VERSION 5.8 ;
BUSBITCHARS "[]" ;
DIVIDERCHAR "/" ;
UNITS
    DATABASE MICRONS 1000 ;
END UNITS

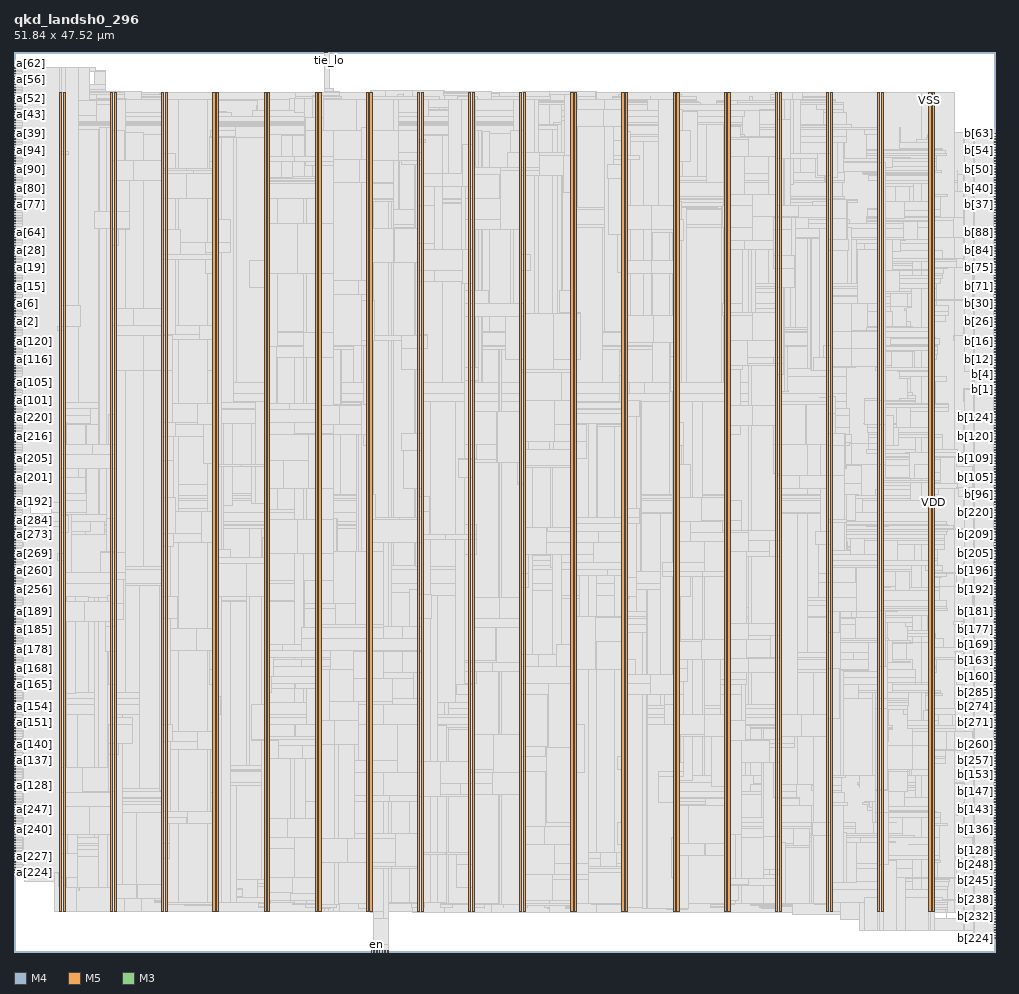
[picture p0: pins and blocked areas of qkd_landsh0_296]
MACRO qkd_landsh0_296
  FOREIGN qkd_landsh0_296 0 0 ;
  CLASS BLOCK ;
  SIZE 51.84 BY 47.52 ;
  PIN a[0]
    DIRECTION INPUT ;
    USE SIGNAL ;
    PORT
      LAYER M4 ;
        RECT  0 32.976 0.084 33 ;
    END
  END a[0]
  PIN a[100]
    DIRECTION INPUT ;
    USE SIGNAL ;
    PORT
      LAYER M4 ;
        RECT  0 28.944 0.084 28.968 ;
    END
  END a[100]
  PIN a[101]
    DIRECTION INPUT ;
    USE SIGNAL ;
    PORT
      LAYER M4 ;
        RECT  0 29.088 0.084 29.112 ;
    END
  END a[101]
  PIN a[102]
    DIRECTION INPUT ;
    USE SIGNAL ;
    PORT
      LAYER M4 ;
        RECT  0 29.232 0.084 29.256 ;
    END
  END a[102]
  PIN a[103]
    DIRECTION INPUT ;
    USE SIGNAL ;
    PORT
      LAYER M4 ;
        RECT  0 29.376 0.084 29.4 ;
    END
  END a[103]
  PIN a[104]
    DIRECTION INPUT ;
    USE SIGNAL ;
    PORT
      LAYER M4 ;
        RECT  0 29.52 0.084 29.544 ;
    END
  END a[104]
  PIN a[105]
    DIRECTION INPUT ;
    USE SIGNAL ;
    PORT
      LAYER M4 ;
        RECT  0 29.664 0.084 29.688 ;
    END
  END a[105]
  PIN a[106]
    DIRECTION INPUT ;
    USE SIGNAL ;
    PORT
      LAYER M4 ;
        RECT  0 29.808 0.084 29.832 ;
    END
  END a[106]
  PIN a[107]
    DIRECTION INPUT ;
    USE SIGNAL ;
    PORT
      LAYER M4 ;
        RECT  0 29.952 0.084 29.976 ;
    END
  END a[107]
  PIN a[108]
    DIRECTION INPUT ;
    USE SIGNAL ;
    PORT
      LAYER M4 ;
        RECT  0 30.096 0.084 30.12 ;
    END
  END a[108]
  PIN a[109]
    DIRECTION INPUT ;
    USE SIGNAL ;
    PORT
      LAYER M4 ;
        RECT  0 30.24 0.084 30.264 ;
    END
  END a[109]
  PIN a[10]
    DIRECTION INPUT ;
    USE SIGNAL ;
    PORT
      LAYER M4 ;
        RECT  0 34.416 0.084 34.44 ;
    END
  END a[10]
  PIN a[110]
    DIRECTION INPUT ;
    USE SIGNAL ;
    PORT
      LAYER M4 ;
        RECT  0 30.384 0.084 30.408 ;
    END
  END a[110]
  PIN a[111]
    DIRECTION INPUT ;
    USE SIGNAL ;
    PORT
      LAYER M4 ;
        RECT  0 30.528 0.084 30.552 ;
    END
  END a[111]
  PIN a[112]
    DIRECTION INPUT ;
    USE SIGNAL ;
    PORT
      LAYER M4 ;
        RECT  0 30.672 0.084 30.696 ;
    END
  END a[112]
  PIN a[113]
    DIRECTION INPUT ;
    USE SIGNAL ;
    PORT
      LAYER M4 ;
        RECT  0 30.816 0.084 30.84 ;
    END
  END a[113]
  PIN a[114]
    DIRECTION INPUT ;
    USE SIGNAL ;
    PORT
      LAYER M4 ;
        RECT  0 30.96 0.084 30.984 ;
    END
  END a[114]
  PIN a[115]
    DIRECTION INPUT ;
    USE SIGNAL ;
    PORT
      LAYER M4 ;
        RECT  0 31.104 0.084 31.128 ;
    END
  END a[115]
  PIN a[116]
    DIRECTION INPUT ;
    USE SIGNAL ;
    PORT
      LAYER M4 ;
        RECT  0 31.248 0.084 31.272 ;
    END
  END a[116]
  PIN a[117]
    DIRECTION INPUT ;
    USE SIGNAL ;
    PORT
      LAYER M4 ;
        RECT  0 31.392 0.084 31.416 ;
    END
  END a[117]
  PIN a[118]
    DIRECTION INPUT ;
    USE SIGNAL ;
    PORT
      LAYER M4 ;
        RECT  0 31.536 0.084 31.56 ;
    END
  END a[118]
  PIN a[119]
    DIRECTION INPUT ;
    USE SIGNAL ;
    PORT
      LAYER M4 ;
        RECT  0 31.68 0.084 31.704 ;
    END
  END a[119]
  PIN a[11]
    DIRECTION INPUT ;
    USE SIGNAL ;
    PORT
      LAYER M4 ;
        RECT  0 34.56 0.084 34.584 ;
    END
  END a[11]
  PIN a[120]
    DIRECTION INPUT ;
    USE SIGNAL ;
    PORT
      LAYER M4 ;
        RECT  0 31.824 0.084 31.848 ;
    END
  END a[120]
  PIN a[121]
    DIRECTION INPUT ;
    USE SIGNAL ;
    PORT
      LAYER M4 ;
        RECT  0 31.968 0.084 31.992 ;
    END
  END a[121]
  PIN a[122]
    DIRECTION INPUT ;
    USE SIGNAL ;
    PORT
      LAYER M4 ;
        RECT  0 32.112 0.084 32.136 ;
    END
  END a[122]
  PIN a[123]
    DIRECTION INPUT ;
    USE SIGNAL ;
    PORT
      LAYER M4 ;
        RECT  0 32.256 0.084 32.28 ;
    END
  END a[123]
  PIN a[124]
    DIRECTION INPUT ;
    USE SIGNAL ;
    PORT
      LAYER M4 ;
        RECT  0 32.4 0.084 32.424 ;
    END
  END a[124]
  PIN a[125]
    DIRECTION INPUT ;
    USE SIGNAL ;
    PORT
      LAYER M4 ;
        RECT  0 32.544 0.084 32.568 ;
    END
  END a[125]
  PIN a[126]
    DIRECTION INPUT ;
    USE SIGNAL ;
    PORT
      LAYER M4 ;
        RECT  0 32.688 0.084 32.712 ;
    END
  END a[126]
  PIN a[127]
    DIRECTION INPUT ;
    USE SIGNAL ;
    PORT
      LAYER M4 ;
        RECT  0 32.832 0.084 32.856 ;
    END
  END a[127]
  PIN a[128]
    DIRECTION INPUT ;
    USE SIGNAL ;
    PORT
      LAYER M4 ;
        RECT  0 8.784 0.084 8.808 ;
    END
  END a[128]
  PIN a[129]
    DIRECTION INPUT ;
    USE SIGNAL ;
    PORT
      LAYER M4 ;
        RECT  0 8.928 0.084 8.952 ;
    END
  END a[129]
  PIN a[12]
    DIRECTION INPUT ;
    USE SIGNAL ;
    PORT
      LAYER M4 ;
        RECT  0 34.704 0.084 34.728 ;
    END
  END a[12]
  PIN a[130]
    DIRECTION INPUT ;
    USE SIGNAL ;
    PORT
      LAYER M4 ;
        RECT  0 9.072 0.084 9.096 ;
    END
  END a[130]
  PIN a[131]
    DIRECTION INPUT ;
    USE SIGNAL ;
    PORT
      LAYER M4 ;
        RECT  0 9.216 0.084 9.24 ;
    END
  END a[131]
  PIN a[132]
    DIRECTION INPUT ;
    USE SIGNAL ;
    PORT
      LAYER M4 ;
        RECT  0 9.36 0.084 9.384 ;
    END
  END a[132]
  PIN a[133]
    DIRECTION INPUT ;
    USE SIGNAL ;
    PORT
      LAYER M4 ;
        RECT  0 9.504 0.084 9.528 ;
    END
  END a[133]
  PIN a[134]
    DIRECTION INPUT ;
    USE SIGNAL ;
    PORT
      LAYER M4 ;
        RECT  0 9.648 0.084 9.672 ;
    END
  END a[134]
  PIN a[135]
    DIRECTION INPUT ;
    USE SIGNAL ;
    PORT
      LAYER M4 ;
        RECT  0 9.792 0.084 9.816 ;
    END
  END a[135]
  PIN a[136]
    DIRECTION INPUT ;
    USE SIGNAL ;
    PORT
      LAYER M4 ;
        RECT  0 9.936 0.084 9.96 ;
    END
  END a[136]
  PIN a[137]
    DIRECTION INPUT ;
    USE SIGNAL ;
    PORT
      LAYER M4 ;
        RECT  0 10.08 0.084 10.104 ;
    END
  END a[137]
  PIN a[138]
    DIRECTION INPUT ;
    USE SIGNAL ;
    PORT
      LAYER M4 ;
        RECT  0 10.224 0.084 10.248 ;
    END
  END a[138]
  PIN a[139]
    DIRECTION INPUT ;
    USE SIGNAL ;
    PORT
      LAYER M4 ;
        RECT  0 10.368 0.084 10.392 ;
    END
  END a[139]
  PIN a[13]
    DIRECTION INPUT ;
    USE SIGNAL ;
    PORT
      LAYER M4 ;
        RECT  0 34.848 0.084 34.872 ;
    END
  END a[13]
  PIN a[140]
    DIRECTION INPUT ;
    USE SIGNAL ;
    PORT
      LAYER M4 ;
        RECT  0 10.512 0.084 10.536 ;
    END
  END a[140]
  PIN a[141]
    DIRECTION INPUT ;
    USE SIGNAL ;
    PORT
      LAYER M4 ;
        RECT  0 10.656 0.084 10.68 ;
    END
  END a[141]
  PIN a[142]
    DIRECTION INPUT ;
    USE SIGNAL ;
    PORT
      LAYER M4 ;
        RECT  0 10.8 0.084 10.824 ;
    END
  END a[142]
  PIN a[143]
    DIRECTION INPUT ;
    USE SIGNAL ;
    PORT
      LAYER M4 ;
        RECT  0 10.944 0.084 10.968 ;
    END
  END a[143]
  PIN a[144]
    DIRECTION INPUT ;
    USE SIGNAL ;
    PORT
      LAYER M4 ;
        RECT  0 11.088 0.084 11.112 ;
    END
  END a[144]
  PIN a[145]
    DIRECTION INPUT ;
    USE SIGNAL ;
    PORT
      LAYER M4 ;
        RECT  0 11.232 0.084 11.256 ;
    END
  END a[145]
  PIN a[146]
    DIRECTION INPUT ;
    USE SIGNAL ;
    PORT
      LAYER M4 ;
        RECT  0 11.376 0.084 11.4 ;
    END
  END a[146]
  PIN a[147]
    DIRECTION INPUT ;
    USE SIGNAL ;
    PORT
      LAYER M4 ;
        RECT  0 11.52 0.084 11.544 ;
    END
  END a[147]
  PIN a[148]
    DIRECTION INPUT ;
    USE SIGNAL ;
    PORT
      LAYER M4 ;
        RECT  0 11.664 0.084 11.688 ;
    END
  END a[148]
  PIN a[149]
    DIRECTION INPUT ;
    USE SIGNAL ;
    PORT
      LAYER M4 ;
        RECT  0 11.808 0.084 11.832 ;
    END
  END a[149]
  PIN a[14]
    DIRECTION INPUT ;
    USE SIGNAL ;
    PORT
      LAYER M4 ;
        RECT  0 34.992 0.084 35.016 ;
    END
  END a[14]
  PIN a[150]
    DIRECTION INPUT ;
    USE SIGNAL ;
    PORT
      LAYER M4 ;
        RECT  0 11.952 0.084 11.976 ;
    END
  END a[150]
  PIN a[151]
    DIRECTION INPUT ;
    USE SIGNAL ;
    PORT
      LAYER M4 ;
        RECT  0 12.096 0.084 12.12 ;
    END
  END a[151]
  PIN a[152]
    DIRECTION INPUT ;
    USE SIGNAL ;
    PORT
      LAYER M4 ;
        RECT  0 12.24 0.084 12.264 ;
    END
  END a[152]
  PIN a[153]
    DIRECTION INPUT ;
    USE SIGNAL ;
    PORT
      LAYER M4 ;
        RECT  0 12.384 0.084 12.408 ;
    END
  END a[153]
  PIN a[154]
    DIRECTION INPUT ;
    USE SIGNAL ;
    PORT
      LAYER M4 ;
        RECT  0 12.528 0.084 12.552 ;
    END
  END a[154]
  PIN a[155]
    DIRECTION INPUT ;
    USE SIGNAL ;
    PORT
      LAYER M4 ;
        RECT  0 12.672 0.084 12.696 ;
    END
  END a[155]
  PIN a[156]
    DIRECTION INPUT ;
    USE SIGNAL ;
    PORT
      LAYER M4 ;
        RECT  0 12.816 0.084 12.84 ;
    END
  END a[156]
  PIN a[157]
    DIRECTION INPUT ;
    USE SIGNAL ;
    PORT
      LAYER M4 ;
        RECT  0 12.96 0.084 12.984 ;
    END
  END a[157]
  PIN a[158]
    DIRECTION INPUT ;
    USE SIGNAL ;
    PORT
      LAYER M4 ;
        RECT  0 13.104 0.084 13.128 ;
    END
  END a[158]
  PIN a[159]
    DIRECTION INPUT ;
    USE SIGNAL ;
    PORT
      LAYER M4 ;
        RECT  0 13.248 0.084 13.272 ;
    END
  END a[159]
  PIN a[15]
    DIRECTION INPUT ;
    USE SIGNAL ;
    PORT
      LAYER M4 ;
        RECT  0 35.136 0.084 35.16 ;
    END
  END a[15]
  PIN a[160]
    DIRECTION INPUT ;
    USE SIGNAL ;
    PORT
      LAYER M4 ;
        RECT  0 13.392 0.084 13.416 ;
    END
  END a[160]
  PIN a[161]
    DIRECTION INPUT ;
    USE SIGNAL ;
    PORT
      LAYER M4 ;
        RECT  0 13.536 0.084 13.56 ;
    END
  END a[161]
  PIN a[162]
    DIRECTION INPUT ;
    USE SIGNAL ;
    PORT
      LAYER M4 ;
        RECT  0 13.68 0.084 13.704 ;
    END
  END a[162]
  PIN a[163]
    DIRECTION INPUT ;
    USE SIGNAL ;
    PORT
      LAYER M4 ;
        RECT  0 13.824 0.084 13.848 ;
    END
  END a[163]
  PIN a[164]
    DIRECTION INPUT ;
    USE SIGNAL ;
    PORT
      LAYER M4 ;
        RECT  0 13.968 0.084 13.992 ;
    END
  END a[164]
  PIN a[165]
    DIRECTION INPUT ;
    USE SIGNAL ;
    PORT
      LAYER M4 ;
        RECT  0 14.112 0.084 14.136 ;
    END
  END a[165]
  PIN a[166]
    DIRECTION INPUT ;
    USE SIGNAL ;
    PORT
      LAYER M4 ;
        RECT  0 14.256 0.084 14.28 ;
    END
  END a[166]
  PIN a[167]
    DIRECTION INPUT ;
    USE SIGNAL ;
    PORT
      LAYER M4 ;
        RECT  0 14.4 0.084 14.424 ;
    END
  END a[167]
  PIN a[168]
    DIRECTION INPUT ;
    USE SIGNAL ;
    PORT
      LAYER M4 ;
        RECT  0 14.544 0.084 14.568 ;
    END
  END a[168]
  PIN a[169]
    DIRECTION INPUT ;
    USE SIGNAL ;
    PORT
      LAYER M4 ;
        RECT  0 14.688 0.084 14.712 ;
    END
  END a[169]
  PIN a[16]
    DIRECTION INPUT ;
    USE SIGNAL ;
    PORT
      LAYER M4 ;
        RECT  0 35.28 0.084 35.304 ;
    END
  END a[16]
  PIN a[170]
    DIRECTION INPUT ;
    USE SIGNAL ;
    PORT
      LAYER M4 ;
        RECT  0 14.832 0.084 14.856 ;
    END
  END a[170]
  PIN a[171]
    DIRECTION INPUT ;
    USE SIGNAL ;
    PORT
      LAYER M4 ;
        RECT  0 14.976 0.084 15 ;
    END
  END a[171]
  PIN a[172]
    DIRECTION INPUT ;
    USE SIGNAL ;
    PORT
      LAYER M4 ;
        RECT  0 15.12 0.084 15.144 ;
    END
  END a[172]
  PIN a[173]
    DIRECTION INPUT ;
    USE SIGNAL ;
    PORT
      LAYER M4 ;
        RECT  0 15.264 0.084 15.288 ;
    END
  END a[173]
  PIN a[174]
    DIRECTION INPUT ;
    USE SIGNAL ;
    PORT
      LAYER M4 ;
        RECT  0 15.408 0.084 15.432 ;
    END
  END a[174]
  PIN a[175]
    DIRECTION INPUT ;
    USE SIGNAL ;
    PORT
      LAYER M4 ;
        RECT  0 15.552 0.084 15.576 ;
    END
  END a[175]
  PIN a[176]
    DIRECTION INPUT ;
    USE SIGNAL ;
    PORT
      LAYER M4 ;
        RECT  0 15.696 0.084 15.72 ;
    END
  END a[176]
  PIN a[177]
    DIRECTION INPUT ;
    USE SIGNAL ;
    PORT
      LAYER M4 ;
        RECT  0 15.84 0.084 15.864 ;
    END
  END a[177]
  PIN a[178]
    DIRECTION INPUT ;
    USE SIGNAL ;
    PORT
      LAYER M4 ;
        RECT  0 15.984 0.084 16.008 ;
    END
  END a[178]
  PIN a[179]
    DIRECTION INPUT ;
    USE SIGNAL ;
    PORT
      LAYER M4 ;
        RECT  0 16.128 0.084 16.152 ;
    END
  END a[179]
  PIN a[17]
    DIRECTION INPUT ;
    USE SIGNAL ;
    PORT
      LAYER M4 ;
        RECT  0 35.424 0.084 35.448 ;
    END
  END a[17]
  PIN a[180]
    DIRECTION INPUT ;
    USE SIGNAL ;
    PORT
      LAYER M4 ;
        RECT  0 16.272 0.084 16.296 ;
    END
  END a[180]
  PIN a[181]
    DIRECTION INPUT ;
    USE SIGNAL ;
    PORT
      LAYER M4 ;
        RECT  0 16.416 0.084 16.44 ;
    END
  END a[181]
  PIN a[182]
    DIRECTION INPUT ;
    USE SIGNAL ;
    PORT
      LAYER M4 ;
        RECT  0 16.56 0.084 16.584 ;
    END
  END a[182]
  PIN a[183]
    DIRECTION INPUT ;
    USE SIGNAL ;
    PORT
      LAYER M4 ;
        RECT  0 16.704 0.084 16.728 ;
    END
  END a[183]
  PIN a[184]
    DIRECTION INPUT ;
    USE SIGNAL ;
    PORT
      LAYER M4 ;
        RECT  0 16.848 0.084 16.872 ;
    END
  END a[184]
  PIN a[185]
    DIRECTION INPUT ;
    USE SIGNAL ;
    PORT
      LAYER M4 ;
        RECT  0 16.992 0.084 17.016 ;
    END
  END a[185]
  PIN a[186]
    DIRECTION INPUT ;
    USE SIGNAL ;
    PORT
      LAYER M4 ;
        RECT  0 17.136 0.084 17.16 ;
    END
  END a[186]
  PIN a[187]
    DIRECTION INPUT ;
    USE SIGNAL ;
    PORT
      LAYER M4 ;
        RECT  0 17.28 0.084 17.304 ;
    END
  END a[187]
  PIN a[188]
    DIRECTION INPUT ;
    USE SIGNAL ;
    PORT
      LAYER M4 ;
        RECT  0 17.424 0.084 17.448 ;
    END
  END a[188]
  PIN a[189]
    DIRECTION INPUT ;
    USE SIGNAL ;
    PORT
      LAYER M4 ;
        RECT  0 17.568 0.084 17.592 ;
    END
  END a[189]
  PIN a[18]
    DIRECTION INPUT ;
    USE SIGNAL ;
    PORT
      LAYER M4 ;
        RECT  0 35.568 0.084 35.592 ;
    END
  END a[18]
  PIN a[190]
    DIRECTION INPUT ;
    USE SIGNAL ;
    PORT
      LAYER M4 ;
        RECT  0 17.712 0.084 17.736 ;
    END
  END a[190]
  PIN a[191]
    DIRECTION INPUT ;
    USE SIGNAL ;
    PORT
      LAYER M4 ;
        RECT  0 17.856 0.084 17.88 ;
    END
  END a[191]
  PIN a[192]
    DIRECTION INPUT ;
    USE SIGNAL ;
    PORT
      LAYER M4 ;
        RECT  0 23.76 0.084 23.784 ;
    END
  END a[192]
  PIN a[193]
    DIRECTION INPUT ;
    USE SIGNAL ;
    PORT
      LAYER M4 ;
        RECT  0 23.904 0.084 23.928 ;
    END
  END a[193]
  PIN a[194]
    DIRECTION INPUT ;
    USE SIGNAL ;
    PORT
      LAYER M4 ;
        RECT  0 24.048 0.084 24.072 ;
    END
  END a[194]
  PIN a[195]
    DIRECTION INPUT ;
    USE SIGNAL ;
    PORT
      LAYER M4 ;
        RECT  0 24.192 0.084 24.216 ;
    END
  END a[195]
  PIN a[196]
    DIRECTION INPUT ;
    USE SIGNAL ;
    PORT
      LAYER M4 ;
        RECT  0 24.336 0.084 24.36 ;
    END
  END a[196]
  PIN a[197]
    DIRECTION INPUT ;
    USE SIGNAL ;
    PORT
      LAYER M4 ;
        RECT  0 24.48 0.084 24.504 ;
    END
  END a[197]
  PIN a[198]
    DIRECTION INPUT ;
    USE SIGNAL ;
    PORT
      LAYER M4 ;
        RECT  0 24.624 0.084 24.648 ;
    END
  END a[198]
  PIN a[199]
    DIRECTION INPUT ;
    USE SIGNAL ;
    PORT
      LAYER M4 ;
        RECT  0 24.768 0.084 24.792 ;
    END
  END a[199]
  PIN a[19]
    DIRECTION INPUT ;
    USE SIGNAL ;
    PORT
      LAYER M4 ;
        RECT  0 35.712 0.084 35.736 ;
    END
  END a[19]
  PIN a[1]
    DIRECTION INPUT ;
    USE SIGNAL ;
    PORT
      LAYER M4 ;
        RECT  0 33.12 0.084 33.144 ;
    END
  END a[1]
  PIN a[200]
    DIRECTION INPUT ;
    USE SIGNAL ;
    PORT
      LAYER M4 ;
        RECT  0 24.912 0.084 24.936 ;
    END
  END a[200]
  PIN a[201]
    DIRECTION INPUT ;
    USE SIGNAL ;
    PORT
      LAYER M4 ;
        RECT  0 25.056 0.084 25.08 ;
    END
  END a[201]
  PIN a[202]
    DIRECTION INPUT ;
    USE SIGNAL ;
    PORT
      LAYER M4 ;
        RECT  0 25.2 0.084 25.224 ;
    END
  END a[202]
  PIN a[203]
    DIRECTION INPUT ;
    USE SIGNAL ;
    PORT
      LAYER M4 ;
        RECT  0 25.344 0.084 25.368 ;
    END
  END a[203]
  PIN a[204]
    DIRECTION INPUT ;
    USE SIGNAL ;
    PORT
      LAYER M4 ;
        RECT  0 25.488 0.084 25.512 ;
    END
  END a[204]
  PIN a[205]
    DIRECTION INPUT ;
    USE SIGNAL ;
    PORT
      LAYER M4 ;
        RECT  0 25.632 0.084 25.656 ;
    END
  END a[205]
  PIN a[206]
    DIRECTION INPUT ;
    USE SIGNAL ;
    PORT
      LAYER M4 ;
        RECT  0 25.776 0.084 25.8 ;
    END
  END a[206]
  PIN a[207]
    DIRECTION INPUT ;
    USE SIGNAL ;
    PORT
      LAYER M4 ;
        RECT  0 25.92 0.084 25.944 ;
    END
  END a[207]
  PIN a[208]
    DIRECTION INPUT ;
    USE SIGNAL ;
    PORT
      LAYER M4 ;
        RECT  0 26.064 0.084 26.088 ;
    END
  END a[208]
  PIN a[209]
    DIRECTION INPUT ;
    USE SIGNAL ;
    PORT
      LAYER M4 ;
        RECT  0 26.208 0.084 26.232 ;
    END
  END a[209]
  PIN a[20]
    DIRECTION INPUT ;
    USE SIGNAL ;
    PORT
      LAYER M4 ;
        RECT  0 35.856 0.084 35.88 ;
    END
  END a[20]
  PIN a[210]
    DIRECTION INPUT ;
    USE SIGNAL ;
    PORT
      LAYER M4 ;
        RECT  0 26.352 0.084 26.376 ;
    END
  END a[210]
  PIN a[211]
    DIRECTION INPUT ;
    USE SIGNAL ;
    PORT
      LAYER M4 ;
        RECT  0 26.496 0.084 26.52 ;
    END
  END a[211]
  PIN a[212]
    DIRECTION INPUT ;
    USE SIGNAL ;
    PORT
      LAYER M4 ;
        RECT  0 26.64 0.084 26.664 ;
    END
  END a[212]
  PIN a[213]
    DIRECTION INPUT ;
    USE SIGNAL ;
    PORT
      LAYER M4 ;
        RECT  0 26.784 0.084 26.808 ;
    END
  END a[213]
  PIN a[214]
    DIRECTION INPUT ;
    USE SIGNAL ;
    PORT
      LAYER M4 ;
        RECT  0 26.928 0.084 26.952 ;
    END
  END a[214]
  PIN a[215]
    DIRECTION INPUT ;
    USE SIGNAL ;
    PORT
      LAYER M4 ;
        RECT  0 27.072 0.084 27.096 ;
    END
  END a[215]
  PIN a[216]
    DIRECTION INPUT ;
    USE SIGNAL ;
    PORT
      LAYER M4 ;
        RECT  0 27.216 0.084 27.24 ;
    END
  END a[216]
  PIN a[217]
    DIRECTION INPUT ;
    USE SIGNAL ;
    PORT
      LAYER M4 ;
        RECT  0 27.36 0.084 27.384 ;
    END
  END a[217]
  PIN a[218]
    DIRECTION INPUT ;
    USE SIGNAL ;
    PORT
      LAYER M4 ;
        RECT  0 27.504 0.084 27.528 ;
    END
  END a[218]
  PIN a[219]
    DIRECTION INPUT ;
    USE SIGNAL ;
    PORT
      LAYER M4 ;
        RECT  0 27.648 0.084 27.672 ;
    END
  END a[219]
  PIN a[21]
    DIRECTION INPUT ;
    USE SIGNAL ;
    PORT
      LAYER M4 ;
        RECT  0 36 0.084 36.024 ;
    END
  END a[21]
  PIN a[220]
    DIRECTION INPUT ;
    USE SIGNAL ;
    PORT
      LAYER M4 ;
        RECT  0 27.792 0.084 27.816 ;
    END
  END a[220]
  PIN a[221]
    DIRECTION INPUT ;
    USE SIGNAL ;
    PORT
      LAYER M4 ;
        RECT  0 27.936 0.084 27.96 ;
    END
  END a[221]
  PIN a[222]
    DIRECTION INPUT ;
    USE SIGNAL ;
    PORT
      LAYER M4 ;
        RECT  0 28.08 0.084 28.104 ;
    END
  END a[222]
  PIN a[223]
    DIRECTION INPUT ;
    USE SIGNAL ;
    PORT
      LAYER M4 ;
        RECT  0 28.224 0.084 28.248 ;
    END
  END a[223]
  PIN a[224]
    DIRECTION INPUT ;
    USE SIGNAL ;
    PORT
      LAYER M4 ;
        RECT  0 4.176 0.084 4.2 ;
    END
  END a[224]
  PIN a[225]
    DIRECTION INPUT ;
    USE SIGNAL ;
    PORT
      LAYER M4 ;
        RECT  0 4.32 0.084 4.344 ;
    END
  END a[225]
  PIN a[226]
    DIRECTION INPUT ;
    USE SIGNAL ;
    PORT
      LAYER M4 ;
        RECT  0 4.464 0.084 4.488 ;
    END
  END a[226]
  PIN a[227]
    DIRECTION INPUT ;
    USE SIGNAL ;
    PORT
      LAYER M4 ;
        RECT  0 4.608 0.084 4.632 ;
    END
  END a[227]
  PIN a[228]
    DIRECTION INPUT ;
    USE SIGNAL ;
    PORT
      LAYER M4 ;
        RECT  0 4.752 0.084 4.776 ;
    END
  END a[228]
  PIN a[229]
    DIRECTION INPUT ;
    USE SIGNAL ;
    PORT
      LAYER M4 ;
        RECT  0 4.896 0.084 4.92 ;
    END
  END a[229]
  PIN a[22]
    DIRECTION INPUT ;
    USE SIGNAL ;
    PORT
      LAYER M4 ;
        RECT  0 36.144 0.084 36.168 ;
    END
  END a[22]
  PIN a[230]
    DIRECTION INPUT ;
    USE SIGNAL ;
    PORT
      LAYER M4 ;
        RECT  0 5.04 0.084 5.064 ;
    END
  END a[230]
  PIN a[231]
    DIRECTION INPUT ;
    USE SIGNAL ;
    PORT
      LAYER M4 ;
        RECT  0 5.184 0.084 5.208 ;
    END
  END a[231]
  PIN a[232]
    DIRECTION INPUT ;
    USE SIGNAL ;
    PORT
      LAYER M4 ;
        RECT  0 5.328 0.084 5.352 ;
    END
  END a[232]
  PIN a[233]
    DIRECTION INPUT ;
    USE SIGNAL ;
    PORT
      LAYER M4 ;
        RECT  0 5.472 0.084 5.496 ;
    END
  END a[233]
  PIN a[234]
    DIRECTION INPUT ;
    USE SIGNAL ;
    PORT
      LAYER M4 ;
        RECT  0 5.616 0.084 5.64 ;
    END
  END a[234]
  PIN a[235]
    DIRECTION INPUT ;
    USE SIGNAL ;
    PORT
      LAYER M4 ;
        RECT  0 5.76 0.084 5.784 ;
    END
  END a[235]
  PIN a[236]
    DIRECTION INPUT ;
    USE SIGNAL ;
    PORT
      LAYER M4 ;
        RECT  0 5.904 0.084 5.928 ;
    END
  END a[236]
  PIN a[237]
    DIRECTION INPUT ;
    USE SIGNAL ;
    PORT
      LAYER M4 ;
        RECT  0 6.048 0.084 6.072 ;
    END
  END a[237]
  PIN a[238]
    DIRECTION INPUT ;
    USE SIGNAL ;
    PORT
      LAYER M4 ;
        RECT  0 6.192 0.084 6.216 ;
    END
  END a[238]
  PIN a[239]
    DIRECTION INPUT ;
    USE SIGNAL ;
    PORT
      LAYER M4 ;
        RECT  0 6.336 0.084 6.36 ;
    END
  END a[239]
  PIN a[23]
    DIRECTION INPUT ;
    USE SIGNAL ;
    PORT
      LAYER M4 ;
        RECT  0 36.288 0.084 36.312 ;
    END
  END a[23]
  PIN a[240]
    DIRECTION INPUT ;
    USE SIGNAL ;
    PORT
      LAYER M4 ;
        RECT  0 6.48 0.084 6.504 ;
    END
  END a[240]
  PIN a[241]
    DIRECTION INPUT ;
    USE SIGNAL ;
    PORT
      LAYER M4 ;
        RECT  0 6.624 0.084 6.648 ;
    END
  END a[241]
  PIN a[242]
    DIRECTION INPUT ;
    USE SIGNAL ;
    PORT
      LAYER M4 ;
        RECT  0 6.768 0.084 6.792 ;
    END
  END a[242]
  PIN a[243]
    DIRECTION INPUT ;
    USE SIGNAL ;
    PORT
      LAYER M4 ;
        RECT  0 6.912 0.084 6.936 ;
    END
  END a[243]
  PIN a[244]
    DIRECTION INPUT ;
    USE SIGNAL ;
    PORT
      LAYER M4 ;
        RECT  0 7.056 0.084 7.08 ;
    END
  END a[244]
  PIN a[245]
    DIRECTION INPUT ;
    USE SIGNAL ;
    PORT
      LAYER M4 ;
        RECT  0 7.2 0.084 7.224 ;
    END
  END a[245]
  PIN a[246]
    DIRECTION INPUT ;
    USE SIGNAL ;
    PORT
      LAYER M4 ;
        RECT  0 7.344 0.084 7.368 ;
    END
  END a[246]
  PIN a[247]
    DIRECTION INPUT ;
    USE SIGNAL ;
    PORT
      LAYER M4 ;
        RECT  0 7.488 0.084 7.512 ;
    END
  END a[247]
  PIN a[248]
    DIRECTION INPUT ;
    USE SIGNAL ;
    PORT
      LAYER M4 ;
        RECT  0 7.632 0.084 7.656 ;
    END
  END a[248]
  PIN a[249]
    DIRECTION INPUT ;
    USE SIGNAL ;
    PORT
      LAYER M4 ;
        RECT  0 7.776 0.084 7.8 ;
    END
  END a[249]
  PIN a[24]
    DIRECTION INPUT ;
    USE SIGNAL ;
    PORT
      LAYER M4 ;
        RECT  0 36.432 0.084 36.456 ;
    END
  END a[24]
  PIN a[250]
    DIRECTION INPUT ;
    USE SIGNAL ;
    PORT
      LAYER M4 ;
        RECT  0 7.92 0.084 7.944 ;
    END
  END a[250]
  PIN a[251]
    DIRECTION INPUT ;
    USE SIGNAL ;
    PORT
      LAYER M4 ;
        RECT  0 8.064 0.084 8.088 ;
    END
  END a[251]
  PIN a[252]
    DIRECTION INPUT ;
    USE SIGNAL ;
    PORT
      LAYER M4 ;
        RECT  0 8.208 0.084 8.232 ;
    END
  END a[252]
  PIN a[253]
    DIRECTION INPUT ;
    USE SIGNAL ;
    PORT
      LAYER M4 ;
        RECT  0 8.352 0.084 8.376 ;
    END
  END a[253]
  PIN a[254]
    DIRECTION INPUT ;
    USE SIGNAL ;
    PORT
      LAYER M4 ;
        RECT  0 8.496 0.084 8.52 ;
    END
  END a[254]
  PIN a[255]
    DIRECTION INPUT ;
    USE SIGNAL ;
    PORT
      LAYER M4 ;
        RECT  0 8.64 0.084 8.664 ;
    END
  END a[255]
  PIN a[256]
    DIRECTION INPUT ;
    USE SIGNAL ;
    PORT
      LAYER M4 ;
        RECT  0 19.152 0.084 19.176 ;
    END
  END a[256]
  PIN a[257]
    DIRECTION INPUT ;
    USE SIGNAL ;
    PORT
      LAYER M4 ;
        RECT  0 19.296 0.084 19.32 ;
    END
  END a[257]
  PIN a[258]
    DIRECTION INPUT ;
    USE SIGNAL ;
    PORT
      LAYER M4 ;
        RECT  0 19.44 0.084 19.464 ;
    END
  END a[258]
  PIN a[259]
    DIRECTION INPUT ;
    USE SIGNAL ;
    PORT
      LAYER M4 ;
        RECT  0 19.584 0.084 19.608 ;
    END
  END a[259]
  PIN a[25]
    DIRECTION INPUT ;
    USE SIGNAL ;
    PORT
      LAYER M4 ;
        RECT  0 36.576 0.084 36.6 ;
    END
  END a[25]
  PIN a[260]
    DIRECTION INPUT ;
    USE SIGNAL ;
    PORT
      LAYER M4 ;
        RECT  0 19.728 0.084 19.752 ;
    END
  END a[260]
  PIN a[261]
    DIRECTION INPUT ;
    USE SIGNAL ;
    PORT
      LAYER M4 ;
        RECT  0 19.872 0.084 19.896 ;
    END
  END a[261]
  PIN a[262]
    DIRECTION INPUT ;
    USE SIGNAL ;
    PORT
      LAYER M4 ;
        RECT  0 20.016 0.084 20.04 ;
    END
  END a[262]
  PIN a[263]
    DIRECTION INPUT ;
    USE SIGNAL ;
    PORT
      LAYER M4 ;
        RECT  0 20.16 0.084 20.184 ;
    END
  END a[263]
  PIN a[264]
    DIRECTION INPUT ;
    USE SIGNAL ;
    PORT
      LAYER M4 ;
        RECT  0 20.304 0.084 20.328 ;
    END
  END a[264]
  PIN a[265]
    DIRECTION INPUT ;
    USE SIGNAL ;
    PORT
      LAYER M4 ;
        RECT  0 20.448 0.084 20.472 ;
    END
  END a[265]
  PIN a[266]
    DIRECTION INPUT ;
    USE SIGNAL ;
    PORT
      LAYER M4 ;
        RECT  0 20.592 0.084 20.616 ;
    END
  END a[266]
  PIN a[267]
    DIRECTION INPUT ;
    USE SIGNAL ;
    PORT
      LAYER M4 ;
        RECT  0 20.736 0.084 20.76 ;
    END
  END a[267]
  PIN a[268]
    DIRECTION INPUT ;
    USE SIGNAL ;
    PORT
      LAYER M4 ;
        RECT  0 20.88 0.084 20.904 ;
    END
  END a[268]
  PIN a[269]
    DIRECTION INPUT ;
    USE SIGNAL ;
    PORT
      LAYER M4 ;
        RECT  0 21.024 0.084 21.048 ;
    END
  END a[269]
  PIN a[26]
    DIRECTION INPUT ;
    USE SIGNAL ;
    PORT
      LAYER M4 ;
        RECT  0 36.72 0.084 36.744 ;
    END
  END a[26]
  PIN a[270]
    DIRECTION INPUT ;
    USE SIGNAL ;
    PORT
      LAYER M4 ;
        RECT  0 21.168 0.084 21.192 ;
    END
  END a[270]
  PIN a[271]
    DIRECTION INPUT ;
    USE SIGNAL ;
    PORT
      LAYER M4 ;
        RECT  0 21.312 0.084 21.336 ;
    END
  END a[271]
  PIN a[272]
    DIRECTION INPUT ;
    USE SIGNAL ;
    PORT
      LAYER M4 ;
        RECT  0 21.456 0.084 21.48 ;
    END
  END a[272]
  PIN a[273]
    DIRECTION INPUT ;
    USE SIGNAL ;
    PORT
      LAYER M4 ;
        RECT  0 21.6 0.084 21.624 ;
    END
  END a[273]
  PIN a[274]
    DIRECTION INPUT ;
    USE SIGNAL ;
    PORT
      LAYER M4 ;
        RECT  0 21.744 0.084 21.768 ;
    END
  END a[274]
  PIN a[275]
    DIRECTION INPUT ;
    USE SIGNAL ;
    PORT
      LAYER M4 ;
        RECT  0 21.888 0.084 21.912 ;
    END
  END a[275]
  PIN a[276]
    DIRECTION INPUT ;
    USE SIGNAL ;
    PORT
      LAYER M4 ;
        RECT  0 22.032 0.084 22.056 ;
    END
  END a[276]
  PIN a[277]
    DIRECTION INPUT ;
    USE SIGNAL ;
    PORT
      LAYER M4 ;
        RECT  0 22.176 0.084 22.2 ;
    END
  END a[277]
  PIN a[278]
    DIRECTION INPUT ;
    USE SIGNAL ;
    PORT
      LAYER M4 ;
        RECT  0 22.32 0.084 22.344 ;
    END
  END a[278]
  PIN a[279]
    DIRECTION INPUT ;
    USE SIGNAL ;
    PORT
      LAYER M4 ;
        RECT  0 22.464 0.084 22.488 ;
    END
  END a[279]
  PIN a[27]
    DIRECTION INPUT ;
    USE SIGNAL ;
    PORT
      LAYER M4 ;
        RECT  0 36.864 0.084 36.888 ;
    END
  END a[27]
  PIN a[280]
    DIRECTION INPUT ;
    USE SIGNAL ;
    PORT
      LAYER M4 ;
        RECT  0 22.608 0.084 22.632 ;
    END
  END a[280]
  PIN a[281]
    DIRECTION INPUT ;
    USE SIGNAL ;
    PORT
      LAYER M4 ;
        RECT  0 22.752 0.084 22.776 ;
    END
  END a[281]
  PIN a[282]
    DIRECTION INPUT ;
    USE SIGNAL ;
    PORT
      LAYER M4 ;
        RECT  0 22.896 0.084 22.92 ;
    END
  END a[282]
  PIN a[283]
    DIRECTION INPUT ;
    USE SIGNAL ;
    PORT
      LAYER M4 ;
        RECT  0 23.04 0.084 23.064 ;
    END
  END a[283]
  PIN a[284]
    DIRECTION INPUT ;
    USE SIGNAL ;
    PORT
      LAYER M4 ;
        RECT  0 23.184 0.084 23.208 ;
    END
  END a[284]
  PIN a[285]
    DIRECTION INPUT ;
    USE SIGNAL ;
    PORT
      LAYER M4 ;
        RECT  0 23.328 0.084 23.352 ;
    END
  END a[285]
  PIN a[286]
    DIRECTION INPUT ;
    USE SIGNAL ;
    PORT
      LAYER M4 ;
        RECT  0 23.472 0.084 23.496 ;
    END
  END a[286]
  PIN a[287]
    DIRECTION INPUT ;
    USE SIGNAL ;
    PORT
      LAYER M4 ;
        RECT  0 23.616 0.084 23.64 ;
    END
  END a[287]
  PIN a[288]
    DIRECTION INPUT ;
    USE SIGNAL ;
    PORT
      LAYER M4 ;
        RECT  0 18 0.084 18.024 ;
    END
  END a[288]
  PIN a[289]
    DIRECTION INPUT ;
    USE SIGNAL ;
    PORT
      LAYER M4 ;
        RECT  0 18.144 0.084 18.168 ;
    END
  END a[289]
  PIN a[28]
    DIRECTION INPUT ;
    USE SIGNAL ;
    PORT
      LAYER M4 ;
        RECT  0 37.008 0.084 37.032 ;
    END
  END a[28]
  PIN a[290]
    DIRECTION INPUT ;
    USE SIGNAL ;
    PORT
      LAYER M4 ;
        RECT  0 18.288 0.084 18.312 ;
    END
  END a[290]
  PIN a[291]
    DIRECTION INPUT ;
    USE SIGNAL ;
    PORT
      LAYER M4 ;
        RECT  0 18.432 0.084 18.456 ;
    END
  END a[291]
  PIN a[292]
    DIRECTION INPUT ;
    USE SIGNAL ;
    PORT
      LAYER M4 ;
        RECT  0 18.576 0.084 18.6 ;
    END
  END a[292]
  PIN a[293]
    DIRECTION INPUT ;
    USE SIGNAL ;
    PORT
      LAYER M4 ;
        RECT  0 18.72 0.084 18.744 ;
    END
  END a[293]
  PIN a[294]
    DIRECTION INPUT ;
    USE SIGNAL ;
    PORT
      LAYER M4 ;
        RECT  0 18.864 0.084 18.888 ;
    END
  END a[294]
  PIN a[295]
    DIRECTION INPUT ;
    USE SIGNAL ;
    PORT
      LAYER M4 ;
        RECT  0 19.008 0.084 19.032 ;
    END
  END a[295]
  PIN a[29]
    DIRECTION INPUT ;
    USE SIGNAL ;
    PORT
      LAYER M4 ;
        RECT  0 37.152 0.084 37.176 ;
    END
  END a[29]
  PIN a[2]
    DIRECTION INPUT ;
    USE SIGNAL ;
    PORT
      LAYER M4 ;
        RECT  0 33.264 0.084 33.288 ;
    END
  END a[2]
  PIN a[30]
    DIRECTION INPUT ;
    USE SIGNAL ;
    PORT
      LAYER M4 ;
        RECT  0 37.296 0.084 37.32 ;
    END
  END a[30]
  PIN a[31]
    DIRECTION INPUT ;
    USE SIGNAL ;
    PORT
      LAYER M4 ;
        RECT  0 37.44 0.084 37.464 ;
    END
  END a[31]
  PIN a[32]
    DIRECTION INPUT ;
    USE SIGNAL ;
    PORT
      LAYER M4 ;
        RECT  0 42.192 0.084 42.216 ;
    END
  END a[32]
  PIN a[33]
    DIRECTION INPUT ;
    USE SIGNAL ;
    PORT
      LAYER M4 ;
        RECT  0 42.336 0.084 42.36 ;
    END
  END a[33]
  PIN a[34]
    DIRECTION INPUT ;
    USE SIGNAL ;
    PORT
      LAYER M4 ;
        RECT  0 42.48 0.084 42.504 ;
    END
  END a[34]
  PIN a[35]
    DIRECTION INPUT ;
    USE SIGNAL ;
    PORT
      LAYER M4 ;
        RECT  0 42.624 0.084 42.648 ;
    END
  END a[35]
  PIN a[36]
    DIRECTION INPUT ;
    USE SIGNAL ;
    PORT
      LAYER M4 ;
        RECT  0 42.768 0.084 42.792 ;
    END
  END a[36]
  PIN a[37]
    DIRECTION INPUT ;
    USE SIGNAL ;
    PORT
      LAYER M4 ;
        RECT  0 42.912 0.084 42.936 ;
    END
  END a[37]
  PIN a[38]
    DIRECTION INPUT ;
    USE SIGNAL ;
    PORT
      LAYER M4 ;
        RECT  0 43.056 0.084 43.08 ;
    END
  END a[38]
  PIN a[39]
    DIRECTION INPUT ;
    USE SIGNAL ;
    PORT
      LAYER M4 ;
        RECT  0 43.2 0.084 43.224 ;
    END
  END a[39]
  PIN a[3]
    DIRECTION INPUT ;
    USE SIGNAL ;
    PORT
      LAYER M4 ;
        RECT  0 33.408 0.084 33.432 ;
    END
  END a[3]
  PIN a[40]
    DIRECTION INPUT ;
    USE SIGNAL ;
    PORT
      LAYER M4 ;
        RECT  0 43.344 0.084 43.368 ;
    END
  END a[40]
  PIN a[41]
    DIRECTION INPUT ;
    USE SIGNAL ;
    PORT
      LAYER M4 ;
        RECT  0 43.488 0.084 43.512 ;
    END
  END a[41]
  PIN a[42]
    DIRECTION INPUT ;
    USE SIGNAL ;
    PORT
      LAYER M4 ;
        RECT  0 43.632 0.084 43.656 ;
    END
  END a[42]
  PIN a[43]
    DIRECTION INPUT ;
    USE SIGNAL ;
    PORT
      LAYER M4 ;
        RECT  0 43.776 0.084 43.8 ;
    END
  END a[43]
  PIN a[44]
    DIRECTION INPUT ;
    USE SIGNAL ;
    PORT
      LAYER M4 ;
        RECT  0 43.92 0.084 43.944 ;
    END
  END a[44]
  PIN a[45]
    DIRECTION INPUT ;
    USE SIGNAL ;
    PORT
      LAYER M4 ;
        RECT  0 44.064 0.084 44.088 ;
    END
  END a[45]
  PIN a[46]
    DIRECTION INPUT ;
    USE SIGNAL ;
    PORT
      LAYER M4 ;
        RECT  0 44.208 0.084 44.232 ;
    END
  END a[46]
  PIN a[47]
    DIRECTION INPUT ;
    USE SIGNAL ;
    PORT
      LAYER M4 ;
        RECT  0 44.352 0.084 44.376 ;
    END
  END a[47]
  PIN a[48]
    DIRECTION INPUT ;
    USE SIGNAL ;
    PORT
      LAYER M4 ;
        RECT  0 44.496 0.084 44.52 ;
    END
  END a[48]
  PIN a[49]
    DIRECTION INPUT ;
    USE SIGNAL ;
    PORT
      LAYER M4 ;
        RECT  0 44.64 0.084 44.664 ;
    END
  END a[49]
  PIN a[4]
    DIRECTION INPUT ;
    USE SIGNAL ;
    PORT
      LAYER M4 ;
        RECT  0 33.552 0.084 33.576 ;
    END
  END a[4]
  PIN a[50]
    DIRECTION INPUT ;
    USE SIGNAL ;
    PORT
      LAYER M4 ;
        RECT  0 44.784 0.084 44.808 ;
    END
  END a[50]
  PIN a[51]
    DIRECTION INPUT ;
    USE SIGNAL ;
    PORT
      LAYER M4 ;
        RECT  0 44.928 0.084 44.952 ;
    END
  END a[51]
  PIN a[52]
    DIRECTION INPUT ;
    USE SIGNAL ;
    PORT
      LAYER M4 ;
        RECT  0 45.072 0.084 45.096 ;
    END
  END a[52]
  PIN a[53]
    DIRECTION INPUT ;
    USE SIGNAL ;
    PORT
      LAYER M4 ;
        RECT  0 45.216 0.084 45.24 ;
    END
  END a[53]
  PIN a[54]
    DIRECTION INPUT ;
    USE SIGNAL ;
    PORT
      LAYER M4 ;
        RECT  0 45.36 0.084 45.384 ;
    END
  END a[54]
  PIN a[55]
    DIRECTION INPUT ;
    USE SIGNAL ;
    PORT
      LAYER M4 ;
        RECT  0 45.504 0.084 45.528 ;
    END
  END a[55]
  PIN a[56]
    DIRECTION INPUT ;
    USE SIGNAL ;
    PORT
      LAYER M4 ;
        RECT  0 45.648 0.084 45.672 ;
    END
  END a[56]
  PIN a[57]
    DIRECTION INPUT ;
    USE SIGNAL ;
    PORT
      LAYER M4 ;
        RECT  0 45.792 0.084 45.816 ;
    END
  END a[57]
  PIN a[58]
    DIRECTION INPUT ;
    USE SIGNAL ;
    PORT
      LAYER M4 ;
        RECT  0 45.936 0.084 45.96 ;
    END
  END a[58]
  PIN a[59]
    DIRECTION INPUT ;
    USE SIGNAL ;
    PORT
      LAYER M4 ;
        RECT  0 46.08 0.084 46.104 ;
    END
  END a[59]
  PIN a[5]
    DIRECTION INPUT ;
    USE SIGNAL ;
    PORT
      LAYER M4 ;
        RECT  0 33.696 0.084 33.72 ;
    END
  END a[5]
  PIN a[60]
    DIRECTION INPUT ;
    USE SIGNAL ;
    PORT
      LAYER M4 ;
        RECT  0 46.224 0.084 46.248 ;
    END
  END a[60]
  PIN a[61]
    DIRECTION INPUT ;
    USE SIGNAL ;
    PORT
      LAYER M4 ;
        RECT  0 46.368 0.084 46.392 ;
    END
  END a[61]
  PIN a[62]
    DIRECTION INPUT ;
    USE SIGNAL ;
    PORT
      LAYER M4 ;
        RECT  0 46.512 0.084 46.536 ;
    END
  END a[62]
  PIN a[63]
    DIRECTION INPUT ;
    USE SIGNAL ;
    PORT
      LAYER M4 ;
        RECT  0 46.656 0.084 46.68 ;
    END
  END a[63]
  PIN a[64]
    DIRECTION INPUT ;
    USE SIGNAL ;
    PORT
      LAYER M4 ;
        RECT  0 37.584 0.084 37.608 ;
    END
  END a[64]
  PIN a[65]
    DIRECTION INPUT ;
    USE SIGNAL ;
    PORT
      LAYER M4 ;
        RECT  0 37.728 0.084 37.752 ;
    END
  END a[65]
  PIN a[66]
    DIRECTION INPUT ;
    USE SIGNAL ;
    PORT
      LAYER M4 ;
        RECT  0 37.872 0.084 37.896 ;
    END
  END a[66]
  PIN a[67]
    DIRECTION INPUT ;
    USE SIGNAL ;
    PORT
      LAYER M4 ;
        RECT  0 38.016 0.084 38.04 ;
    END
  END a[67]
  PIN a[68]
    DIRECTION INPUT ;
    USE SIGNAL ;
    PORT
      LAYER M4 ;
        RECT  0 38.16 0.084 38.184 ;
    END
  END a[68]
  PIN a[69]
    DIRECTION INPUT ;
    USE SIGNAL ;
    PORT
      LAYER M4 ;
        RECT  0 38.304 0.084 38.328 ;
    END
  END a[69]
  PIN a[6]
    DIRECTION INPUT ;
    USE SIGNAL ;
    PORT
      LAYER M4 ;
        RECT  0 33.84 0.084 33.864 ;
    END
  END a[6]
  PIN a[70]
    DIRECTION INPUT ;
    USE SIGNAL ;
    PORT
      LAYER M4 ;
        RECT  0 38.448 0.084 38.472 ;
    END
  END a[70]
  PIN a[71]
    DIRECTION INPUT ;
    USE SIGNAL ;
    PORT
      LAYER M4 ;
        RECT  0 38.592 0.084 38.616 ;
    END
  END a[71]
  PIN a[72]
    DIRECTION INPUT ;
    USE SIGNAL ;
    PORT
      LAYER M4 ;
        RECT  0 38.736 0.084 38.76 ;
    END
  END a[72]
  PIN a[73]
    DIRECTION INPUT ;
    USE SIGNAL ;
    PORT
      LAYER M4 ;
        RECT  0 38.88 0.084 38.904 ;
    END
  END a[73]
  PIN a[74]
    DIRECTION INPUT ;
    USE SIGNAL ;
    PORT
      LAYER M4 ;
        RECT  0 39.024 0.084 39.048 ;
    END
  END a[74]
  PIN a[75]
    DIRECTION INPUT ;
    USE SIGNAL ;
    PORT
      LAYER M4 ;
        RECT  0 39.168 0.084 39.192 ;
    END
  END a[75]
  PIN a[76]
    DIRECTION INPUT ;
    USE SIGNAL ;
    PORT
      LAYER M4 ;
        RECT  0 39.312 0.084 39.336 ;
    END
  END a[76]
  PIN a[77]
    DIRECTION INPUT ;
    USE SIGNAL ;
    PORT
      LAYER M4 ;
        RECT  0 39.456 0.084 39.48 ;
    END
  END a[77]
  PIN a[78]
    DIRECTION INPUT ;
    USE SIGNAL ;
    PORT
      LAYER M4 ;
        RECT  0 39.6 0.084 39.624 ;
    END
  END a[78]
  PIN a[79]
    DIRECTION INPUT ;
    USE SIGNAL ;
    PORT
      LAYER M4 ;
        RECT  0 39.744 0.084 39.768 ;
    END
  END a[79]
  PIN a[7]
    DIRECTION INPUT ;
    USE SIGNAL ;
    PORT
      LAYER M4 ;
        RECT  0 33.984 0.084 34.008 ;
    END
  END a[7]
  PIN a[80]
    DIRECTION INPUT ;
    USE SIGNAL ;
    PORT
      LAYER M4 ;
        RECT  0 39.888 0.084 39.912 ;
    END
  END a[80]
  PIN a[81]
    DIRECTION INPUT ;
    USE SIGNAL ;
    PORT
      LAYER M4 ;
        RECT  0 40.032 0.084 40.056 ;
    END
  END a[81]
  PIN a[82]
    DIRECTION INPUT ;
    USE SIGNAL ;
    PORT
      LAYER M4 ;
        RECT  0 40.176 0.084 40.2 ;
    END
  END a[82]
  PIN a[83]
    DIRECTION INPUT ;
    USE SIGNAL ;
    PORT
      LAYER M4 ;
        RECT  0 40.32 0.084 40.344 ;
    END
  END a[83]
  PIN a[84]
    DIRECTION INPUT ;
    USE SIGNAL ;
    PORT
      LAYER M4 ;
        RECT  0 40.464 0.084 40.488 ;
    END
  END a[84]
  PIN a[85]
    DIRECTION INPUT ;
    USE SIGNAL ;
    PORT
      LAYER M4 ;
        RECT  0 40.608 0.084 40.632 ;
    END
  END a[85]
  PIN a[86]
    DIRECTION INPUT ;
    USE SIGNAL ;
    PORT
      LAYER M4 ;
        RECT  0 40.752 0.084 40.776 ;
    END
  END a[86]
  PIN a[87]
    DIRECTION INPUT ;
    USE SIGNAL ;
    PORT
      LAYER M4 ;
        RECT  0 40.896 0.084 40.92 ;
    END
  END a[87]
  PIN a[88]
    DIRECTION INPUT ;
    USE SIGNAL ;
    PORT
      LAYER M4 ;
        RECT  0 41.04 0.084 41.064 ;
    END
  END a[88]
  PIN a[89]
    DIRECTION INPUT ;
    USE SIGNAL ;
    PORT
      LAYER M4 ;
        RECT  0 41.184 0.084 41.208 ;
    END
  END a[89]
  PIN a[8]
    DIRECTION INPUT ;
    USE SIGNAL ;
    PORT
      LAYER M4 ;
        RECT  0 34.128 0.084 34.152 ;
    END
  END a[8]
  PIN a[90]
    DIRECTION INPUT ;
    USE SIGNAL ;
    PORT
      LAYER M4 ;
        RECT  0 41.328 0.084 41.352 ;
    END
  END a[90]
  PIN a[91]
    DIRECTION INPUT ;
    USE SIGNAL ;
    PORT
      LAYER M4 ;
        RECT  0 41.472 0.084 41.496 ;
    END
  END a[91]
  PIN a[92]
    DIRECTION INPUT ;
    USE SIGNAL ;
    PORT
      LAYER M4 ;
        RECT  0 41.616 0.084 41.64 ;
    END
  END a[92]
  PIN a[93]
    DIRECTION INPUT ;
    USE SIGNAL ;
    PORT
      LAYER M4 ;
        RECT  0 41.76 0.084 41.784 ;
    END
  END a[93]
  PIN a[94]
    DIRECTION INPUT ;
    USE SIGNAL ;
    PORT
      LAYER M4 ;
        RECT  0 41.904 0.084 41.928 ;
    END
  END a[94]
  PIN a[95]
    DIRECTION INPUT ;
    USE SIGNAL ;
    PORT
      LAYER M4 ;
        RECT  0 42.048 0.084 42.072 ;
    END
  END a[95]
  PIN a[96]
    DIRECTION INPUT ;
    USE SIGNAL ;
    PORT
      LAYER M4 ;
        RECT  0 28.368 0.084 28.392 ;
    END
  END a[96]
  PIN a[97]
    DIRECTION INPUT ;
    USE SIGNAL ;
    PORT
      LAYER M4 ;
        RECT  0 28.512 0.084 28.536 ;
    END
  END a[97]
  PIN a[98]
    DIRECTION INPUT ;
    USE SIGNAL ;
    PORT
      LAYER M4 ;
        RECT  0 28.656 0.084 28.68 ;
    END
  END a[98]
  PIN a[99]
    DIRECTION INPUT ;
    USE SIGNAL ;
    PORT
      LAYER M4 ;
        RECT  0 28.8 0.084 28.824 ;
    END
  END a[99]
  PIN a[9]
    DIRECTION INPUT ;
    USE SIGNAL ;
    PORT
      LAYER M4 ;
        RECT  0 34.272 0.084 34.296 ;
    END
  END a[9]
  PIN b[0]
    DIRECTION OUTPUT ;
    USE SIGNAL ;
    PORT
      LAYER M4 ;
        RECT  51.756 29.52 51.84 29.544 ;
    END
  END b[0]
  PIN b[100]
    DIRECTION OUTPUT ;
    USE SIGNAL ;
    PORT
      LAYER M4 ;
        RECT  51.756 24.336 51.84 24.36 ;
    END
  END b[100]
  PIN b[101]
    DIRECTION OUTPUT ;
    USE SIGNAL ;
    PORT
      LAYER M4 ;
        RECT  51.756 24.48 51.84 24.504 ;
    END
  END b[101]
  PIN b[102]
    DIRECTION OUTPUT ;
    USE SIGNAL ;
    PORT
      LAYER M4 ;
        RECT  51.756 24.624 51.84 24.648 ;
    END
  END b[102]
  PIN b[103]
    DIRECTION OUTPUT ;
    USE SIGNAL ;
    PORT
      LAYER M4 ;
        RECT  51.756 24.768 51.84 24.792 ;
    END
  END b[103]
  PIN b[104]
    DIRECTION OUTPUT ;
    USE SIGNAL ;
    PORT
      LAYER M4 ;
        RECT  51.756 24.912 51.84 24.936 ;
    END
  END b[104]
  PIN b[105]
    DIRECTION OUTPUT ;
    USE SIGNAL ;
    PORT
      LAYER M4 ;
        RECT  51.756 25.056 51.84 25.08 ;
    END
  END b[105]
  PIN b[106]
    DIRECTION OUTPUT ;
    USE SIGNAL ;
    PORT
      LAYER M4 ;
        RECT  51.756 25.2 51.84 25.224 ;
    END
  END b[106]
  PIN b[107]
    DIRECTION OUTPUT ;
    USE SIGNAL ;
    PORT
      LAYER M4 ;
        RECT  51.756 25.344 51.84 25.368 ;
    END
  END b[107]
  PIN b[108]
    DIRECTION OUTPUT ;
    USE SIGNAL ;
    PORT
      LAYER M4 ;
        RECT  51.756 25.488 51.84 25.512 ;
    END
  END b[108]
  PIN b[109]
    DIRECTION OUTPUT ;
    USE SIGNAL ;
    PORT
      LAYER M4 ;
        RECT  51.756 25.632 51.84 25.656 ;
    END
  END b[109]
  PIN b[10]
    DIRECTION OUTPUT ;
    USE SIGNAL ;
    PORT
      LAYER M4 ;
        RECT  51.756 30.96 51.84 30.984 ;
    END
  END b[10]
  PIN b[110]
    DIRECTION OUTPUT ;
    USE SIGNAL ;
    PORT
      LAYER M4 ;
        RECT  51.756 25.776 51.84 25.8 ;
    END
  END b[110]
  PIN b[111]
    DIRECTION OUTPUT ;
    USE SIGNAL ;
    PORT
      LAYER M4 ;
        RECT  51.756 25.92 51.84 25.944 ;
    END
  END b[111]
  PIN b[112]
    DIRECTION OUTPUT ;
    USE SIGNAL ;
    PORT
      LAYER M4 ;
        RECT  51.756 26.064 51.84 26.088 ;
    END
  END b[112]
  PIN b[113]
    DIRECTION OUTPUT ;
    USE SIGNAL ;
    PORT
      LAYER M4 ;
        RECT  51.756 26.208 51.84 26.232 ;
    END
  END b[113]
  PIN b[114]
    DIRECTION OUTPUT ;
    USE SIGNAL ;
    PORT
      LAYER M4 ;
        RECT  51.756 26.352 51.84 26.376 ;
    END
  END b[114]
  PIN b[115]
    DIRECTION OUTPUT ;
    USE SIGNAL ;
    PORT
      LAYER M4 ;
        RECT  51.756 26.496 51.84 26.52 ;
    END
  END b[115]
  PIN b[116]
    DIRECTION OUTPUT ;
    USE SIGNAL ;
    PORT
      LAYER M4 ;
        RECT  51.756 26.64 51.84 26.664 ;
    END
  END b[116]
  PIN b[117]
    DIRECTION OUTPUT ;
    USE SIGNAL ;
    PORT
      LAYER M4 ;
        RECT  51.756 26.784 51.84 26.808 ;
    END
  END b[117]
  PIN b[118]
    DIRECTION OUTPUT ;
    USE SIGNAL ;
    PORT
      LAYER M4 ;
        RECT  51.756 26.928 51.84 26.952 ;
    END
  END b[118]
  PIN b[119]
    DIRECTION OUTPUT ;
    USE SIGNAL ;
    PORT
      LAYER M4 ;
        RECT  51.756 27.072 51.84 27.096 ;
    END
  END b[119]
  PIN b[11]
    DIRECTION OUTPUT ;
    USE SIGNAL ;
    PORT
      LAYER M4 ;
        RECT  51.756 31.104 51.84 31.128 ;
    END
  END b[11]
  PIN b[120]
    DIRECTION OUTPUT ;
    USE SIGNAL ;
    PORT
      LAYER M4 ;
        RECT  51.756 27.216 51.84 27.24 ;
    END
  END b[120]
  PIN b[121]
    DIRECTION OUTPUT ;
    USE SIGNAL ;
    PORT
      LAYER M4 ;
        RECT  51.756 27.36 51.84 27.384 ;
    END
  END b[121]
  PIN b[122]
    DIRECTION OUTPUT ;
    USE SIGNAL ;
    PORT
      LAYER M4 ;
        RECT  51.756 27.504 51.84 27.528 ;
    END
  END b[122]
  PIN b[123]
    DIRECTION OUTPUT ;
    USE SIGNAL ;
    PORT
      LAYER M4 ;
        RECT  51.756 27.648 51.84 27.672 ;
    END
  END b[123]
  PIN b[124]
    DIRECTION OUTPUT ;
    USE SIGNAL ;
    PORT
      LAYER M4 ;
        RECT  51.756 27.792 51.84 27.816 ;
    END
  END b[124]
  PIN b[125]
    DIRECTION OUTPUT ;
    USE SIGNAL ;
    PORT
      LAYER M4 ;
        RECT  51.756 27.936 51.84 27.96 ;
    END
  END b[125]
  PIN b[126]
    DIRECTION OUTPUT ;
    USE SIGNAL ;
    PORT
      LAYER M4 ;
        RECT  51.756 28.08 51.84 28.104 ;
    END
  END b[126]
  PIN b[127]
    DIRECTION OUTPUT ;
    USE SIGNAL ;
    PORT
      LAYER M4 ;
        RECT  51.756 28.224 51.84 28.248 ;
    END
  END b[127]
  PIN b[128]
    DIRECTION OUTPUT ;
    USE SIGNAL ;
    PORT
      LAYER M4 ;
        RECT  51.756 5.328 51.84 5.352 ;
    END
  END b[128]
  PIN b[129]
    DIRECTION OUTPUT ;
    USE SIGNAL ;
    PORT
      LAYER M4 ;
        RECT  51.756 5.472 51.84 5.496 ;
    END
  END b[129]
  PIN b[12]
    DIRECTION OUTPUT ;
    USE SIGNAL ;
    PORT
      LAYER M4 ;
        RECT  51.756 31.248 51.84 31.272 ;
    END
  END b[12]
  PIN b[130]
    DIRECTION OUTPUT ;
    USE SIGNAL ;
    PORT
      LAYER M4 ;
        RECT  51.756 5.616 51.84 5.64 ;
    END
  END b[130]
  PIN b[131]
    DIRECTION OUTPUT ;
    USE SIGNAL ;
    PORT
      LAYER M4 ;
        RECT  51.756 5.76 51.84 5.784 ;
    END
  END b[131]
  PIN b[132]
    DIRECTION OUTPUT ;
    USE SIGNAL ;
    PORT
      LAYER M4 ;
        RECT  51.756 5.904 51.84 5.928 ;
    END
  END b[132]
  PIN b[133]
    DIRECTION OUTPUT ;
    USE SIGNAL ;
    PORT
      LAYER M4 ;
        RECT  51.756 6.048 51.84 6.072 ;
    END
  END b[133]
  PIN b[134]
    DIRECTION OUTPUT ;
    USE SIGNAL ;
    PORT
      LAYER M4 ;
        RECT  51.756 6.192 51.84 6.216 ;
    END
  END b[134]
  PIN b[135]
    DIRECTION OUTPUT ;
    USE SIGNAL ;
    PORT
      LAYER M4 ;
        RECT  51.756 6.336 51.84 6.36 ;
    END
  END b[135]
  PIN b[136]
    DIRECTION OUTPUT ;
    USE SIGNAL ;
    PORT
      LAYER M4 ;
        RECT  51.756 6.48 51.84 6.504 ;
    END
  END b[136]
  PIN b[137]
    DIRECTION OUTPUT ;
    USE SIGNAL ;
    PORT
      LAYER M4 ;
        RECT  51.756 6.624 51.84 6.648 ;
    END
  END b[137]
  PIN b[138]
    DIRECTION OUTPUT ;
    USE SIGNAL ;
    PORT
      LAYER M4 ;
        RECT  51.756 6.768 51.84 6.792 ;
    END
  END b[138]
  PIN b[139]
    DIRECTION OUTPUT ;
    USE SIGNAL ;
    PORT
      LAYER M4 ;
        RECT  51.756 6.912 51.84 6.936 ;
    END
  END b[139]
  PIN b[13]
    DIRECTION OUTPUT ;
    USE SIGNAL ;
    PORT
      LAYER M4 ;
        RECT  51.756 31.392 51.84 31.416 ;
    END
  END b[13]
  PIN b[140]
    DIRECTION OUTPUT ;
    USE SIGNAL ;
    PORT
      LAYER M4 ;
        RECT  51.756 7.056 51.84 7.08 ;
    END
  END b[140]
  PIN b[141]
    DIRECTION OUTPUT ;
    USE SIGNAL ;
    PORT
      LAYER M4 ;
        RECT  51.756 7.2 51.84 7.224 ;
    END
  END b[141]
  PIN b[142]
    DIRECTION OUTPUT ;
    USE SIGNAL ;
    PORT
      LAYER M4 ;
        RECT  51.756 7.344 51.84 7.368 ;
    END
  END b[142]
  PIN b[143]
    DIRECTION OUTPUT ;
    USE SIGNAL ;
    PORT
      LAYER M4 ;
        RECT  51.756 7.488 51.84 7.512 ;
    END
  END b[143]
  PIN b[144]
    DIRECTION OUTPUT ;
    USE SIGNAL ;
    PORT
      LAYER M4 ;
        RECT  51.756 7.632 51.84 7.656 ;
    END
  END b[144]
  PIN b[145]
    DIRECTION OUTPUT ;
    USE SIGNAL ;
    PORT
      LAYER M4 ;
        RECT  51.756 7.776 51.84 7.8 ;
    END
  END b[145]
  PIN b[146]
    DIRECTION OUTPUT ;
    USE SIGNAL ;
    PORT
      LAYER M4 ;
        RECT  51.756 7.92 51.84 7.944 ;
    END
  END b[146]
  PIN b[147]
    DIRECTION OUTPUT ;
    USE SIGNAL ;
    PORT
      LAYER M4 ;
        RECT  51.756 8.064 51.84 8.088 ;
    END
  END b[147]
  PIN b[148]
    DIRECTION OUTPUT ;
    USE SIGNAL ;
    PORT
      LAYER M4 ;
        RECT  51.756 8.208 51.84 8.232 ;
    END
  END b[148]
  PIN b[149]
    DIRECTION OUTPUT ;
    USE SIGNAL ;
    PORT
      LAYER M4 ;
        RECT  51.756 8.352 51.84 8.376 ;
    END
  END b[149]
  PIN b[14]
    DIRECTION OUTPUT ;
    USE SIGNAL ;
    PORT
      LAYER M4 ;
        RECT  51.756 31.536 51.84 31.56 ;
    END
  END b[14]
  PIN b[150]
    DIRECTION OUTPUT ;
    USE SIGNAL ;
    PORT
      LAYER M4 ;
        RECT  51.756 8.496 51.84 8.52 ;
    END
  END b[150]
  PIN b[151]
    DIRECTION OUTPUT ;
    USE SIGNAL ;
    PORT
      LAYER M4 ;
        RECT  51.756 8.64 51.84 8.664 ;
    END
  END b[151]
  PIN b[152]
    DIRECTION OUTPUT ;
    USE SIGNAL ;
    PORT
      LAYER M4 ;
        RECT  51.756 8.784 51.84 8.808 ;
    END
  END b[152]
  PIN b[153]
    DIRECTION OUTPUT ;
    USE SIGNAL ;
    PORT
      LAYER M4 ;
        RECT  51.756 8.928 51.84 8.952 ;
    END
  END b[153]
  PIN b[154]
    DIRECTION OUTPUT ;
    USE SIGNAL ;
    PORT
      LAYER M4 ;
        RECT  51.756 9.072 51.84 9.096 ;
    END
  END b[154]
  PIN b[155]
    DIRECTION OUTPUT ;
    USE SIGNAL ;
    PORT
      LAYER M4 ;
        RECT  51.756 9.216 51.84 9.24 ;
    END
  END b[155]
  PIN b[156]
    DIRECTION OUTPUT ;
    USE SIGNAL ;
    PORT
      LAYER M4 ;
        RECT  51.756 9.36 51.84 9.384 ;
    END
  END b[156]
  PIN b[157]
    DIRECTION OUTPUT ;
    USE SIGNAL ;
    PORT
      LAYER M4 ;
        RECT  51.756 9.504 51.84 9.528 ;
    END
  END b[157]
  PIN b[158]
    DIRECTION OUTPUT ;
    USE SIGNAL ;
    PORT
      LAYER M4 ;
        RECT  51.756 9.648 51.84 9.672 ;
    END
  END b[158]
  PIN b[159]
    DIRECTION OUTPUT ;
    USE SIGNAL ;
    PORT
      LAYER M4 ;
        RECT  51.756 9.792 51.84 9.816 ;
    END
  END b[159]
  PIN b[15]
    DIRECTION OUTPUT ;
    USE SIGNAL ;
    PORT
      LAYER M4 ;
        RECT  51.756 31.68 51.84 31.704 ;
    END
  END b[15]
  PIN b[160]
    DIRECTION OUTPUT ;
    USE SIGNAL ;
    PORT
      LAYER M4 ;
        RECT  51.756 14.544 51.84 14.568 ;
    END
  END b[160]
  PIN b[161]
    DIRECTION OUTPUT ;
    USE SIGNAL ;
    PORT
      LAYER M4 ;
        RECT  51.756 14.688 51.84 14.712 ;
    END
  END b[161]
  PIN b[162]
    DIRECTION OUTPUT ;
    USE SIGNAL ;
    PORT
      LAYER M4 ;
        RECT  51.756 14.832 51.84 14.856 ;
    END
  END b[162]
  PIN b[163]
    DIRECTION OUTPUT ;
    USE SIGNAL ;
    PORT
      LAYER M4 ;
        RECT  51.756 14.976 51.84 15 ;
    END
  END b[163]
  PIN b[164]
    DIRECTION OUTPUT ;
    USE SIGNAL ;
    PORT
      LAYER M4 ;
        RECT  51.756 15.12 51.84 15.144 ;
    END
  END b[164]
  PIN b[165]
    DIRECTION OUTPUT ;
    USE SIGNAL ;
    PORT
      LAYER M4 ;
        RECT  51.756 15.264 51.84 15.288 ;
    END
  END b[165]
  PIN b[166]
    DIRECTION OUTPUT ;
    USE SIGNAL ;
    PORT
      LAYER M4 ;
        RECT  51.756 15.408 51.84 15.432 ;
    END
  END b[166]
  PIN b[167]
    DIRECTION OUTPUT ;
    USE SIGNAL ;
    PORT
      LAYER M4 ;
        RECT  51.756 15.552 51.84 15.576 ;
    END
  END b[167]
  PIN b[168]
    DIRECTION OUTPUT ;
    USE SIGNAL ;
    PORT
      LAYER M4 ;
        RECT  51.756 15.696 51.84 15.72 ;
    END
  END b[168]
  PIN b[169]
    DIRECTION OUTPUT ;
    USE SIGNAL ;
    PORT
      LAYER M4 ;
        RECT  51.756 15.84 51.84 15.864 ;
    END
  END b[169]
  PIN b[16]
    DIRECTION OUTPUT ;
    USE SIGNAL ;
    PORT
      LAYER M4 ;
        RECT  51.756 31.824 51.84 31.848 ;
    END
  END b[16]
  PIN b[170]
    DIRECTION OUTPUT ;
    USE SIGNAL ;
    PORT
      LAYER M4 ;
        RECT  51.756 15.984 51.84 16.008 ;
    END
  END b[170]
  PIN b[171]
    DIRECTION OUTPUT ;
    USE SIGNAL ;
    PORT
      LAYER M4 ;
        RECT  51.756 16.128 51.84 16.152 ;
    END
  END b[171]
  PIN b[172]
    DIRECTION OUTPUT ;
    USE SIGNAL ;
    PORT
      LAYER M4 ;
        RECT  51.756 16.272 51.84 16.296 ;
    END
  END b[172]
  PIN b[173]
    DIRECTION OUTPUT ;
    USE SIGNAL ;
    PORT
      LAYER M4 ;
        RECT  51.756 16.416 51.84 16.44 ;
    END
  END b[173]
  PIN b[174]
    DIRECTION OUTPUT ;
    USE SIGNAL ;
    PORT
      LAYER M4 ;
        RECT  51.756 16.56 51.84 16.584 ;
    END
  END b[174]
  PIN b[175]
    DIRECTION OUTPUT ;
    USE SIGNAL ;
    PORT
      LAYER M4 ;
        RECT  51.756 16.704 51.84 16.728 ;
    END
  END b[175]
  PIN b[176]
    DIRECTION OUTPUT ;
    USE SIGNAL ;
    PORT
      LAYER M4 ;
        RECT  51.756 16.848 51.84 16.872 ;
    END
  END b[176]
  PIN b[177]
    DIRECTION OUTPUT ;
    USE SIGNAL ;
    PORT
      LAYER M4 ;
        RECT  51.756 16.992 51.84 17.016 ;
    END
  END b[177]
  PIN b[178]
    DIRECTION OUTPUT ;
    USE SIGNAL ;
    PORT
      LAYER M4 ;
        RECT  51.756 17.136 51.84 17.16 ;
    END
  END b[178]
  PIN b[179]
    DIRECTION OUTPUT ;
    USE SIGNAL ;
    PORT
      LAYER M4 ;
        RECT  51.756 17.28 51.84 17.304 ;
    END
  END b[179]
  PIN b[17]
    DIRECTION OUTPUT ;
    USE SIGNAL ;
    PORT
      LAYER M4 ;
        RECT  51.756 31.968 51.84 31.992 ;
    END
  END b[17]
  PIN b[180]
    DIRECTION OUTPUT ;
    USE SIGNAL ;
    PORT
      LAYER M4 ;
        RECT  51.756 17.424 51.84 17.448 ;
    END
  END b[180]
  PIN b[181]
    DIRECTION OUTPUT ;
    USE SIGNAL ;
    PORT
      LAYER M4 ;
        RECT  51.756 17.568 51.84 17.592 ;
    END
  END b[181]
  PIN b[182]
    DIRECTION OUTPUT ;
    USE SIGNAL ;
    PORT
      LAYER M4 ;
        RECT  51.756 17.712 51.84 17.736 ;
    END
  END b[182]
  PIN b[183]
    DIRECTION OUTPUT ;
    USE SIGNAL ;
    PORT
      LAYER M4 ;
        RECT  51.756 17.856 51.84 17.88 ;
    END
  END b[183]
  PIN b[184]
    DIRECTION OUTPUT ;
    USE SIGNAL ;
    PORT
      LAYER M4 ;
        RECT  51.756 18 51.84 18.024 ;
    END
  END b[184]
  PIN b[185]
    DIRECTION OUTPUT ;
    USE SIGNAL ;
    PORT
      LAYER M4 ;
        RECT  51.756 18.144 51.84 18.168 ;
    END
  END b[185]
  PIN b[186]
    DIRECTION OUTPUT ;
    USE SIGNAL ;
    PORT
      LAYER M4 ;
        RECT  51.756 18.288 51.84 18.312 ;
    END
  END b[186]
  PIN b[187]
    DIRECTION OUTPUT ;
    USE SIGNAL ;
    PORT
      LAYER M4 ;
        RECT  51.756 18.432 51.84 18.456 ;
    END
  END b[187]
  PIN b[188]
    DIRECTION OUTPUT ;
    USE SIGNAL ;
    PORT
      LAYER M4 ;
        RECT  51.756 18.576 51.84 18.6 ;
    END
  END b[188]
  PIN b[189]
    DIRECTION OUTPUT ;
    USE SIGNAL ;
    PORT
      LAYER M4 ;
        RECT  51.756 18.72 51.84 18.744 ;
    END
  END b[189]
  PIN b[18]
    DIRECTION OUTPUT ;
    USE SIGNAL ;
    PORT
      LAYER M4 ;
        RECT  51.756 32.112 51.84 32.136 ;
    END
  END b[18]
  PIN b[190]
    DIRECTION OUTPUT ;
    USE SIGNAL ;
    PORT
      LAYER M4 ;
        RECT  51.756 18.864 51.84 18.888 ;
    END
  END b[190]
  PIN b[191]
    DIRECTION OUTPUT ;
    USE SIGNAL ;
    PORT
      LAYER M4 ;
        RECT  51.756 19.008 51.84 19.032 ;
    END
  END b[191]
  PIN b[192]
    DIRECTION OUTPUT ;
    USE SIGNAL ;
    PORT
      LAYER M4 ;
        RECT  51.756 19.152 51.84 19.176 ;
    END
  END b[192]
  PIN b[193]
    DIRECTION OUTPUT ;
    USE SIGNAL ;
    PORT
      LAYER M4 ;
        RECT  51.756 19.296 51.84 19.32 ;
    END
  END b[193]
  PIN b[194]
    DIRECTION OUTPUT ;
    USE SIGNAL ;
    PORT
      LAYER M4 ;
        RECT  51.756 19.44 51.84 19.464 ;
    END
  END b[194]
  PIN b[195]
    DIRECTION OUTPUT ;
    USE SIGNAL ;
    PORT
      LAYER M4 ;
        RECT  51.756 19.584 51.84 19.608 ;
    END
  END b[195]
  PIN b[196]
    DIRECTION OUTPUT ;
    USE SIGNAL ;
    PORT
      LAYER M4 ;
        RECT  51.756 19.728 51.84 19.752 ;
    END
  END b[196]
  PIN b[197]
    DIRECTION OUTPUT ;
    USE SIGNAL ;
    PORT
      LAYER M4 ;
        RECT  51.756 19.872 51.84 19.896 ;
    END
  END b[197]
  PIN b[198]
    DIRECTION OUTPUT ;
    USE SIGNAL ;
    PORT
      LAYER M4 ;
        RECT  51.756 20.016 51.84 20.04 ;
    END
  END b[198]
  PIN b[199]
    DIRECTION OUTPUT ;
    USE SIGNAL ;
    PORT
      LAYER M4 ;
        RECT  51.756 20.16 51.84 20.184 ;
    END
  END b[199]
  PIN b[19]
    DIRECTION OUTPUT ;
    USE SIGNAL ;
    PORT
      LAYER M4 ;
        RECT  51.756 32.256 51.84 32.28 ;
    END
  END b[19]
  PIN b[1]
    DIRECTION OUTPUT ;
    USE SIGNAL ;
    PORT
      LAYER M4 ;
        RECT  51.756 29.664 51.84 29.688 ;
    END
  END b[1]
  PIN b[200]
    DIRECTION OUTPUT ;
    USE SIGNAL ;
    PORT
      LAYER M4 ;
        RECT  51.756 20.304 51.84 20.328 ;
    END
  END b[200]
  PIN b[201]
    DIRECTION OUTPUT ;
    USE SIGNAL ;
    PORT
      LAYER M4 ;
        RECT  51.756 20.448 51.84 20.472 ;
    END
  END b[201]
  PIN b[202]
    DIRECTION OUTPUT ;
    USE SIGNAL ;
    PORT
      LAYER M4 ;
        RECT  51.756 20.592 51.84 20.616 ;
    END
  END b[202]
  PIN b[203]
    DIRECTION OUTPUT ;
    USE SIGNAL ;
    PORT
      LAYER M4 ;
        RECT  51.756 20.736 51.84 20.76 ;
    END
  END b[203]
  PIN b[204]
    DIRECTION OUTPUT ;
    USE SIGNAL ;
    PORT
      LAYER M4 ;
        RECT  51.756 20.88 51.84 20.904 ;
    END
  END b[204]
  PIN b[205]
    DIRECTION OUTPUT ;
    USE SIGNAL ;
    PORT
      LAYER M4 ;
        RECT  51.756 21.024 51.84 21.048 ;
    END
  END b[205]
  PIN b[206]
    DIRECTION OUTPUT ;
    USE SIGNAL ;
    PORT
      LAYER M4 ;
        RECT  51.756 21.168 51.84 21.192 ;
    END
  END b[206]
  PIN b[207]
    DIRECTION OUTPUT ;
    USE SIGNAL ;
    PORT
      LAYER M4 ;
        RECT  51.756 21.312 51.84 21.336 ;
    END
  END b[207]
  PIN b[208]
    DIRECTION OUTPUT ;
    USE SIGNAL ;
    PORT
      LAYER M4 ;
        RECT  51.756 21.456 51.84 21.48 ;
    END
  END b[208]
  PIN b[209]
    DIRECTION OUTPUT ;
    USE SIGNAL ;
    PORT
      LAYER M4 ;
        RECT  51.756 21.6 51.84 21.624 ;
    END
  END b[209]
  PIN b[20]
    DIRECTION OUTPUT ;
    USE SIGNAL ;
    PORT
      LAYER M4 ;
        RECT  51.756 32.4 51.84 32.424 ;
    END
  END b[20]
  PIN b[210]
    DIRECTION OUTPUT ;
    USE SIGNAL ;
    PORT
      LAYER M4 ;
        RECT  51.756 21.744 51.84 21.768 ;
    END
  END b[210]
  PIN b[211]
    DIRECTION OUTPUT ;
    USE SIGNAL ;
    PORT
      LAYER M4 ;
        RECT  51.756 21.888 51.84 21.912 ;
    END
  END b[211]
  PIN b[212]
    DIRECTION OUTPUT ;
    USE SIGNAL ;
    PORT
      LAYER M4 ;
        RECT  51.756 22.032 51.84 22.056 ;
    END
  END b[212]
  PIN b[213]
    DIRECTION OUTPUT ;
    USE SIGNAL ;
    PORT
      LAYER M4 ;
        RECT  51.756 22.176 51.84 22.2 ;
    END
  END b[213]
  PIN b[214]
    DIRECTION OUTPUT ;
    USE SIGNAL ;
    PORT
      LAYER M4 ;
        RECT  51.756 22.32 51.84 22.344 ;
    END
  END b[214]
  PIN b[215]
    DIRECTION OUTPUT ;
    USE SIGNAL ;
    PORT
      LAYER M4 ;
        RECT  51.756 22.464 51.84 22.488 ;
    END
  END b[215]
  PIN b[216]
    DIRECTION OUTPUT ;
    USE SIGNAL ;
    PORT
      LAYER M4 ;
        RECT  51.756 22.608 51.84 22.632 ;
    END
  END b[216]
  PIN b[217]
    DIRECTION OUTPUT ;
    USE SIGNAL ;
    PORT
      LAYER M4 ;
        RECT  51.756 22.752 51.84 22.776 ;
    END
  END b[217]
  PIN b[218]
    DIRECTION OUTPUT ;
    USE SIGNAL ;
    PORT
      LAYER M4 ;
        RECT  51.756 22.896 51.84 22.92 ;
    END
  END b[218]
  PIN b[219]
    DIRECTION OUTPUT ;
    USE SIGNAL ;
    PORT
      LAYER M4 ;
        RECT  51.756 23.04 51.84 23.064 ;
    END
  END b[219]
  PIN b[21]
    DIRECTION OUTPUT ;
    USE SIGNAL ;
    PORT
      LAYER M4 ;
        RECT  51.756 32.544 51.84 32.568 ;
    END
  END b[21]
  PIN b[220]
    DIRECTION OUTPUT ;
    USE SIGNAL ;
    PORT
      LAYER M4 ;
        RECT  51.756 23.184 51.84 23.208 ;
    END
  END b[220]
  PIN b[221]
    DIRECTION OUTPUT ;
    USE SIGNAL ;
    PORT
      LAYER M4 ;
        RECT  51.756 23.328 51.84 23.352 ;
    END
  END b[221]
  PIN b[222]
    DIRECTION OUTPUT ;
    USE SIGNAL ;
    PORT
      LAYER M4 ;
        RECT  51.756 23.472 51.84 23.496 ;
    END
  END b[222]
  PIN b[223]
    DIRECTION OUTPUT ;
    USE SIGNAL ;
    PORT
      LAYER M4 ;
        RECT  51.756 23.616 51.84 23.64 ;
    END
  END b[223]
  PIN b[224]
    DIRECTION OUTPUT ;
    USE SIGNAL ;
    PORT
      LAYER M4 ;
        RECT  51.756 0.72 51.84 0.744 ;
    END
  END b[224]
  PIN b[225]
    DIRECTION OUTPUT ;
    USE SIGNAL ;
    PORT
      LAYER M4 ;
        RECT  51.756 0.864 51.84 0.888 ;
    END
  END b[225]
  PIN b[226]
    DIRECTION OUTPUT ;
    USE SIGNAL ;
    PORT
      LAYER M4 ;
        RECT  51.756 1.008 51.84 1.032 ;
    END
  END b[226]
  PIN b[227]
    DIRECTION OUTPUT ;
    USE SIGNAL ;
    PORT
      LAYER M4 ;
        RECT  51.756 1.152 51.84 1.176 ;
    END
  END b[227]
  PIN b[228]
    DIRECTION OUTPUT ;
    USE SIGNAL ;
    PORT
      LAYER M4 ;
        RECT  51.756 1.296 51.84 1.32 ;
    END
  END b[228]
  PIN b[229]
    DIRECTION OUTPUT ;
    USE SIGNAL ;
    PORT
      LAYER M4 ;
        RECT  51.756 1.44 51.84 1.464 ;
    END
  END b[229]
  PIN b[22]
    DIRECTION OUTPUT ;
    USE SIGNAL ;
    PORT
      LAYER M4 ;
        RECT  51.756 32.688 51.84 32.712 ;
    END
  END b[22]
  PIN b[230]
    DIRECTION OUTPUT ;
    USE SIGNAL ;
    PORT
      LAYER M4 ;
        RECT  51.756 1.584 51.84 1.608 ;
    END
  END b[230]
  PIN b[231]
    DIRECTION OUTPUT ;
    USE SIGNAL ;
    PORT
      LAYER M4 ;
        RECT  51.756 1.728 51.84 1.752 ;
    END
  END b[231]
  PIN b[232]
    DIRECTION OUTPUT ;
    USE SIGNAL ;
    PORT
      LAYER M4 ;
        RECT  51.756 1.872 51.84 1.896 ;
    END
  END b[232]
  PIN b[233]
    DIRECTION OUTPUT ;
    USE SIGNAL ;
    PORT
      LAYER M4 ;
        RECT  51.756 2.016 51.84 2.04 ;
    END
  END b[233]
  PIN b[234]
    DIRECTION OUTPUT ;
    USE SIGNAL ;
    PORT
      LAYER M4 ;
        RECT  51.756 2.16 51.84 2.184 ;
    END
  END b[234]
  PIN b[235]
    DIRECTION OUTPUT ;
    USE SIGNAL ;
    PORT
      LAYER M4 ;
        RECT  51.756 2.304 51.84 2.328 ;
    END
  END b[235]
  PIN b[236]
    DIRECTION OUTPUT ;
    USE SIGNAL ;
    PORT
      LAYER M4 ;
        RECT  51.756 2.448 51.84 2.472 ;
    END
  END b[236]
  PIN b[237]
    DIRECTION OUTPUT ;
    USE SIGNAL ;
    PORT
      LAYER M4 ;
        RECT  51.756 2.592 51.84 2.616 ;
    END
  END b[237]
  PIN b[238]
    DIRECTION OUTPUT ;
    USE SIGNAL ;
    PORT
      LAYER M4 ;
        RECT  51.756 2.736 51.84 2.76 ;
    END
  END b[238]
  PIN b[239]
    DIRECTION OUTPUT ;
    USE SIGNAL ;
    PORT
      LAYER M4 ;
        RECT  51.756 2.88 51.84 2.904 ;
    END
  END b[239]
  PIN b[23]
    DIRECTION OUTPUT ;
    USE SIGNAL ;
    PORT
      LAYER M4 ;
        RECT  51.756 32.832 51.84 32.856 ;
    END
  END b[23]
  PIN b[240]
    DIRECTION OUTPUT ;
    USE SIGNAL ;
    PORT
      LAYER M4 ;
        RECT  51.756 3.024 51.84 3.048 ;
    END
  END b[240]
  PIN b[241]
    DIRECTION OUTPUT ;
    USE SIGNAL ;
    PORT
      LAYER M4 ;
        RECT  51.756 3.168 51.84 3.192 ;
    END
  END b[241]
  PIN b[242]
    DIRECTION OUTPUT ;
    USE SIGNAL ;
    PORT
      LAYER M4 ;
        RECT  51.756 3.312 51.84 3.336 ;
    END
  END b[242]
  PIN b[243]
    DIRECTION OUTPUT ;
    USE SIGNAL ;
    PORT
      LAYER M4 ;
        RECT  51.756 3.456 51.84 3.48 ;
    END
  END b[243]
  PIN b[244]
    DIRECTION OUTPUT ;
    USE SIGNAL ;
    PORT
      LAYER M4 ;
        RECT  51.756 3.6 51.84 3.624 ;
    END
  END b[244]
  PIN b[245]
    DIRECTION OUTPUT ;
    USE SIGNAL ;
    PORT
      LAYER M4 ;
        RECT  51.756 3.744 51.84 3.768 ;
    END
  END b[245]
  PIN b[246]
    DIRECTION OUTPUT ;
    USE SIGNAL ;
    PORT
      LAYER M4 ;
        RECT  51.756 3.888 51.84 3.912 ;
    END
  END b[246]
  PIN b[247]
    DIRECTION OUTPUT ;
    USE SIGNAL ;
    PORT
      LAYER M4 ;
        RECT  51.756 4.032 51.84 4.056 ;
    END
  END b[247]
  PIN b[248]
    DIRECTION OUTPUT ;
    USE SIGNAL ;
    PORT
      LAYER M4 ;
        RECT  51.756 4.176 51.84 4.2 ;
    END
  END b[248]
  PIN b[249]
    DIRECTION OUTPUT ;
    USE SIGNAL ;
    PORT
      LAYER M4 ;
        RECT  51.756 4.32 51.84 4.344 ;
    END
  END b[249]
  PIN b[24]
    DIRECTION OUTPUT ;
    USE SIGNAL ;
    PORT
      LAYER M4 ;
        RECT  51.756 32.976 51.84 33 ;
    END
  END b[24]
  PIN b[250]
    DIRECTION OUTPUT ;
    USE SIGNAL ;
    PORT
      LAYER M4 ;
        RECT  51.756 4.464 51.84 4.488 ;
    END
  END b[250]
  PIN b[251]
    DIRECTION OUTPUT ;
    USE SIGNAL ;
    PORT
      LAYER M4 ;
        RECT  51.756 4.608 51.84 4.632 ;
    END
  END b[251]
  PIN b[252]
    DIRECTION OUTPUT ;
    USE SIGNAL ;
    PORT
      LAYER M4 ;
        RECT  51.756 4.752 51.84 4.776 ;
    END
  END b[252]
  PIN b[253]
    DIRECTION OUTPUT ;
    USE SIGNAL ;
    PORT
      LAYER M4 ;
        RECT  51.756 4.896 51.84 4.92 ;
    END
  END b[253]
  PIN b[254]
    DIRECTION OUTPUT ;
    USE SIGNAL ;
    PORT
      LAYER M4 ;
        RECT  51.756 5.04 51.84 5.064 ;
    END
  END b[254]
  PIN b[255]
    DIRECTION OUTPUT ;
    USE SIGNAL ;
    PORT
      LAYER M4 ;
        RECT  51.756 5.184 51.84 5.208 ;
    END
  END b[255]
  PIN b[256]
    DIRECTION OUTPUT ;
    USE SIGNAL ;
    PORT
      LAYER M4 ;
        RECT  51.756 9.936 51.84 9.96 ;
    END
  END b[256]
  PIN b[257]
    DIRECTION OUTPUT ;
    USE SIGNAL ;
    PORT
      LAYER M4 ;
        RECT  51.756 10.08 51.84 10.104 ;
    END
  END b[257]
  PIN b[258]
    DIRECTION OUTPUT ;
    USE SIGNAL ;
    PORT
      LAYER M4 ;
        RECT  51.756 10.224 51.84 10.248 ;
    END
  END b[258]
  PIN b[259]
    DIRECTION OUTPUT ;
    USE SIGNAL ;
    PORT
      LAYER M4 ;
        RECT  51.756 10.368 51.84 10.392 ;
    END
  END b[259]
  PIN b[25]
    DIRECTION OUTPUT ;
    USE SIGNAL ;
    PORT
      LAYER M4 ;
        RECT  51.756 33.12 51.84 33.144 ;
    END
  END b[25]
  PIN b[260]
    DIRECTION OUTPUT ;
    USE SIGNAL ;
    PORT
      LAYER M4 ;
        RECT  51.756 10.512 51.84 10.536 ;
    END
  END b[260]
  PIN b[261]
    DIRECTION OUTPUT ;
    USE SIGNAL ;
    PORT
      LAYER M4 ;
        RECT  51.756 10.656 51.84 10.68 ;
    END
  END b[261]
  PIN b[262]
    DIRECTION OUTPUT ;
    USE SIGNAL ;
    PORT
      LAYER M4 ;
        RECT  51.756 10.8 51.84 10.824 ;
    END
  END b[262]
  PIN b[263]
    DIRECTION OUTPUT ;
    USE SIGNAL ;
    PORT
      LAYER M4 ;
        RECT  51.756 10.944 51.84 10.968 ;
    END
  END b[263]
  PIN b[264]
    DIRECTION OUTPUT ;
    USE SIGNAL ;
    PORT
      LAYER M4 ;
        RECT  51.756 11.088 51.84 11.112 ;
    END
  END b[264]
  PIN b[265]
    DIRECTION OUTPUT ;
    USE SIGNAL ;
    PORT
      LAYER M4 ;
        RECT  51.756 11.232 51.84 11.256 ;
    END
  END b[265]
  PIN b[266]
    DIRECTION OUTPUT ;
    USE SIGNAL ;
    PORT
      LAYER M4 ;
        RECT  51.756 11.376 51.84 11.4 ;
    END
  END b[266]
  PIN b[267]
    DIRECTION OUTPUT ;
    USE SIGNAL ;
    PORT
      LAYER M4 ;
        RECT  51.756 11.52 51.84 11.544 ;
    END
  END b[267]
  PIN b[268]
    DIRECTION OUTPUT ;
    USE SIGNAL ;
    PORT
      LAYER M4 ;
        RECT  51.756 11.664 51.84 11.688 ;
    END
  END b[268]
  PIN b[269]
    DIRECTION OUTPUT ;
    USE SIGNAL ;
    PORT
      LAYER M4 ;
        RECT  51.756 11.808 51.84 11.832 ;
    END
  END b[269]
  PIN b[26]
    DIRECTION OUTPUT ;
    USE SIGNAL ;
    PORT
      LAYER M4 ;
        RECT  51.756 33.264 51.84 33.288 ;
    END
  END b[26]
  PIN b[270]
    DIRECTION OUTPUT ;
    USE SIGNAL ;
    PORT
      LAYER M4 ;
        RECT  51.756 11.952 51.84 11.976 ;
    END
  END b[270]
  PIN b[271]
    DIRECTION OUTPUT ;
    USE SIGNAL ;
    PORT
      LAYER M4 ;
        RECT  51.756 12.096 51.84 12.12 ;
    END
  END b[271]
  PIN b[272]
    DIRECTION OUTPUT ;
    USE SIGNAL ;
    PORT
      LAYER M4 ;
        RECT  51.756 12.24 51.84 12.264 ;
    END
  END b[272]
  PIN b[273]
    DIRECTION OUTPUT ;
    USE SIGNAL ;
    PORT
      LAYER M4 ;
        RECT  51.756 12.384 51.84 12.408 ;
    END
  END b[273]
  PIN b[274]
    DIRECTION OUTPUT ;
    USE SIGNAL ;
    PORT
      LAYER M4 ;
        RECT  51.756 12.528 51.84 12.552 ;
    END
  END b[274]
  PIN b[275]
    DIRECTION OUTPUT ;
    USE SIGNAL ;
    PORT
      LAYER M4 ;
        RECT  51.756 12.672 51.84 12.696 ;
    END
  END b[275]
  PIN b[276]
    DIRECTION OUTPUT ;
    USE SIGNAL ;
    PORT
      LAYER M4 ;
        RECT  51.756 12.816 51.84 12.84 ;
    END
  END b[276]
  PIN b[277]
    DIRECTION OUTPUT ;
    USE SIGNAL ;
    PORT
      LAYER M4 ;
        RECT  51.756 12.96 51.84 12.984 ;
    END
  END b[277]
  PIN b[278]
    DIRECTION OUTPUT ;
    USE SIGNAL ;
    PORT
      LAYER M4 ;
        RECT  51.756 13.104 51.84 13.128 ;
    END
  END b[278]
  PIN b[279]
    DIRECTION OUTPUT ;
    USE SIGNAL ;
    PORT
      LAYER M4 ;
        RECT  51.756 13.248 51.84 13.272 ;
    END
  END b[279]
  PIN b[27]
    DIRECTION OUTPUT ;
    USE SIGNAL ;
    PORT
      LAYER M4 ;
        RECT  51.756 33.408 51.84 33.432 ;
    END
  END b[27]
  PIN b[280]
    DIRECTION OUTPUT ;
    USE SIGNAL ;
    PORT
      LAYER M4 ;
        RECT  51.756 13.392 51.84 13.416 ;
    END
  END b[280]
  PIN b[281]
    DIRECTION OUTPUT ;
    USE SIGNAL ;
    PORT
      LAYER M4 ;
        RECT  51.756 13.536 51.84 13.56 ;
    END
  END b[281]
  PIN b[282]
    DIRECTION OUTPUT ;
    USE SIGNAL ;
    PORT
      LAYER M4 ;
        RECT  51.756 13.68 51.84 13.704 ;
    END
  END b[282]
  PIN b[283]
    DIRECTION OUTPUT ;
    USE SIGNAL ;
    PORT
      LAYER M4 ;
        RECT  51.756 13.824 51.84 13.848 ;
    END
  END b[283]
  PIN b[284]
    DIRECTION OUTPUT ;
    USE SIGNAL ;
    PORT
      LAYER M4 ;
        RECT  51.756 13.968 51.84 13.992 ;
    END
  END b[284]
  PIN b[285]
    DIRECTION OUTPUT ;
    USE SIGNAL ;
    PORT
      LAYER M4 ;
        RECT  51.756 14.112 51.84 14.136 ;
    END
  END b[285]
  PIN b[286]
    DIRECTION OUTPUT ;
    USE SIGNAL ;
    PORT
      LAYER M4 ;
        RECT  51.756 14.256 51.84 14.28 ;
    END
  END b[286]
  PIN b[287]
    DIRECTION OUTPUT ;
    USE SIGNAL ;
    PORT
      LAYER M4 ;
        RECT  51.756 14.4 51.84 14.424 ;
    END
  END b[287]
  PIN b[288]
    DIRECTION OUTPUT ;
    USE SIGNAL ;
    PORT
      LAYER M4 ;
        RECT  51.756 28.368 51.84 28.392 ;
    END
  END b[288]
  PIN b[289]
    DIRECTION OUTPUT ;
    USE SIGNAL ;
    PORT
      LAYER M4 ;
        RECT  51.756 28.512 51.84 28.536 ;
    END
  END b[289]
  PIN b[28]
    DIRECTION OUTPUT ;
    USE SIGNAL ;
    PORT
      LAYER M4 ;
        RECT  51.756 33.552 51.84 33.576 ;
    END
  END b[28]
  PIN b[290]
    DIRECTION OUTPUT ;
    USE SIGNAL ;
    PORT
      LAYER M4 ;
        RECT  51.756 28.656 51.84 28.68 ;
    END
  END b[290]
  PIN b[291]
    DIRECTION OUTPUT ;
    USE SIGNAL ;
    PORT
      LAYER M4 ;
        RECT  51.756 28.8 51.84 28.824 ;
    END
  END b[291]
  PIN b[292]
    DIRECTION OUTPUT ;
    USE SIGNAL ;
    PORT
      LAYER M4 ;
        RECT  51.756 28.944 51.84 28.968 ;
    END
  END b[292]
  PIN b[293]
    DIRECTION OUTPUT ;
    USE SIGNAL ;
    PORT
      LAYER M4 ;
        RECT  51.756 29.088 51.84 29.112 ;
    END
  END b[293]
  PIN b[294]
    DIRECTION OUTPUT ;
    USE SIGNAL ;
    PORT
      LAYER M4 ;
        RECT  51.756 29.232 51.84 29.256 ;
    END
  END b[294]
  PIN b[295]
    DIRECTION OUTPUT ;
    USE SIGNAL ;
    PORT
      LAYER M4 ;
        RECT  51.756 29.376 51.84 29.4 ;
    END
  END b[295]
  PIN b[29]
    DIRECTION OUTPUT ;
    USE SIGNAL ;
    PORT
      LAYER M4 ;
        RECT  51.756 33.696 51.84 33.72 ;
    END
  END b[29]
  PIN b[2]
    DIRECTION OUTPUT ;
    USE SIGNAL ;
    PORT
      LAYER M4 ;
        RECT  51.756 29.808 51.84 29.832 ;
    END
  END b[2]
  PIN b[30]
    DIRECTION OUTPUT ;
    USE SIGNAL ;
    PORT
      LAYER M4 ;
        RECT  51.756 33.84 51.84 33.864 ;
    END
  END b[30]
  PIN b[31]
    DIRECTION OUTPUT ;
    USE SIGNAL ;
    PORT
      LAYER M4 ;
        RECT  51.756 33.984 51.84 34.008 ;
    END
  END b[31]
  PIN b[32]
    DIRECTION OUTPUT ;
    USE SIGNAL ;
    PORT
      LAYER M4 ;
        RECT  51.756 38.736 51.84 38.76 ;
    END
  END b[32]
  PIN b[33]
    DIRECTION OUTPUT ;
    USE SIGNAL ;
    PORT
      LAYER M4 ;
        RECT  51.756 38.88 51.84 38.904 ;
    END
  END b[33]
  PIN b[34]
    DIRECTION OUTPUT ;
    USE SIGNAL ;
    PORT
      LAYER M4 ;
        RECT  51.756 39.024 51.84 39.048 ;
    END
  END b[34]
  PIN b[35]
    DIRECTION OUTPUT ;
    USE SIGNAL ;
    PORT
      LAYER M4 ;
        RECT  51.756 39.168 51.84 39.192 ;
    END
  END b[35]
  PIN b[36]
    DIRECTION OUTPUT ;
    USE SIGNAL ;
    PORT
      LAYER M4 ;
        RECT  51.756 39.312 51.84 39.336 ;
    END
  END b[36]
  PIN b[37]
    DIRECTION OUTPUT ;
    USE SIGNAL ;
    PORT
      LAYER M4 ;
        RECT  51.756 39.456 51.84 39.48 ;
    END
  END b[37]
  PIN b[38]
    DIRECTION OUTPUT ;
    USE SIGNAL ;
    PORT
      LAYER M4 ;
        RECT  51.756 39.6 51.84 39.624 ;
    END
  END b[38]
  PIN b[39]
    DIRECTION OUTPUT ;
    USE SIGNAL ;
    PORT
      LAYER M4 ;
        RECT  51.756 39.744 51.84 39.768 ;
    END
  END b[39]
  PIN b[3]
    DIRECTION OUTPUT ;
    USE SIGNAL ;
    PORT
      LAYER M4 ;
        RECT  51.756 29.952 51.84 29.976 ;
    END
  END b[3]
  PIN b[40]
    DIRECTION OUTPUT ;
    USE SIGNAL ;
    PORT
      LAYER M4 ;
        RECT  51.756 39.888 51.84 39.912 ;
    END
  END b[40]
  PIN b[41]
    DIRECTION OUTPUT ;
    USE SIGNAL ;
    PORT
      LAYER M4 ;
        RECT  51.756 40.032 51.84 40.056 ;
    END
  END b[41]
  PIN b[42]
    DIRECTION OUTPUT ;
    USE SIGNAL ;
    PORT
      LAYER M4 ;
        RECT  51.756 40.176 51.84 40.2 ;
    END
  END b[42]
  PIN b[43]
    DIRECTION OUTPUT ;
    USE SIGNAL ;
    PORT
      LAYER M4 ;
        RECT  51.756 40.32 51.84 40.344 ;
    END
  END b[43]
  PIN b[44]
    DIRECTION OUTPUT ;
    USE SIGNAL ;
    PORT
      LAYER M4 ;
        RECT  51.756 40.464 51.84 40.488 ;
    END
  END b[44]
  PIN b[45]
    DIRECTION OUTPUT ;
    USE SIGNAL ;
    PORT
      LAYER M4 ;
        RECT  51.756 40.608 51.84 40.632 ;
    END
  END b[45]
  PIN b[46]
    DIRECTION OUTPUT ;
    USE SIGNAL ;
    PORT
      LAYER M4 ;
        RECT  51.756 40.752 51.84 40.776 ;
    END
  END b[46]
  PIN b[47]
    DIRECTION OUTPUT ;
    USE SIGNAL ;
    PORT
      LAYER M4 ;
        RECT  51.756 40.896 51.84 40.92 ;
    END
  END b[47]
  PIN b[48]
    DIRECTION OUTPUT ;
    USE SIGNAL ;
    PORT
      LAYER M4 ;
        RECT  51.756 41.04 51.84 41.064 ;
    END
  END b[48]
  PIN b[49]
    DIRECTION OUTPUT ;
    USE SIGNAL ;
    PORT
      LAYER M4 ;
        RECT  51.756 41.184 51.84 41.208 ;
    END
  END b[49]
  PIN b[4]
    DIRECTION OUTPUT ;
    USE SIGNAL ;
    PORT
      LAYER M4 ;
        RECT  51.756 30.096 51.84 30.12 ;
    END
  END b[4]
  PIN b[50]
    DIRECTION OUTPUT ;
    USE SIGNAL ;
    PORT
      LAYER M4 ;
        RECT  51.756 41.328 51.84 41.352 ;
    END
  END b[50]
  PIN b[51]
    DIRECTION OUTPUT ;
    USE SIGNAL ;
    PORT
      LAYER M4 ;
        RECT  51.756 41.472 51.84 41.496 ;
    END
  END b[51]
  PIN b[52]
    DIRECTION OUTPUT ;
    USE SIGNAL ;
    PORT
      LAYER M4 ;
        RECT  51.756 41.616 51.84 41.64 ;
    END
  END b[52]
  PIN b[53]
    DIRECTION OUTPUT ;
    USE SIGNAL ;
    PORT
      LAYER M4 ;
        RECT  51.756 41.76 51.84 41.784 ;
    END
  END b[53]
  PIN b[54]
    DIRECTION OUTPUT ;
    USE SIGNAL ;
    PORT
      LAYER M4 ;
        RECT  51.756 41.904 51.84 41.928 ;
    END
  END b[54]
  PIN b[55]
    DIRECTION OUTPUT ;
    USE SIGNAL ;
    PORT
      LAYER M4 ;
        RECT  51.756 42.048 51.84 42.072 ;
    END
  END b[55]
  PIN b[56]
    DIRECTION OUTPUT ;
    USE SIGNAL ;
    PORT
      LAYER M4 ;
        RECT  51.756 42.192 51.84 42.216 ;
    END
  END b[56]
  PIN b[57]
    DIRECTION OUTPUT ;
    USE SIGNAL ;
    PORT
      LAYER M4 ;
        RECT  51.756 42.336 51.84 42.36 ;
    END
  END b[57]
  PIN b[58]
    DIRECTION OUTPUT ;
    USE SIGNAL ;
    PORT
      LAYER M4 ;
        RECT  51.756 42.48 51.84 42.504 ;
    END
  END b[58]
  PIN b[59]
    DIRECTION OUTPUT ;
    USE SIGNAL ;
    PORT
      LAYER M4 ;
        RECT  51.756 42.624 51.84 42.648 ;
    END
  END b[59]
  PIN b[5]
    DIRECTION OUTPUT ;
    USE SIGNAL ;
    PORT
      LAYER M4 ;
        RECT  51.756 30.24 51.84 30.264 ;
    END
  END b[5]
  PIN b[60]
    DIRECTION OUTPUT ;
    USE SIGNAL ;
    PORT
      LAYER M4 ;
        RECT  51.756 42.768 51.84 42.792 ;
    END
  END b[60]
  PIN b[61]
    DIRECTION OUTPUT ;
    USE SIGNAL ;
    PORT
      LAYER M4 ;
        RECT  51.756 42.912 51.84 42.936 ;
    END
  END b[61]
  PIN b[62]
    DIRECTION OUTPUT ;
    USE SIGNAL ;
    PORT
      LAYER M4 ;
        RECT  51.756 43.056 51.84 43.08 ;
    END
  END b[62]
  PIN b[63]
    DIRECTION OUTPUT ;
    USE SIGNAL ;
    PORT
      LAYER M4 ;
        RECT  51.756 43.2 51.84 43.224 ;
    END
  END b[63]
  PIN b[64]
    DIRECTION OUTPUT ;
    USE SIGNAL ;
    PORT
      LAYER M4 ;
        RECT  51.756 34.128 51.84 34.152 ;
    END
  END b[64]
  PIN b[65]
    DIRECTION OUTPUT ;
    USE SIGNAL ;
    PORT
      LAYER M4 ;
        RECT  51.756 34.272 51.84 34.296 ;
    END
  END b[65]
  PIN b[66]
    DIRECTION OUTPUT ;
    USE SIGNAL ;
    PORT
      LAYER M4 ;
        RECT  51.756 34.416 51.84 34.44 ;
    END
  END b[66]
  PIN b[67]
    DIRECTION OUTPUT ;
    USE SIGNAL ;
    PORT
      LAYER M4 ;
        RECT  51.756 34.56 51.84 34.584 ;
    END
  END b[67]
  PIN b[68]
    DIRECTION OUTPUT ;
    USE SIGNAL ;
    PORT
      LAYER M4 ;
        RECT  51.756 34.704 51.84 34.728 ;
    END
  END b[68]
  PIN b[69]
    DIRECTION OUTPUT ;
    USE SIGNAL ;
    PORT
      LAYER M4 ;
        RECT  51.756 34.848 51.84 34.872 ;
    END
  END b[69]
  PIN b[6]
    DIRECTION OUTPUT ;
    USE SIGNAL ;
    PORT
      LAYER M4 ;
        RECT  51.756 30.384 51.84 30.408 ;
    END
  END b[6]
  PIN b[70]
    DIRECTION OUTPUT ;
    USE SIGNAL ;
    PORT
      LAYER M4 ;
        RECT  51.756 34.992 51.84 35.016 ;
    END
  END b[70]
  PIN b[71]
    DIRECTION OUTPUT ;
    USE SIGNAL ;
    PORT
      LAYER M4 ;
        RECT  51.756 35.136 51.84 35.16 ;
    END
  END b[71]
  PIN b[72]
    DIRECTION OUTPUT ;
    USE SIGNAL ;
    PORT
      LAYER M4 ;
        RECT  51.756 35.28 51.84 35.304 ;
    END
  END b[72]
  PIN b[73]
    DIRECTION OUTPUT ;
    USE SIGNAL ;
    PORT
      LAYER M4 ;
        RECT  51.756 35.424 51.84 35.448 ;
    END
  END b[73]
  PIN b[74]
    DIRECTION OUTPUT ;
    USE SIGNAL ;
    PORT
      LAYER M4 ;
        RECT  51.756 35.568 51.84 35.592 ;
    END
  END b[74]
  PIN b[75]
    DIRECTION OUTPUT ;
    USE SIGNAL ;
    PORT
      LAYER M4 ;
        RECT  51.756 35.712 51.84 35.736 ;
    END
  END b[75]
  PIN b[76]
    DIRECTION OUTPUT ;
    USE SIGNAL ;
    PORT
      LAYER M4 ;
        RECT  51.756 35.856 51.84 35.88 ;
    END
  END b[76]
  PIN b[77]
    DIRECTION OUTPUT ;
    USE SIGNAL ;
    PORT
      LAYER M4 ;
        RECT  51.756 36 51.84 36.024 ;
    END
  END b[77]
  PIN b[78]
    DIRECTION OUTPUT ;
    USE SIGNAL ;
    PORT
      LAYER M4 ;
        RECT  51.756 36.144 51.84 36.168 ;
    END
  END b[78]
  PIN b[79]
    DIRECTION OUTPUT ;
    USE SIGNAL ;
    PORT
      LAYER M4 ;
        RECT  51.756 36.288 51.84 36.312 ;
    END
  END b[79]
  PIN b[7]
    DIRECTION OUTPUT ;
    USE SIGNAL ;
    PORT
      LAYER M4 ;
        RECT  51.756 30.528 51.84 30.552 ;
    END
  END b[7]
  PIN b[80]
    DIRECTION OUTPUT ;
    USE SIGNAL ;
    PORT
      LAYER M4 ;
        RECT  51.756 36.432 51.84 36.456 ;
    END
  END b[80]
  PIN b[81]
    DIRECTION OUTPUT ;
    USE SIGNAL ;
    PORT
      LAYER M4 ;
        RECT  51.756 36.576 51.84 36.6 ;
    END
  END b[81]
  PIN b[82]
    DIRECTION OUTPUT ;
    USE SIGNAL ;
    PORT
      LAYER M4 ;
        RECT  51.756 36.72 51.84 36.744 ;
    END
  END b[82]
  PIN b[83]
    DIRECTION OUTPUT ;
    USE SIGNAL ;
    PORT
      LAYER M4 ;
        RECT  51.756 36.864 51.84 36.888 ;
    END
  END b[83]
  PIN b[84]
    DIRECTION OUTPUT ;
    USE SIGNAL ;
    PORT
      LAYER M4 ;
        RECT  51.756 37.008 51.84 37.032 ;
    END
  END b[84]
  PIN b[85]
    DIRECTION OUTPUT ;
    USE SIGNAL ;
    PORT
      LAYER M4 ;
        RECT  51.756 37.152 51.84 37.176 ;
    END
  END b[85]
  PIN b[86]
    DIRECTION OUTPUT ;
    USE SIGNAL ;
    PORT
      LAYER M4 ;
        RECT  51.756 37.296 51.84 37.32 ;
    END
  END b[86]
  PIN b[87]
    DIRECTION OUTPUT ;
    USE SIGNAL ;
    PORT
      LAYER M4 ;
        RECT  51.756 37.44 51.84 37.464 ;
    END
  END b[87]
  PIN b[88]
    DIRECTION OUTPUT ;
    USE SIGNAL ;
    PORT
      LAYER M4 ;
        RECT  51.756 37.584 51.84 37.608 ;
    END
  END b[88]
  PIN b[89]
    DIRECTION OUTPUT ;
    USE SIGNAL ;
    PORT
      LAYER M4 ;
        RECT  51.756 37.728 51.84 37.752 ;
    END
  END b[89]
  PIN b[8]
    DIRECTION OUTPUT ;
    USE SIGNAL ;
    PORT
      LAYER M4 ;
        RECT  51.756 30.672 51.84 30.696 ;
    END
  END b[8]
  PIN b[90]
    DIRECTION OUTPUT ;
    USE SIGNAL ;
    PORT
      LAYER M4 ;
        RECT  51.756 37.872 51.84 37.896 ;
    END
  END b[90]
  PIN b[91]
    DIRECTION OUTPUT ;
    USE SIGNAL ;
    PORT
      LAYER M4 ;
        RECT  51.756 38.016 51.84 38.04 ;
    END
  END b[91]
  PIN b[92]
    DIRECTION OUTPUT ;
    USE SIGNAL ;
    PORT
      LAYER M4 ;
        RECT  51.756 38.16 51.84 38.184 ;
    END
  END b[92]
  PIN b[93]
    DIRECTION OUTPUT ;
    USE SIGNAL ;
    PORT
      LAYER M4 ;
        RECT  51.756 38.304 51.84 38.328 ;
    END
  END b[93]
  PIN b[94]
    DIRECTION OUTPUT ;
    USE SIGNAL ;
    PORT
      LAYER M4 ;
        RECT  51.756 38.448 51.84 38.472 ;
    END
  END b[94]
  PIN b[95]
    DIRECTION OUTPUT ;
    USE SIGNAL ;
    PORT
      LAYER M4 ;
        RECT  51.756 38.592 51.84 38.616 ;
    END
  END b[95]
  PIN b[96]
    DIRECTION OUTPUT ;
    USE SIGNAL ;
    PORT
      LAYER M4 ;
        RECT  51.756 23.76 51.84 23.784 ;
    END
  END b[96]
  PIN b[97]
    DIRECTION OUTPUT ;
    USE SIGNAL ;
    PORT
      LAYER M4 ;
        RECT  51.756 23.904 51.84 23.928 ;
    END
  END b[97]
  PIN b[98]
    DIRECTION OUTPUT ;
    USE SIGNAL ;
    PORT
      LAYER M4 ;
        RECT  51.756 24.048 51.84 24.072 ;
    END
  END b[98]
  PIN b[99]
    DIRECTION OUTPUT ;
    USE SIGNAL ;
    PORT
      LAYER M4 ;
        RECT  51.756 24.192 51.84 24.216 ;
    END
  END b[99]
  PIN b[9]
    DIRECTION OUTPUT ;
    USE SIGNAL ;
    PORT
      LAYER M4 ;
        RECT  51.756 30.816 51.84 30.84 ;
    END
  END b[9]
  PIN ck
    DIRECTION INPUT ;
    USE SIGNAL ;
    PORT
      LAYER M5 ;
        RECT  18.864 0 18.888 0.084 ;
    END
  END ck
  PIN ck_s
    DIRECTION INPUT ;
    USE SIGNAL ;
    PORT
      LAYER M5 ;
        RECT  19.008 0 19.032 0.084 ;
    END
  END ck_s
  PIN en
    DIRECTION INPUT ;
    USE SIGNAL ;
    PORT
      LAYER M5 ;
        RECT  19.152 0 19.176 0.084 ;
    END
  END en
  PIN fault
    DIRECTION OUTPUT ;
    USE SIGNAL ;
    PORT
      LAYER M3 ;
        RECT  16.416 47.483 16.434 47.52 ;
    END
  END fault
  PIN k0
    DIRECTION INPUT ;
    USE SIGNAL ;
    PORT
      LAYER M5 ;
        RECT  19.296 0 19.32 0.084 ;
    END
  END k0
  PIN k1
    DIRECTION INPUT ;
    USE SIGNAL ;
    PORT
      LAYER M5 ;
        RECT  19.44 0 19.464 0.084 ;
    END
  END k1
  PIN k2
    DIRECTION INPUT ;
    USE SIGNAL ;
    PORT
      LAYER M5 ;
        RECT  19.584 0 19.608 0.084 ;
    END
  END k2
  PIN rs
    DIRECTION INPUT ;
    USE SIGNAL ;
    PORT
      LAYER M5 ;
        RECT  19.728 0 19.752 0.084 ;
    END
  END rs
  PIN tie_hi
    DIRECTION OUTPUT ;
    USE SIGNAL ;
    PORT
      LAYER M3 ;
        RECT  16.524 47.483 16.542 47.52 ;
    END
  END tie_hi
  PIN tie_lo
    DIRECTION OUTPUT ;
    USE SIGNAL ;
    PORT
      LAYER M3 ;
        RECT  16.632 47.483 16.65 47.52 ;
    END
  END tie_lo
  PIN VDD
    DIRECTION INOUT ;
    USE POWER ;
    PORT
      LAYER M5 ;
        RECT  48.492 2.151 48.612 45.369 ;
        RECT  45.792 2.151 45.912 45.369 ;
        RECT  43.092 2.151 43.212 45.369 ;
        RECT  40.392 2.151 40.512 45.369 ;
        RECT  37.692 2.151 37.812 45.369 ;
        RECT  34.992 2.151 35.112 45.369 ;
        RECT  32.292 2.151 32.412 45.369 ;
        RECT  29.592 2.151 29.712 45.369 ;
        RECT  26.892 2.151 27.012 45.369 ;
        RECT  24.192 2.151 24.312 45.369 ;
        RECT  21.492 2.151 21.612 45.369 ;
        RECT  18.792 2.151 18.912 45.369 ;
        RECT  16.092 2.151 16.212 45.369 ;
        RECT  13.392 2.151 13.512 45.369 ;
        RECT  10.692 2.151 10.812 45.369 ;
        RECT  7.992 2.151 8.112 45.369 ;
        RECT  5.292 2.151 5.412 45.369 ;
        RECT  2.592 2.151 2.712 45.369 ;
    END
  END VDD
  PIN VSS
    DIRECTION INOUT ;
    USE GROUND ;
    PORT
      LAYER M5 ;
        RECT  48.3 2.137 48.42 45.383 ;
        RECT  45.6 2.137 45.72 45.383 ;
        RECT  42.9 2.137 43.02 45.383 ;
        RECT  40.2 2.137 40.32 45.383 ;
        RECT  37.5 2.137 37.62 45.383 ;
        RECT  34.8 2.137 34.92 45.383 ;
        RECT  32.1 2.137 32.22 45.383 ;
        RECT  29.4 2.137 29.52 45.383 ;
        RECT  26.7 2.137 26.82 45.383 ;
        RECT  24 2.137 24.12 45.383 ;
        RECT  21.3 2.137 21.42 45.383 ;
        RECT  18.6 2.137 18.72 45.383 ;
        RECT  15.9 2.137 16.02 45.383 ;
        RECT  13.2 2.137 13.32 45.383 ;
        RECT  10.5 2.137 10.62 45.383 ;
        RECT  7.8 2.137 7.92 45.383 ;
        RECT  5.1 2.137 5.22 45.383 ;
        RECT  2.4 2.137 2.52 45.383 ;
    END
  END VSS
  # OT_OBS_CLOSED layer=M5 d_um=1.536 added=246
  OBS
    LAYER RVTN ;
     RECT  2.16 2.16 49.68 2.295 ;
     RECT  2.16 2.565 49.68 2.835 ;
     RECT  2.16 3.105 49.68 3.375 ;
     RECT  2.16 3.645 49.68 3.915 ;
     RECT  2.16 4.185 49.68 4.455 ;
     RECT  2.16 4.725 49.68 4.995 ;
     RECT  2.16 5.265 49.68 5.535 ;
     RECT  2.16 5.805 49.68 6.075 ;
     RECT  2.16 6.345 49.68 6.615 ;
     RECT  2.16 6.885 49.68 7.155 ;
     RECT  2.16 7.425 49.68 7.695 ;
     RECT  2.16 7.965 49.68 8.235 ;
     RECT  2.16 8.505 49.68 8.775 ;
     RECT  2.16 9.045 49.68 9.315 ;
     RECT  2.16 9.585 49.68 9.855 ;
     RECT  2.16 10.125 49.68 10.395 ;
     RECT  2.16 10.665 49.68 10.935 ;
     RECT  2.16 11.205 49.68 11.475 ;
     RECT  2.16 11.745 49.68 12.015 ;
     RECT  2.16 12.285 49.68 12.555 ;
     RECT  2.16 12.825 49.68 13.095 ;
     RECT  2.16 13.365 49.68 13.635 ;
     RECT  2.16 13.905 49.68 14.175 ;
     RECT  2.16 14.445 49.68 14.715 ;
     RECT  2.16 14.985 49.68 15.255 ;
     RECT  2.16 15.525 49.68 15.795 ;
     RECT  2.16 16.065 49.68 16.335 ;
     RECT  2.16 16.605 49.68 16.875 ;
     RECT  2.16 17.145 49.68 17.415 ;
     RECT  2.16 17.685 49.68 17.955 ;
     RECT  2.16 18.225 49.68 18.495 ;
     RECT  2.16 18.765 49.68 19.035 ;
     RECT  2.16 19.305 49.68 19.575 ;
     RECT  2.16 19.845 49.68 20.115 ;
     RECT  2.16 20.385 49.68 20.655 ;
     RECT  2.16 20.925 49.68 21.195 ;
     RECT  2.16 21.465 49.68 21.735 ;
     RECT  2.16 22.005 49.68 22.275 ;
     RECT  2.16 22.545 49.68 22.815 ;
     RECT  2.16 23.085 49.68 23.355 ;
     RECT  2.16 23.625 49.68 23.895 ;
     RECT  2.16 24.165 49.68 24.435 ;
     RECT  2.16 24.705 49.68 24.975 ;
     RECT  2.16 25.245 49.68 25.515 ;
     RECT  2.16 25.785 49.68 26.055 ;
     RECT  2.16 26.325 49.68 26.595 ;
     RECT  2.16 26.865 49.68 27.135 ;
     RECT  2.16 27.405 49.68 27.675 ;
     RECT  2.16 27.945 49.68 28.215 ;
     RECT  2.16 28.485 49.68 28.755 ;
     RECT  2.16 29.025 49.68 29.295 ;
     RECT  2.16 29.565 49.68 29.835 ;
     RECT  2.16 30.105 49.68 30.375 ;
     RECT  2.16 30.645 49.68 30.915 ;
     RECT  2.16 31.185 49.68 31.455 ;
     RECT  2.16 31.725 49.68 31.995 ;
     RECT  2.16 32.265 49.68 32.535 ;
     RECT  2.16 32.805 49.68 33.075 ;
     RECT  2.16 33.345 49.68 33.615 ;
     RECT  2.16 33.885 49.68 34.155 ;
     RECT  2.16 34.425 49.68 34.695 ;
     RECT  2.16 34.965 49.68 35.235 ;
     RECT  2.16 35.505 49.68 35.775 ;
     RECT  2.16 36.045 49.68 36.315 ;
     RECT  2.16 36.585 49.68 36.855 ;
     RECT  2.16 37.125 49.68 37.395 ;
     RECT  2.16 37.665 49.68 37.935 ;
     RECT  2.16 38.205 49.68 38.475 ;
     RECT  2.16 38.745 49.68 39.015 ;
     RECT  2.16 39.285 49.68 39.555 ;
     RECT  2.16 39.825 49.68 40.095 ;
     RECT  2.16 40.365 49.68 40.635 ;
     RECT  2.16 40.905 49.68 41.175 ;
     RECT  2.16 41.445 49.68 41.715 ;
     RECT  2.16 41.985 49.68 42.255 ;
     RECT  2.16 42.525 49.68 42.795 ;
     RECT  2.16 43.065 49.68 43.335 ;
     RECT  2.16 43.605 49.68 43.875 ;
     RECT  2.16 44.145 49.68 44.415 ;
     RECT  2.16 44.685 49.68 44.955 ;
     RECT  2.16 45.225 49.68 45.36 ;
    LAYER RVTP ;
     RECT  2.16 2.295 49.68 2.565 ;
     RECT  2.16 2.835 49.68 3.105 ;
     RECT  2.16 3.375 49.68 3.645 ;
     RECT  2.16 3.915 49.68 4.185 ;
     RECT  2.16 4.455 49.68 4.725 ;
     RECT  2.16 4.995 49.68 5.265 ;
     RECT  2.16 5.535 49.68 5.805 ;
     RECT  2.16 6.075 49.68 6.345 ;
     RECT  2.16 6.615 49.68 6.885 ;
     RECT  2.16 7.155 49.68 7.425 ;
     RECT  2.16 7.695 49.68 7.965 ;
     RECT  2.16 8.235 49.68 8.505 ;
     RECT  2.16 8.775 49.68 9.045 ;
     RECT  2.16 9.315 49.68 9.585 ;
     RECT  2.16 9.855 49.68 10.125 ;
     RECT  2.16 10.395 49.68 10.665 ;
     RECT  2.16 10.935 49.68 11.205 ;
     RECT  2.16 11.475 49.68 11.745 ;
     RECT  2.16 12.015 49.68 12.285 ;
     RECT  2.16 12.555 49.68 12.825 ;
     RECT  2.16 13.095 49.68 13.365 ;
     RECT  2.16 13.635 49.68 13.905 ;
     RECT  2.16 14.175 49.68 14.445 ;
     RECT  2.16 14.715 49.68 14.985 ;
     RECT  2.16 15.255 49.68 15.525 ;
     RECT  2.16 15.795 49.68 16.065 ;
     RECT  2.16 16.335 49.68 16.605 ;
     RECT  2.16 16.875 49.68 17.145 ;
     RECT  2.16 17.415 49.68 17.685 ;
     RECT  2.16 17.955 49.68 18.225 ;
     RECT  2.16 18.495 49.68 18.765 ;
     RECT  2.16 19.035 49.68 19.305 ;
     RECT  2.16 19.575 49.68 19.845 ;
     RECT  2.16 20.115 49.68 20.385 ;
     RECT  2.16 20.655 49.68 20.925 ;
     RECT  2.16 21.195 49.68 21.465 ;
     RECT  2.16 21.735 49.68 22.005 ;
     RECT  2.16 22.275 49.68 22.545 ;
     RECT  2.16 22.815 49.68 23.085 ;
     RECT  2.16 23.355 49.68 23.625 ;
     RECT  2.16 23.895 49.68 24.165 ;
     RECT  2.16 24.435 49.68 24.705 ;
     RECT  2.16 24.975 49.68 25.245 ;
     RECT  2.16 25.515 49.68 25.785 ;
     RECT  2.16 26.055 49.68 26.325 ;
     RECT  2.16 26.595 49.68 26.865 ;
     RECT  2.16 27.135 49.68 27.405 ;
     RECT  2.16 27.675 49.68 27.945 ;
     RECT  2.16 28.215 49.68 28.485 ;
     RECT  2.16 28.755 49.68 29.025 ;
     RECT  2.16 29.295 49.68 29.565 ;
     RECT  2.16 29.835 49.68 30.105 ;
     RECT  2.16 30.375 49.68 30.645 ;
     RECT  2.16 30.915 49.68 31.185 ;
     RECT  2.16 31.455 49.68 31.725 ;
     RECT  2.16 31.995 49.68 32.265 ;
     RECT  2.16 32.535 49.68 32.805 ;
     RECT  2.16 33.075 49.68 33.345 ;
     RECT  2.16 33.615 49.68 33.885 ;
     RECT  2.16 34.155 49.68 34.425 ;
     RECT  2.16 34.695 49.68 34.965 ;
     RECT  2.16 35.235 49.68 35.505 ;
     RECT  2.16 35.775 49.68 36.045 ;
     RECT  2.16 36.315 49.68 36.585 ;
     RECT  2.16 36.855 49.68 37.125 ;
     RECT  2.16 37.395 49.68 37.665 ;
     RECT  2.16 37.935 49.68 38.205 ;
     RECT  2.16 38.475 49.68 38.745 ;
     RECT  2.16 39.015 49.68 39.285 ;
     RECT  2.16 39.555 49.68 39.825 ;
     RECT  2.16 40.095 49.68 40.365 ;
     RECT  2.16 40.635 49.68 40.905 ;
     RECT  2.16 41.175 49.68 41.445 ;
     RECT  2.16 41.715 49.68 41.985 ;
     RECT  2.16 42.255 49.68 42.525 ;
     RECT  2.16 42.795 49.68 43.065 ;
     RECT  2.16 43.335 49.68 43.605 ;
     RECT  2.16 43.875 49.68 44.145 ;
     RECT  2.16 44.415 49.68 44.685 ;
     RECT  2.16 44.955 49.68 45.225 ;
    LAYER M1 ;
     RECT  2.16 2.151 49.68 45.369 ;
    LAYER M2 ;
     RECT  0.031 6.516 0.103 6.534 ;
     RECT  0.031 10.062 0.103 10.08 ;
     RECT  0.067 14.418 0.103 14.436 ;
     RECT  0.031 17.19 0.103 17.208 ;
     RECT  0.067 21.438 0.103 21.456 ;
     RECT  0.103 11.952 0.139 12.888 ;
     RECT  0.103 14.22 0.139 14.436 ;
     RECT  0.103 23.13 0.139 23.148 ;
     RECT  0.103 33.048 0.139 33.066 ;
     RECT  0.031 7.596 0.175 7.614 ;
     RECT  0.103 8.712 0.175 8.73 ;
     RECT  0.103 10.062 0.175 10.728 ;
     RECT  0.103 15.876 0.175 15.894 ;
     RECT  0.139 14.22 0.239 14.544 ;
     RECT  0.103 17.118 0.239 17.208 ;
     RECT  0.103 22.212 0.247 22.23 ;
     RECT  0.139 23.022 0.247 23.148 ;
     RECT  0.103 21.168 0.355 21.456 ;
     RECT  0.247 22.212 0.383 23.148 ;
     RECT  0.175 7.362 0.391 7.614 ;
     RECT  0.355 38.988 0.391 39.006 ;
     RECT  0.391 7.362 0.427 7.884 ;
     RECT  0.175 15.768 0.427 15.894 ;
     RECT  0.355 21.006 0.427 21.456 ;
     RECT  0.139 32.472 0.427 33.066 ;
     RECT  0.391 34.902 0.427 34.92 ;
     RECT  0.391 38.988 0.427 39.078 ;
     RECT  0.391 42.498 0.427 42.516 ;
     RECT  0.391 44.964 0.427 44.982 ;
     RECT  0.427 7.362 0.463 7.956 ;
     RECT  0.175 8.712 0.463 10.728 ;
     RECT  0.139 11.952 0.463 13.086 ;
     RECT  0.427 20.736 0.463 21.456 ;
     RECT  0.383 22.212 0.463 22.23 ;
     RECT  0.427 32.238 0.463 33.066 ;
     RECT  0.427 38.988 0.463 39.618 ;
     RECT  0.427 42.228 0.463 42.516 ;
     RECT  0.103 4.5 0.499 4.518 ;
     RECT  0.103 24.948 0.499 24.966 ;
     RECT  0.103 27.342 0.499 27.36 ;
     RECT  0.463 30.654 0.499 30.672 ;
     RECT  0.463 32.238 0.499 33.174 ;
     RECT  0.427 34.47 0.499 34.92 ;
     RECT  0.427 37.71 0.499 37.728 ;
     RECT  0.463 38.826 0.499 39.618 ;
     RECT  0.175 40.608 0.499 40.626 ;
     RECT  0.463 42.228 0.499 42.552 ;
     RECT  0.463 44.082 0.499 44.1 ;
     RECT  0.427 44.964 0.499 45.288 ;
     RECT  0.499 4.158 0.535 4.518 ;
     RECT  0.103 5.31 0.535 6.606 ;
     RECT  0.463 11.646 0.535 13.086 ;
     RECT  0.463 18.936 0.535 18.954 ;
     RECT  0.499 27.342 0.535 27.432 ;
     RECT  0.499 28.224 0.535 28.242 ;
     RECT  0.499 32.238 0.535 34.92 ;
     RECT  0.499 36.09 0.535 36.108 ;
     RECT  0.499 37.71 0.535 37.764 ;
     RECT  0.499 38.646 0.535 39.618 ;
     RECT  0.499 40.41 0.535 40.626 ;
     RECT  0.499 41.454 0.535 41.472 ;
     RECT  0.499 42.228 0.535 43.29 ;
     RECT  0.499 44.082 0.535 45.288 ;
     RECT  0.535 27.144 0.823 28.242 ;
     RECT  0.535 29.034 0.823 29.052 ;
     RECT  0.535 18.774 1.147 18.954 ;
     RECT  1.147 18.306 1.175 18.954 ;
     RECT  0.499 30.654 1.175 31.014 ;
     RECT  0.239 14.22 1.399 14.238 ;
     RECT  0.535 3.726 2.16 6.606 ;
     RECT  0.463 7.362 2.16 10.728 ;
     RECT  0.535 11.646 2.16 13.194 ;
     RECT  1.399 14.184 2.16 14.238 ;
     RECT  0.427 15.768 2.16 16.254 ;
     RECT  0.499 17.496 2.16 17.514 ;
     RECT  1.175 18.306 2.16 18.864 ;
     RECT  0.463 20.124 2.16 22.23 ;
     RECT  0.383 23.022 2.16 23.148 ;
     RECT  0.103 23.904 2.16 23.922 ;
     RECT  0.499 24.948 2.16 25.542 ;
     RECT  0.823 27.144 2.16 29.052 ;
     RECT  1.175 30.69 2.16 31.014 ;
     RECT  0.535 31.77 2.16 34.92 ;
     RECT  0.535 35.82 2.16 36.108 ;
     RECT  0.535 37.296 2.16 41.472 ;
     RECT  0.535 42.228 2.16 45.414 ;
     RECT  2.16 2.151 3.307 45.414 ;
     RECT  3.307 2.151 5.819 45.45 ;
     RECT  5.819 2.151 6.755 45.414 ;
     RECT  6.755 2.151 16.411 45.369 ;
     RECT  16.411 2.151 16.627 45.414 ;
     RECT  16.627 2.151 16.871 45.594 ;
     RECT  16.871 2.151 17.195 45.414 ;
     RECT  17.195 2.151 18.823 45.369 ;
     RECT  18.823 2.106 19.607 45.486 ;
     RECT  19.607 2.151 21.055 45.486 ;
     RECT  21.055 2.106 22.739 45.486 ;
     RECT  22.739 2.106 25.223 45.414 ;
     RECT  25.223 2.106 26.851 45.369 ;
     RECT  26.851 2.106 28.255 45.414 ;
     RECT  28.255 2.07 30.731 45.414 ;
     RECT  30.731 2.07 41.107 45.369 ;
     RECT  41.107 1.998 47.903 45.369 ;
     RECT  47.903 2.07 49.68 45.369 ;
     RECT  49.68 2.07 50.603 43.254 ;
     RECT  50.603 2.106 50.711 43.254 ;
     RECT  50.711 2.304 50.747 6.138 ;
     RECT  50.711 7.776 50.747 8.064 ;
     RECT  50.711 9.936 50.747 9.954 ;
     RECT  50.711 11.016 50.747 11.232 ;
     RECT  50.711 13.068 50.747 13.734 ;
     RECT  50.711 14.994 50.747 16.704 ;
     RECT  50.711 17.766 50.747 17.784 ;
     RECT  50.711 21.204 50.747 23.184 ;
     RECT  50.711 25.29 50.747 27.504 ;
     RECT  50.711 28.296 50.747 29.124 ;
     RECT  50.711 32.004 50.747 32.022 ;
     RECT  50.711 32.814 50.747 33.372 ;
     RECT  50.711 34.164 50.747 34.992 ;
     RECT  50.711 35.856 50.747 36.072 ;
     RECT  50.711 36.864 50.747 37.926 ;
     RECT  50.711 39.096 50.747 39.654 ;
     RECT  50.711 40.446 50.747 43.254 ;
     RECT  50.747 42.066 50.783 43.254 ;
     RECT  50.747 2.376 51.719 2.592 ;
     RECT  50.747 3.726 51.719 6.138 ;
     RECT  50.747 25.29 51.719 26.622 ;
     RECT  51.719 2.574 51.755 2.592 ;
     RECT  51.719 3.726 51.755 5.256 ;
     RECT  51.719 6.12 51.755 6.138 ;
     RECT  50.747 11.016 51.755 11.034 ;
     RECT  50.747 13.446 51.755 13.464 ;
     RECT  50.747 14.994 51.755 16.362 ;
     RECT  50.711 18.54 51.755 19.098 ;
     RECT  50.711 20.196 51.755 20.214 ;
     RECT  50.747 21.204 51.755 22.032 ;
     RECT  50.747 23.166 51.755 23.184 ;
     RECT  50.711 24.246 51.755 24.264 ;
     RECT  51.719 25.29 51.755 25.308 ;
     RECT  51.719 26.136 51.755 26.622 ;
     RECT  50.747 28.296 51.755 28.314 ;
     RECT  50.711 30.114 51.755 31.212 ;
     RECT  50.747 34.164 51.755 34.794 ;
     RECT  50.747 35.856 51.755 35.874 ;
     RECT  50.747 37.476 51.755 37.494 ;
     RECT  50.747 40.446 51.755 40.932 ;
     RECT  50.783 42.732 51.755 43.254 ;
    LAYER M3 ;
     RECT  19.44 0.235 19.458 0.571 ;
     RECT  50.688 0.715 50.706 0.859 ;
     RECT  50.652 0.859 50.706 1.291 ;
     RECT  51.732 1.003 51.75 1.579 ;
     RECT  19.44 0.571 19.602 1.723 ;
     RECT  47.88 1.993 47.898 2.065 ;
     RECT  19.044 1.723 19.638 2.101 ;
     RECT  44.676 1.147 44.694 2.101 ;
     RECT  47.592 2.065 47.898 2.101 ;
     RECT  49.212 1.435 49.23 2.101 ;
     RECT  18.828 2.101 19.638 2.143 ;
     RECT  21.06 2.101 21.078 2.143 ;
     RECT  43.632 1.723 43.65 2.143 ;
     RECT  44.676 2.101 45.198 2.143 ;
     RECT  46.368 2.065 46.386 2.143 ;
     RECT  47.304 2.101 47.898 2.143 ;
     RECT  50.184 1.291 50.706 2.155 ;
     RECT  34.815 2.143 34.905 2.191 ;
     RECT  42.915 2.143 43.65 2.191 ;
     RECT  34.815 2.191 34.974 2.227 ;
     RECT  34.812 2.227 34.974 2.263 ;
     RECT  44.676 2.143 46.386 2.263 ;
     RECT  47.304 2.143 48.405 2.263 ;
     RECT  49.176 2.101 49.266 2.263 ;
     RECT  50.148 2.155 50.706 2.293 ;
     RECT  15.915 2.143 16.005 2.299 ;
     RECT  18.615 2.143 19.638 2.299 ;
     RECT  28.26 2.065 28.278 2.299 ;
     RECT  29.415 2.143 29.505 2.299 ;
     RECT  33.192 2.293 33.21 2.299 ;
     RECT  34.452 2.263 35.55 2.299 ;
     RECT  40.215 2.143 40.305 2.299 ;
     RECT  42.915 2.191 43.902 2.299 ;
     RECT  50.148 2.293 50.742 2.327 ;
     RECT  15.915 2.299 16.722 2.335 ;
     RECT  24.015 2.143 24.105 2.335 ;
     RECT  24.84 2.299 24.858 2.335 ;
     RECT  26.715 2.143 26.805 2.335 ;
     RECT  28.188 2.299 28.278 2.335 ;
     RECT  29.124 2.299 29.505 2.335 ;
     RECT  33.192 2.299 33.282 2.335 ;
     RECT  37.515 2.143 37.605 2.335 ;
     RECT  42.915 2.299 43.938 2.335 ;
     RECT  44.676 2.263 49.266 2.335 ;
     RECT  13.215 2.143 13.305 2.371 ;
     RECT  15.66 2.335 17.046 2.371 ;
     RECT  21.06 2.143 21.405 2.371 ;
     RECT  32.115 2.143 32.205 2.371 ;
     RECT  39.456 2.299 40.305 2.371 ;
     RECT  51.696 1.579 51.75 2.399 ;
     RECT  2.415 2.143 2.505 2.413 ;
     RECT  5.115 2.143 5.205 2.413 ;
     RECT  7.815 2.143 7.905 2.413 ;
     RECT  10.515 2.143 10.605 2.413 ;
     RECT  12.924 2.371 13.305 2.413 ;
     RECT  29.124 2.335 29.574 2.413 ;
     RECT  32.115 2.371 32.274 2.413 ;
     RECT  33.084 2.335 33.318 2.413 ;
     RECT  36.756 2.335 37.605 2.413 ;
     RECT  39.384 2.371 40.305 2.413 ;
     RECT  41.112 1.993 41.13 2.413 ;
     RECT  10.515 2.413 10.797 2.461 ;
     RECT  26.715 2.335 27.126 2.461 ;
     RECT  28.008 2.335 28.278 2.461 ;
     RECT  29.124 2.413 29.697 2.461 ;
     RECT  34.452 2.299 35.586 2.461 ;
     RECT  39.384 2.413 41.13 2.461 ;
     RECT  25.848 2.335 25.866 2.488 ;
     RECT  38.88 2.461 41.13 2.489 ;
     RECT  15.408 2.371 17.046 2.491 ;
     RECT  25.848 2.488 25.974 2.491 ;
     RECT  7.815 2.413 8.097 2.497 ;
     RECT  9 2.461 10.797 2.497 ;
     RECT  15.408 2.491 17.118 2.497 ;
     RECT  24.015 2.335 24.858 2.497 ;
     RECT  25.632 2.491 25.974 2.497 ;
     RECT  32.115 2.413 33.318 2.497 ;
     RECT  36.756 2.413 37.797 2.497 ;
     RECT  42.915 2.335 49.266 2.497 ;
     RECT  22.536 2.371 23.13 2.533 ;
     RECT  24.015 2.497 25.974 2.533 ;
     RECT  30.78 2.497 30.798 2.533 ;
     RECT  31.932 2.497 33.318 2.533 ;
     RECT  22.536 2.533 25.974 2.539 ;
     RECT  26.715 2.461 29.697 2.539 ;
     RECT  38.88 2.489 39.402 2.539 ;
     RECT  14.724 2.497 17.19 2.569 ;
     RECT  18.18 2.299 19.638 2.569 ;
     RECT  12.924 2.413 13.497 2.587 ;
     RECT  14.724 2.569 19.638 2.587 ;
     RECT  20.988 2.371 21.69 2.587 ;
     RECT  7.815 2.497 10.797 2.605 ;
     RECT  12.924 2.587 13.518 2.605 ;
     RECT  14.724 2.587 21.69 2.605 ;
     RECT  30.492 2.533 33.318 2.605 ;
     RECT  36.756 2.497 38.034 2.605 ;
     RECT  38.772 2.539 39.402 2.605 ;
     RECT  42.264 2.497 49.266 2.605 ;
     RECT  7.416 2.605 10.797 2.641 ;
     RECT  12.852 2.605 21.69 2.641 ;
     RECT  22.536 2.539 29.697 2.641 ;
     RECT  36.36 2.605 39.402 2.669 ;
     RECT  7.416 2.641 10.926 2.731 ;
     RECT  12.852 2.641 29.697 2.731 ;
     RECT  30.492 2.605 33.606 2.731 ;
     RECT  12.852 2.731 33.606 2.803 ;
     RECT  34.452 2.461 35.622 2.803 ;
     RECT  36.36 2.669 39.366 2.803 ;
     RECT  40.215 2.489 41.13 2.831 ;
     RECT  12.852 2.803 33.642 2.839 ;
     RECT  34.452 2.803 39.366 2.839 ;
     RECT  7.416 2.731 11.502 2.875 ;
     RECT  7.416 2.875 11.97 2.911 ;
     RECT  6.516 2.911 6.534 3.145 ;
     RECT  5.115 2.413 5.397 3.181 ;
     RECT  6.48 3.145 6.534 3.181 ;
     RECT  42.264 2.605 49.302 3.299 ;
     RECT  5.115 3.181 6.534 3.307 ;
     RECT  7.416 2.911 12.078 3.307 ;
     RECT  5.115 3.307 12.078 3.335 ;
     RECT  5.115 3.335 11.754 3.379 ;
     RECT  2.415 2.413 2.697 3.403 ;
     RECT  3.42 3.271 3.438 3.403 ;
     RECT  2.415 3.403 3.438 3.451 ;
     RECT  5.112 3.379 11.754 3.451 ;
     RECT  12.852 2.839 39.366 3.451 ;
     RECT  40.215 2.831 40.497 3.451 ;
     RECT  48.315 3.299 49.302 3.451 ;
     RECT  50.184 2.327 50.742 3.485 ;
     RECT  2.376 3.451 4.014 3.613 ;
     RECT  5.076 3.451 11.754 3.613 ;
     RECT  12.852 3.451 40.497 3.641 ;
     RECT  23.94 3.641 40.497 3.649 ;
     RECT  23.94 3.649 41.418 3.721 ;
     RECT  42.264 3.299 47.466 3.721 ;
     RECT  48.315 3.451 49.338 3.721 ;
     RECT  48.315 3.721 49.41 3.839 ;
     RECT  50.184 3.485 50.706 3.947 ;
     RECT  12.852 3.641 23.202 3.991 ;
     RECT  2.376 3.613 11.754 4.075 ;
     RECT  0.54 3.721 0.558 4.153 ;
     RECT  2.376 4.075 11.862 4.171 ;
     RECT  12.672 3.991 23.202 4.171 ;
     RECT  49.788 4.171 49.806 4.289 ;
     RECT  23.94 3.721 47.466 4.415 ;
     RECT  2.304 4.171 23.202 4.423 ;
     RECT  23.94 4.415 36.198 4.423 ;
     RECT  0.504 4.153 0.558 4.495 ;
     RECT  2.304 4.423 36.198 4.523 ;
     RECT  51.732 2.399 51.75 4.603 ;
     RECT  31.788 4.523 36.198 4.649 ;
     RECT  48.315 3.839 48.762 4.729 ;
     RECT  48.315 4.729 48.942 4.829 ;
     RECT  37.044 4.415 47.466 4.891 ;
     RECT  48.315 4.829 48.87 4.891 ;
     RECT  2.304 4.523 30.978 4.928 ;
     RECT  49.68 4.891 49.698 5.027 ;
     RECT  37.044 4.891 48.87 5.099 ;
     RECT  37.044 5.099 43.902 5.341 ;
     RECT  2.376 4.928 30.978 5.419 ;
     RECT  36.936 5.341 43.902 5.431 ;
     RECT  31.788 4.649 36.126 5.467 ;
     RECT  36.864 5.431 43.902 5.467 ;
     RECT  31.788 5.467 43.902 5.603 ;
     RECT  2.376 5.419 31.014 5.611 ;
     RECT  31.788 5.603 41.166 5.611 ;
     RECT  2.376 5.611 41.166 5.729 ;
     RECT  50.688 3.947 50.706 5.773 ;
     RECT  51.696 4.603 51.75 5.837 ;
     RECT  44.712 5.099 48.87 6.035 ;
     RECT  42.012 5.603 43.902 6.043 ;
     RECT  44.712 6.035 47.538 6.043 ;
     RECT  50.688 5.773 50.742 6.043 ;
     RECT  42.012 6.043 47.538 6.143 ;
     RECT  51.732 5.837 51.75 6.143 ;
     RECT  42.012 6.143 46.926 6.269 ;
     RECT  50.148 6.043 50.742 6.365 ;
     RECT  0.108 4.495 0.558 6.509 ;
     RECT  0.108 6.509 0.522 6.511 ;
     RECT  2.415 5.729 41.166 6.547 ;
     RECT  42.012 6.269 44.442 6.547 ;
     RECT  2.415 6.547 44.442 6.619 ;
     RECT  48.315 6.035 48.87 6.691 ;
     RECT  50.148 6.365 50.706 6.719 ;
     RECT  48.315 6.691 49.266 6.809 ;
     RECT  2.412 6.619 44.442 6.817 ;
     RECT  2.376 6.817 44.442 6.845 ;
     RECT  45.36 6.269 46.926 7.087 ;
     RECT  20.52 6.845 43.794 7.115 ;
     RECT  45.36 7.087 47.502 7.123 ;
     RECT  48.315 6.809 48.942 7.123 ;
     RECT  20.52 7.115 41.454 7.349 ;
     RECT  45.36 7.123 48.942 7.349 ;
     RECT  49.788 7.231 49.806 7.373 ;
     RECT  20.52 7.349 36.774 7.385 ;
     RECT  0.036 6.511 0.522 7.393 ;
     RECT  45.36 7.349 48.726 7.421 ;
     RECT  45.36 7.421 48.597 7.465 ;
     RECT  50.688 6.719 50.706 7.483 ;
     RECT  0.036 7.393 0.558 7.619 ;
     RECT  45.072 7.465 48.597 7.691 ;
     RECT  42.192 7.115 43.794 7.723 ;
     RECT  2.376 6.845 19.746 7.771 ;
     RECT  20.52 7.385 36.486 7.771 ;
     RECT  45.072 7.691 46.17 7.771 ;
     RECT  50.148 7.483 50.706 7.771 ;
     RECT  42.192 7.723 44.01 7.889 ;
     RECT  44.784 7.771 46.17 7.889 ;
     RECT  50.148 7.771 50.742 7.889 ;
     RECT  44.892 7.889 46.17 7.949 ;
     RECT  2.376 7.771 36.486 7.963 ;
     RECT  2.304 7.963 36.486 8.093 ;
     RECT  50.184 7.889 50.742 8.093 ;
     RECT  2.415 8.093 36.486 8.131 ;
     RECT  37.515 7.349 41.454 8.131 ;
     RECT  2.415 8.131 41.454 8.159 ;
     RECT  47.016 7.691 48.597 8.159 ;
     RECT  42.192 7.889 43.83 8.429 ;
     RECT  45.504 7.949 46.17 8.429 ;
     RECT  2.415 8.159 41.31 8.465 ;
     RECT  42.192 8.429 43.686 8.509 ;
     RECT  47.016 8.159 47.574 8.539 ;
     RECT  46.8 8.539 47.574 8.699 ;
     RECT  42.12 8.509 43.686 8.771 ;
     RECT  44.64 8.671 44.658 8.779 ;
     RECT  46.908 8.699 47.574 8.807 ;
     RECT  38.88 8.465 41.31 8.843 ;
     RECT  44.604 8.779 44.658 8.851 ;
     RECT  39.024 8.843 41.31 8.879 ;
     RECT  50.184 8.093 50.706 8.923 ;
     RECT  2.415 8.465 38.106 8.969 ;
     RECT  44.532 8.851 44.658 8.969 ;
     RECT  47.088 8.807 47.574 8.969 ;
     RECT  49.68 8.923 50.706 9.113 ;
     RECT  42.264 8.771 43.686 9.211 ;
     RECT  47.16 8.969 47.574 9.481 ;
     RECT  48.315 8.159 48.597 9.481 ;
     RECT  9.972 8.969 38.106 9.553 ;
     RECT  9.972 9.553 38.214 9.581 ;
     RECT  45.504 8.429 45.897 9.589 ;
     RECT  10.188 9.581 38.214 9.625 ;
     RECT  39.024 8.879 41.274 9.625 ;
     RECT  42.264 9.211 43.902 9.625 ;
     RECT  44.64 8.969 44.658 9.625 ;
     RECT  45.432 9.589 45.897 9.625 ;
     RECT  2.415 8.969 9.09 9.643 ;
     RECT  10.188 9.625 41.274 9.661 ;
     RECT  2.304 9.643 9.09 9.689 ;
     RECT  50.148 9.113 50.706 9.779 ;
     RECT  2.415 9.689 9.09 9.787 ;
     RECT  42.12 9.625 43.902 9.787 ;
     RECT  44.64 9.625 45.897 9.787 ;
     RECT  47.16 9.481 48.597 9.859 ;
     RECT  47.088 9.859 48.597 9.931 ;
     RECT  50.184 9.779 50.706 9.931 ;
     RECT  10.188 9.661 41.346 10.021 ;
     RECT  42.12 9.787 45.897 10.021 ;
     RECT  0.108 7.619 0.558 10.057 ;
     RECT  50.184 9.931 50.742 10.109 ;
     RECT  2.415 9.787 9.234 10.201 ;
     RECT  47.088 9.931 49.194 10.201 ;
     RECT  10.188 10.021 45.897 10.291 ;
     RECT  10.188 10.291 45.954 10.319 ;
     RECT  46.764 10.201 49.194 10.319 ;
     RECT  34.56 10.319 45.954 10.363 ;
     RECT  10.188 10.319 33.786 10.435 ;
     RECT  2.415 10.201 9.378 10.561 ;
     RECT  10.116 10.435 33.786 10.561 ;
     RECT  47.052 10.319 49.194 10.633 ;
     RECT  47.052 10.633 49.266 10.685 ;
     RECT  47.052 10.685 49.23 10.697 ;
     RECT  50.184 10.109 50.706 10.697 ;
     RECT  34.56 10.363 45.99 10.733 ;
     RECT  2.415 10.561 33.786 10.939 ;
     RECT  34.56 10.733 44.442 11.021 ;
     RECT  51.732 10.939 51.75 11.039 ;
     RECT  34.56 11.021 35.73 11.101 ;
     RECT  45.36 10.733 45.99 11.101 ;
     RECT  50.688 10.697 50.706 11.209 ;
     RECT  50.688 11.209 50.742 11.261 ;
     RECT  2.34 10.939 33.786 11.479 ;
     RECT  36.504 11.021 44.442 11.479 ;
     RECT  45.36 11.101 46.17 11.479 ;
     RECT  50.688 11.261 50.706 11.479 ;
     RECT  50.652 11.479 50.706 11.549 ;
     RECT  47.448 10.697 49.23 11.659 ;
     RECT  2.304 11.479 33.786 11.713 ;
     RECT  34.524 11.101 35.73 11.713 ;
     RECT  36.504 11.479 46.17 11.755 ;
     RECT  47.448 11.659 49.734 11.821 ;
     RECT  2.304 11.713 35.73 11.837 ;
     RECT  36.504 11.755 46.386 11.849 ;
     RECT  36.504 11.849 44.694 11.939 ;
     RECT  45.54 11.849 46.386 11.939 ;
     RECT  47.16 11.821 49.734 11.939 ;
     RECT  2.415 11.837 35.73 11.995 ;
     RECT  36.504 11.939 44.334 11.995 ;
     RECT  47.16 11.939 48.834 12.245 ;
     RECT  2.415 11.995 44.334 12.365 ;
     RECT  2.415 12.365 43.506 12.515 ;
     RECT  2.415 12.515 21.654 12.551 ;
     RECT  47.16 12.245 47.178 12.559 ;
     RECT  49.572 11.939 49.734 12.559 ;
     RECT  50.688 11.549 50.706 12.559 ;
     RECT  49.572 12.559 50.706 12.701 ;
     RECT  48.024 12.245 48.834 12.749 ;
     RECT  48.132 12.749 48.762 12.821 ;
     RECT  45.54 11.939 46.17 12.829 ;
     RECT  46.944 12.559 47.178 12.829 ;
     RECT  22.968 12.515 43.506 12.845 ;
     RECT  49.572 12.701 49.59 12.845 ;
     RECT  0.036 10.057 0.558 13.027 ;
     RECT  45.54 12.829 47.178 13.027 ;
     RECT  2.415 12.551 11.718 13.055 ;
     RECT  50.688 12.701 50.706 13.063 ;
     RECT  44.316 12.365 44.334 13.171 ;
     RECT  45.54 13.027 47.25 13.171 ;
     RECT  41.76 12.845 43.506 13.261 ;
     RECT  44.316 13.171 47.25 13.261 ;
     RECT  12.456 12.551 21.654 13.297 ;
     RECT  22.968 12.845 40.986 13.297 ;
     RECT  41.76 13.261 47.25 13.373 ;
     RECT  2.415 13.055 6.678 13.387 ;
     RECT  51.732 12.955 51.75 13.469 ;
     RECT  50.688 13.063 50.742 13.531 ;
     RECT  7.416 13.055 11.718 13.567 ;
     RECT  12.456 13.297 40.986 13.567 ;
     RECT  48.132 12.821 48.597 13.567 ;
     RECT  48.132 13.567 49.05 13.667 ;
     RECT  50.184 13.531 50.742 13.667 ;
     RECT  44.604 13.373 47.25 13.711 ;
     RECT  48.132 13.667 48.906 13.711 ;
     RECT  7.416 13.567 40.986 13.801 ;
     RECT  41.76 13.373 43.794 13.801 ;
     RECT  44.604 13.711 48.906 13.829 ;
     RECT  50.688 13.667 50.742 13.853 ;
     RECT  2.304 13.387 6.678 13.945 ;
     RECT  7.416 13.801 43.794 13.945 ;
     RECT  44.604 13.829 48.597 14.099 ;
     RECT  2.304 13.945 43.794 14.143 ;
     RECT  44.604 14.099 47.574 14.143 ;
     RECT  0.036 13.027 0.882 14.179 ;
     RECT  49.752 14.107 49.77 14.207 ;
     RECT  50.688 13.853 50.706 14.395 ;
     RECT  2.304 14.143 47.574 14.513 ;
     RECT  50.184 14.395 50.706 14.747 ;
     RECT  48.315 14.099 48.597 14.755 ;
     RECT  2.415 14.513 47.574 14.909 ;
     RECT  48.315 14.755 48.726 14.989 ;
     RECT  48.276 14.989 48.726 15.089 ;
     RECT  48.315 15.089 48.726 15.421 ;
     RECT  49.716 15.259 49.734 15.421 ;
     RECT  2.415 14.909 47.466 15.449 ;
     RECT  48.315 15.421 49.734 15.529 ;
     RECT  50.688 14.747 50.706 15.529 ;
     RECT  2.415 15.449 43.542 15.547 ;
     RECT  48.315 15.529 50.706 16.097 ;
     RECT  44.316 15.449 47.106 16.295 ;
     RECT  2.304 15.547 43.542 16.303 ;
     RECT  44.316 16.295 46.386 16.303 ;
     RECT  51.732 14.971 51.75 16.367 ;
     RECT  2.304 16.303 46.386 16.445 ;
     RECT  50.148 16.097 50.706 16.501 ;
     RECT  2.304 16.445 46.17 16.529 ;
     RECT  48.315 16.097 49.086 16.529 ;
     RECT  47.16 16.315 47.466 16.681 ;
     RECT  48.315 16.529 48.654 16.681 ;
     RECT  50.148 16.501 50.742 16.733 ;
     RECT  47.16 16.681 48.654 16.799 ;
     RECT  47.16 16.799 48.597 16.979 ;
     RECT  47.16 16.979 47.466 17.185 ;
     RECT  0.036 14.179 1.422 17.213 ;
     RECT  2.304 16.529 44.442 17.275 ;
     RECT  50.148 16.733 50.706 17.275 ;
     RECT  45.615 16.529 46.098 17.383 ;
     RECT  47.052 17.185 47.466 17.383 ;
     RECT  49.608 17.275 50.706 17.447 ;
     RECT  2.268 17.275 44.442 17.609 ;
     RECT  45.615 17.383 47.466 17.659 ;
     RECT  2.268 17.609 44.298 17.693 ;
     RECT  45.036 17.659 47.466 17.761 ;
     RECT  48.24 16.979 48.597 17.761 ;
     RECT  50.148 17.447 50.706 17.761 ;
     RECT  50.148 17.761 50.742 17.879 ;
     RECT  50.688 17.879 50.742 17.885 ;
     RECT  45.036 17.761 48.597 18.031 ;
     RECT  45.036 18.031 49.266 18.149 ;
     RECT  45.036 18.149 49.23 18.221 ;
     RECT  2.268 17.693 43.902 18.293 ;
     RECT  45.432 18.221 49.23 18.563 ;
     RECT  0.072 17.213 1.422 18.571 ;
     RECT  2.268 18.293 43.614 18.571 ;
     RECT  45.432 18.563 48.87 19.075 ;
     RECT  45.288 19.075 48.87 19.103 ;
     RECT  51.732 18.427 51.75 19.103 ;
     RECT  47.304 19.103 48.87 19.229 ;
     RECT  45.288 19.103 46.53 19.277 ;
     RECT  44.46 19.039 44.478 19.381 ;
     RECT  44.352 19.381 44.478 19.382 ;
     RECT  0.072 18.571 43.614 19.483 ;
     RECT  44.352 19.382 44.442 19.483 ;
     RECT  50.688 17.885 50.706 19.579 ;
     RECT  48.315 19.229 48.87 19.777 ;
     RECT  48.315 19.777 48.978 19.849 ;
     RECT  48.315 19.849 49.23 20.011 ;
     RECT  50.184 19.579 50.706 20.011 ;
     RECT  48.315 20.011 50.706 20.039 ;
     RECT  45.615 19.277 46.53 20.083 ;
     RECT  47.304 19.229 47.394 20.083 ;
     RECT  49.788 20.039 50.706 20.111 ;
     RECT  48.315 20.039 49.05 20.155 ;
     RECT  0.072 19.483 44.442 20.191 ;
     RECT  45.615 20.083 47.394 20.191 ;
     RECT  51.732 20.155 51.75 20.219 ;
     RECT  0.072 20.191 47.394 20.389 ;
     RECT  48.132 20.155 49.05 20.389 ;
     RECT  0.072 20.389 49.05 20.417 ;
     RECT  50.148 20.111 50.706 20.579 ;
     RECT  0.072 20.417 48.762 20.651 ;
     RECT  0.072 20.651 47.538 20.687 ;
     RECT  48.276 20.651 48.762 20.759 ;
     RECT  0.072 20.687 45.897 20.993 ;
     RECT  48.315 20.759 48.762 21.235 ;
     RECT  0.072 20.993 44.19 21.341 ;
     RECT  1.98 21.341 44.19 21.389 ;
     RECT  1.98 21.389 4.05 21.425 ;
     RECT  0.072 21.341 0.846 21.461 ;
     RECT  46.656 20.687 47.538 21.505 ;
     RECT  48.315 21.235 49.122 21.505 ;
     RECT  50.184 20.579 50.706 21.569 ;
     RECT  44.928 20.993 45.897 21.739 ;
     RECT  46.656 21.505 49.122 21.739 ;
     RECT  4.788 21.389 44.19 21.811 ;
     RECT  44.928 21.739 49.122 21.811 ;
     RECT  51.732 21.163 51.75 22.037 ;
     RECT  4.788 21.811 49.122 22.045 ;
     RECT  1.98 21.425 3.798 22.207 ;
     RECT  4.788 22.045 49.23 22.207 ;
     RECT  4.788 22.207 49.302 22.315 ;
     RECT  50.58 21.569 50.706 22.441 ;
     RECT  50.58 22.441 50.742 22.493 ;
     RECT  4.788 22.315 49.59 22.541 ;
     RECT  4.788 22.541 49.302 22.577 ;
     RECT  4.788 22.577 49.23 22.739 ;
     RECT  1.98 22.207 4.05 22.747 ;
     RECT  4.788 22.739 48.597 22.747 ;
     RECT  1.98 22.747 48.597 23.189 ;
     RECT  51.732 23.035 51.75 23.189 ;
     RECT  50.184 22.603 50.238 23.323 ;
     RECT  50.148 23.323 50.238 23.36 ;
     RECT  1.98 23.189 44.046 23.819 ;
     RECT  44.784 23.189 48.597 23.819 ;
     RECT  50.652 23.467 50.706 23.819 ;
     RECT  7.416 23.819 44.046 23.935 ;
     RECT  44.784 23.819 47.322 23.935 ;
     RECT  7.416 23.935 47.322 24.089 ;
     RECT  48.315 23.819 48.597 24.169 ;
     RECT  49.86 24.043 49.878 24.197 ;
     RECT  45.504 24.089 47.322 24.431 ;
     RECT  48.315 24.169 48.798 24.475 ;
     RECT  45.615 24.431 47.322 24.637 ;
     RECT  48.315 24.475 49.806 24.737 ;
     RECT  1.98 23.819 6.462 24.745 ;
     RECT  7.416 24.089 44.73 24.745 ;
     RECT  45.615 24.637 47.358 24.781 ;
     RECT  48.315 24.737 48.942 24.781 ;
     RECT  49.788 24.737 49.806 24.809 ;
     RECT  45.615 24.781 48.942 24.899 ;
     RECT  51.732 24.187 51.75 25.051 ;
     RECT  48.315 24.899 48.942 25.313 ;
     RECT  50.688 23.819 50.706 25.321 ;
     RECT  50.688 25.321 50.742 25.373 ;
     RECT  51.696 25.051 51.75 25.547 ;
     RECT  45.615 24.899 47.358 25.675 ;
     RECT  1.98 24.745 44.73 25.709 ;
     RECT  49.788 25.627 49.806 25.771 ;
     RECT  50.688 25.373 50.706 25.771 ;
     RECT  0.108 21.461 0.846 25.805 ;
     RECT  49.788 25.771 50.706 25.853 ;
     RECT  45.615 25.675 47.574 26.023 ;
     RECT  48.315 25.313 48.906 26.023 ;
     RECT  45.615 26.023 48.906 26.095 ;
     RECT  49.788 25.853 49.806 26.095 ;
     RECT  45.615 26.095 49.806 26.159 ;
     RECT  45.615 26.159 47.574 26.329 ;
     RECT  48.315 26.159 49.806 26.519 ;
     RECT  45.036 26.329 47.574 26.555 ;
     RECT  51.732 25.547 51.75 26.627 ;
     RECT  50.688 25.853 50.706 26.779 ;
     RECT  50.148 26.779 50.706 26.869 ;
     RECT  45.108 26.555 47.574 27.175 ;
     RECT  48.315 26.519 49.014 27.175 ;
     RECT  1.98 25.709 44.226 27.329 ;
     RECT  45.108 27.175 49.014 27.329 ;
     RECT  0.144 25.805 0.846 27.337 ;
     RECT  0.108 27.337 0.846 27.389 ;
     RECT  45.108 27.329 48.597 27.445 ;
     RECT  45.072 27.445 48.597 27.677 ;
     RECT  50.148 26.869 50.742 27.677 ;
     RECT  1.98 27.329 44.118 27.68 ;
     RECT  1.98 27.68 33.282 27.869 ;
     RECT  45.072 27.677 46.602 27.877 ;
     RECT  1.98 27.869 4.05 27.905 ;
     RECT  4.788 27.869 33.282 27.917 ;
     RECT  44.892 27.877 46.602 27.917 ;
     RECT  50.148 27.677 50.706 28.139 ;
     RECT  1.98 27.905 4.014 28.319 ;
     RECT  34.056 27.68 44.118 28.319 ;
     RECT  51.732 28.219 51.75 28.319 ;
     RECT  17.892 27.917 33.282 28.417 ;
     RECT  0.144 27.389 0.846 28.445 ;
     RECT  50.184 28.139 50.706 28.453 ;
     RECT  47.34 27.677 48.597 28.525 ;
     RECT  47.34 28.525 48.834 28.561 ;
     RECT  4.788 27.917 17.154 28.651 ;
     RECT  17.892 28.417 33.57 28.651 ;
     RECT  34.308 28.319 44.118 28.679 ;
     RECT  2.304 28.319 4.014 28.687 ;
     RECT  4.788 28.651 33.57 28.687 ;
     RECT  45.615 27.917 46.602 28.759 ;
     RECT  47.34 28.561 49.338 28.759 ;
     RECT  45.615 28.759 49.338 28.921 ;
     RECT  45.072 28.921 49.338 28.949 ;
     RECT  48.315 28.949 49.338 28.985 ;
     RECT  2.304 28.687 33.57 29.065 ;
     RECT  34.308 28.679 43.938 29.065 ;
     RECT  45.072 28.949 47.574 29.083 ;
     RECT  50.184 28.453 50.742 29.083 ;
     RECT  44.928 29.083 47.574 29.129 ;
     RECT  44.928 29.129 45.897 29.219 ;
     RECT  46.764 29.129 47.574 29.219 ;
     RECT  0.144 28.445 0.558 29.261 ;
     RECT  50.148 29.083 50.742 29.261 ;
     RECT  47.196 29.219 47.574 29.399 ;
     RECT  0.144 29.261 0.522 29.405 ;
     RECT  2.304 29.065 43.938 29.489 ;
     RECT  47.196 29.399 47.466 29.525 ;
     RECT  0.18 29.405 0.522 29.549 ;
     RECT  50.148 29.261 50.706 29.759 ;
     RECT  0.18 29.549 0.342 30.125 ;
     RECT  48.315 28.985 48.654 30.145 ;
     RECT  2.304 29.489 32.49 30.235 ;
     RECT  47.196 29.525 47.322 30.271 ;
     RECT  48.315 30.145 49.23 30.371 ;
     RECT  2.268 30.235 32.49 30.379 ;
     RECT  33.264 29.489 43.938 30.379 ;
     RECT  46.728 30.271 47.322 30.379 ;
     RECT  48.315 30.371 48.597 30.379 ;
     RECT  2.268 30.379 43.938 30.407 ;
     RECT  0.252 30.125 0.342 30.649 ;
     RECT  46.728 30.379 48.597 30.649 ;
     RECT  50.688 29.759 50.706 30.667 ;
     RECT  45.615 29.219 45.897 30.685 ;
     RECT  0.252 30.649 1.17 30.701 ;
     RECT  45.468 30.685 45.897 30.721 ;
     RECT  46.656 30.649 48.597 30.721 ;
     RECT  0.288 30.701 1.17 30.749 ;
     RECT  45.468 30.721 48.597 30.839 ;
     RECT  2.304 30.407 43.938 30.847 ;
     RECT  45.468 30.839 47.538 30.875 ;
     RECT  2.304 30.847 44.442 30.947 ;
     RECT  2.34 30.947 44.442 30.991 ;
     RECT  45.468 30.875 46.314 30.991 ;
     RECT  51.732 29.947 51.75 31.217 ;
     RECT  48.315 30.839 48.597 31.261 ;
     RECT  0.288 30.749 0.558 31.277 ;
     RECT  48.315 31.261 48.69 31.531 ;
     RECT  2.34 30.991 46.314 31.729 ;
     RECT  47.448 30.875 47.538 31.729 ;
     RECT  2.34 31.729 47.538 31.765 ;
     RECT  48.315 31.531 48.762 31.765 ;
     RECT  2.34 31.765 48.762 31.991 ;
     RECT  4.788 31.991 48.762 31.997 ;
     RECT  50.184 30.667 50.706 31.997 ;
     RECT  50.688 31.997 50.706 31.999 ;
     RECT  45.072 31.997 48.762 32.071 ;
     RECT  45.072 32.071 48.87 32.369 ;
     RECT  45.072 32.369 48.654 32.459 ;
     RECT  0.324 31.277 0.558 32.467 ;
     RECT  0.144 32.467 0.558 32.573 ;
     RECT  49.608 32.269 49.626 32.573 ;
     RECT  2.34 31.991 3.978 32.731 ;
     RECT  4.788 31.997 44.01 32.731 ;
     RECT  2.196 32.731 3.978 32.737 ;
     RECT  4.788 32.731 44.226 32.737 ;
     RECT  2.196 32.737 44.226 32.771 ;
     RECT  45.072 32.459 48.597 32.779 ;
     RECT  2.196 32.771 44.01 32.861 ;
     RECT  50.688 31.999 50.742 32.971 ;
     RECT  45 32.779 48.597 32.999 ;
     RECT  50.148 32.971 50.742 33.008 ;
     RECT  45.072 32.999 47.466 33.035 ;
     RECT  0.144 32.573 0.522 33.043 ;
     RECT  0.108 33.043 0.522 33.149 ;
     RECT  47.124 33.035 47.322 33.269 ;
     RECT  48.312 32.999 48.597 33.313 ;
     RECT  0.144 33.149 0.522 33.437 ;
     RECT  50.184 33.008 50.742 33.437 ;
     RECT  0.468 33.437 0.522 33.547 ;
     RECT  48.312 33.313 49.194 33.583 ;
     RECT  2.34 32.861 44.01 33.655 ;
     RECT  45.072 33.035 46.386 33.809 ;
     RECT  48.312 33.583 49.338 33.809 ;
     RECT  0.468 33.547 0.558 33.883 ;
     RECT  47.124 33.269 47.142 33.889 ;
     RECT  2.34 33.655 44.226 33.917 ;
     RECT  0.468 33.883 1.17 33.961 ;
     RECT  47.016 33.889 47.142 33.989 ;
     RECT  0.468 33.961 1.206 34.079 ;
     RECT  48.315 33.809 49.338 34.115 ;
     RECT  2.415 33.917 44.226 34.219 ;
     RECT  45.072 33.809 46.278 34.219 ;
     RECT  2.415 34.219 46.278 34.259 ;
     RECT  0.468 34.079 0.558 34.267 ;
     RECT  50.184 33.437 50.706 34.267 ;
     RECT  50.148 34.267 50.706 34.349 ;
     RECT  49.572 34.411 49.59 34.457 ;
     RECT  0.144 34.267 0.558 34.589 ;
     RECT  41.868 34.259 46.278 34.619 ;
     RECT  41.868 34.619 44.838 34.655 ;
     RECT  45.615 34.619 46.278 34.771 ;
     RECT  47.16 34.051 47.394 34.771 ;
     RECT  51.732 33.979 51.75 34.799 ;
     RECT  2.415 34.259 41.058 34.843 ;
     RECT  45.615 34.771 47.394 34.889 ;
     RECT  50.688 34.349 50.706 34.969 ;
     RECT  0.396 34.589 0.558 35.021 ;
     RECT  2.304 34.843 41.058 35.041 ;
     RECT  41.868 34.655 44.802 35.041 ;
     RECT  46.728 34.889 47.394 35.041 ;
     RECT  48.315 34.115 48.69 35.041 ;
     RECT  2.304 35.041 44.802 35.159 ;
     RECT  50.688 34.969 50.742 35.165 ;
     RECT  46.728 35.041 48.69 35.275 ;
     RECT  6.984 35.159 44.802 35.429 ;
     RECT  7.092 35.429 44.802 35.437 ;
     RECT  45.615 34.889 45.897 35.437 ;
     RECT  7.092 35.437 45.897 35.465 ;
     RECT  7.236 35.465 45.897 35.501 ;
     RECT  46.728 35.275 48.942 35.545 ;
     RECT  2.304 35.159 6.246 35.597 ;
     RECT  46.728 35.545 49.05 35.699 ;
     RECT  2.415 35.597 6.246 35.735 ;
     RECT  0.396 35.021 0.522 35.755 ;
     RECT  0.144 35.755 0.522 35.815 ;
     RECT  48.315 35.699 49.05 35.815 ;
     RECT  50.688 35.165 50.706 35.851 ;
     RECT  51.732 35.707 51.75 35.879 ;
     RECT  9.072 35.501 45.897 35.995 ;
     RECT  46.728 35.699 47.466 35.995 ;
     RECT  50.184 35.851 50.706 36.049 ;
     RECT  48.315 35.815 49.086 36.085 ;
     RECT  48.315 36.085 49.302 36.139 ;
     RECT  50.184 36.049 50.742 36.139 ;
     RECT  48.315 36.139 50.742 36.149 ;
     RECT  4.932 35.735 6.246 36.247 ;
     RECT  7.236 35.501 8.298 36.247 ;
     RECT  9.072 35.995 47.466 36.247 ;
     RECT  4.932 36.247 47.466 36.365 ;
     RECT  0.144 35.815 0.558 36.461 ;
     RECT  2.415 35.735 4.158 36.481 ;
     RECT  4.932 36.365 44.154 36.481 ;
     RECT  44.892 36.365 47.466 36.481 ;
     RECT  48.315 36.149 49.806 36.481 ;
     RECT  0.18 36.461 0.558 36.571 ;
     RECT  44.892 36.481 49.806 36.617 ;
     RECT  2.415 36.481 44.154 36.625 ;
     RECT  2.304 36.625 44.154 36.749 ;
     RECT  50.688 36.149 50.742 36.893 ;
     RECT  50.688 36.893 50.706 36.895 ;
     RECT  0.18 36.571 0.63 37.037 ;
     RECT  44.892 36.617 49.014 37.049 ;
     RECT  50.148 36.895 50.706 37.328 ;
     RECT  0.18 37.037 0.558 37.387 ;
     RECT  2.415 36.749 44.154 37.435 ;
     RECT  44.892 37.049 48.597 37.435 ;
     RECT  51.732 37.435 51.75 37.499 ;
     RECT  2.415 37.435 48.597 37.613 ;
     RECT  2.415 37.613 46.962 37.723 ;
     RECT  50.688 37.328 50.706 37.9 ;
     RECT  50.688 37.9 50.742 38.045 ;
     RECT  50.688 38.045 50.706 38.101 ;
     RECT  0.144 37.387 0.558 38.189 ;
     RECT  2.304 37.723 46.962 38.189 ;
     RECT  47.7 37.613 48.597 38.245 ;
     RECT  49.356 37.723 49.374 38.245 ;
     RECT  2.304 38.189 41.166 38.435 ;
     RECT  41.94 38.189 46.962 38.471 ;
     RECT  50.148 38.101 50.706 38.507 ;
     RECT  45 38.471 46.962 38.551 ;
     RECT  47.7 38.245 49.374 38.551 ;
     RECT  45 38.551 49.374 38.641 ;
     RECT  41.94 38.471 44.118 38.669 ;
     RECT  0.18 38.189 0.558 38.765 ;
     RECT  41.94 38.669 43.938 38.765 ;
     RECT  45 38.641 49.626 38.765 ;
     RECT  45 38.765 48.942 38.813 ;
     RECT  0.252 38.765 0.558 38.909 ;
     RECT  50.688 38.507 50.706 39.091 ;
     RECT  45.072 38.813 48.942 39.209 ;
     RECT  2.415 38.435 41.166 39.217 ;
     RECT  45.072 39.209 46.566 39.245 ;
     RECT  50.688 39.091 50.742 39.289 ;
     RECT  2.304 39.217 41.166 39.355 ;
     RECT  41.94 38.765 43.758 39.355 ;
     RECT  47.304 39.209 47.574 39.479 ;
     RECT  2.304 39.355 43.758 39.595 ;
     RECT  2.304 39.595 44.55 39.725 ;
     RECT  2.304 39.725 43.866 39.773 ;
     RECT  50.148 39.289 50.742 39.773 ;
     RECT  48.315 39.209 48.942 39.865 ;
     RECT  28.548 39.773 43.866 39.893 ;
     RECT  51.66 39.883 51.678 40.013 ;
     RECT  48.315 39.865 49.266 40.019 ;
     RECT  0.36 38.909 0.558 40.075 ;
     RECT  50.148 39.773 50.706 40.171 ;
     RECT  0.144 40.075 0.558 40.205 ;
     RECT  48.315 40.019 48.618 40.397 ;
     RECT  45.615 39.245 46.566 40.441 ;
     RECT  47.304 39.479 47.502 40.441 ;
     RECT  0.18 40.205 0.558 40.493 ;
     RECT  2.304 39.773 27.486 40.567 ;
     RECT  45.615 40.441 47.502 40.567 ;
     RECT  48.315 40.397 48.597 40.567 ;
     RECT  28.548 39.893 43.758 40.639 ;
     RECT  2.304 40.567 27.522 40.675 ;
     RECT  2.304 40.675 27.594 40.711 ;
     RECT  28.548 40.639 43.83 40.711 ;
     RECT  45.615 40.567 48.597 40.711 ;
     RECT  49.68 40.171 50.706 40.739 ;
     RECT  2.304 40.711 27.774 40.829 ;
     RECT  49.824 40.739 50.706 40.829 ;
     RECT  51.732 40.315 51.75 40.937 ;
     RECT  0.18 40.493 0.522 40.939 ;
     RECT  45.144 40.711 48.597 40.981 ;
     RECT  45.108 40.981 48.597 41.071 ;
     RECT  44.856 41.071 48.597 41.107 ;
     RECT  44.784 41.107 48.597 41.179 ;
     RECT  0.144 40.939 0.522 41.215 ;
     RECT  44.784 41.179 48.978 41.279 ;
     RECT  49.824 40.829 49.842 41.279 ;
     RECT  0.144 41.215 0.558 41.357 ;
     RECT  28.512 40.711 43.83 41.449 ;
     RECT  44.784 41.279 48.726 41.449 ;
     RECT  50.688 40.829 50.706 41.449 ;
     RECT  2.304 40.829 27.666 41.501 ;
     RECT  50.688 41.449 50.742 41.611 ;
     RECT  50.184 41.611 50.742 41.747 ;
     RECT  2.34 41.501 27.666 41.755 ;
     RECT  28.512 41.449 48.726 41.755 ;
     RECT  2.34 41.755 48.726 41.909 ;
     RECT  0.18 41.357 0.558 41.933 ;
     RECT  45 41.909 48.726 42.061 ;
     RECT  50.688 41.747 50.742 42.061 ;
     RECT  0.252 41.933 0.558 42.077 ;
     RECT  45 42.061 49.23 42.179 ;
     RECT  50.688 42.061 50.778 42.221 ;
     RECT  45 42.179 49.158 42.323 ;
     RECT  45 42.323 49.014 42.359 ;
     RECT  46.764 42.359 49.014 42.449 ;
     RECT  50.688 42.221 50.742 42.475 ;
     RECT  2.34 41.909 43.83 42.727 ;
     RECT  46.764 42.449 48.597 42.755 ;
     RECT  47.664 42.755 48.597 42.899 ;
     RECT  48.168 42.899 48.597 42.989 ;
     RECT  50.148 42.475 50.742 42.989 ;
     RECT  0.396 42.077 0.558 43.003 ;
     RECT  2.34 42.727 43.938 43.061 ;
     RECT  0.144 43.003 0.558 43.085 ;
     RECT  50.724 42.989 50.742 43.085 ;
     RECT  45 42.359 45.897 43.141 ;
     RECT  2.34 43.061 38.574 43.169 ;
     RECT  48.24 42.989 48.597 43.169 ;
     RECT  51.732 42.727 51.75 43.259 ;
     RECT  0.144 43.085 0.522 43.373 ;
     RECT  39.348 43.061 43.938 43.411 ;
     RECT  44.928 43.141 45.897 43.411 ;
     RECT  39.348 43.411 45.897 43.529 ;
     RECT  46.764 42.755 46.782 43.529 ;
     RECT  2.34 43.169 38.466 43.627 ;
     RECT  2.304 43.627 38.466 43.709 ;
     RECT  39.348 43.529 44.226 43.709 ;
     RECT  2.304 43.709 27.702 43.771 ;
     RECT  28.476 43.709 38.466 43.799 ;
     RECT  2.268 43.771 27.702 43.808 ;
     RECT  0.432 43.373 0.522 43.843 ;
     RECT  2.415 43.808 27.702 43.871 ;
     RECT  5.115 43.871 27.702 44.105 ;
     RECT  0.432 43.843 0.558 44.107 ;
     RECT  28.908 43.799 38.466 44.113 ;
     RECT  2.415 43.871 4.374 44.177 ;
     RECT  5.115 44.105 11.466 44.339 ;
     RECT  42.732 43.709 43.938 44.339 ;
     RECT  5.115 44.339 11.214 44.375 ;
     RECT  2.415 44.177 3.366 44.381 ;
     RECT  12.6 44.105 27.702 44.447 ;
     RECT  28.908 44.113 38.574 44.455 ;
     RECT  39.348 43.709 41.49 44.455 ;
     RECT  5.115 44.375 10.797 44.477 ;
     RECT  12.78 44.447 27.702 44.477 ;
     RECT  42.732 44.339 43.794 44.491 ;
     RECT  9.432 44.477 10.797 44.609 ;
     RECT  2.415 44.381 3.33 44.635 ;
     RECT  9.432 44.609 9.45 44.645 ;
     RECT  0.144 44.107 0.558 44.653 ;
     RECT  12.78 44.477 22.446 44.717 ;
     RECT  4.356 44.177 4.374 44.725 ;
     RECT  5.115 44.477 8.586 44.725 ;
     RECT  23.4 44.477 27.702 44.725 ;
     RECT  28.908 44.455 41.49 44.725 ;
     RECT  2.304 44.635 3.33 44.753 ;
     RECT  28.908 44.725 41.634 44.753 ;
     RECT  23.4 44.725 27.738 44.761 ;
     RECT  28.908 44.753 36.27 44.761 ;
     RECT  37.08 44.753 41.634 44.761 ;
     RECT  42.372 44.491 43.794 44.761 ;
     RECT  4.356 44.725 8.586 44.765 ;
     RECT  13.104 44.717 22.446 44.879 ;
     RECT  23.4 44.761 36.27 44.879 ;
     RECT  37.08 44.761 43.794 44.879 ;
     RECT  14.508 44.879 22.446 44.909 ;
     RECT  13.104 44.879 13.698 44.915 ;
     RECT  14.508 44.909 17.442 44.915 ;
     RECT  23.4 44.879 36.126 44.915 ;
     RECT  31.608 44.915 36.054 44.951 ;
     RECT  37.08 44.879 43.362 44.951 ;
     RECT  37.116 44.951 39.006 44.957 ;
     RECT  37.515 44.957 39.006 44.96 ;
     RECT  13.104 44.915 13.497 44.987 ;
     RECT  34.344 44.951 36.054 44.987 ;
     RECT  14.508 44.915 17.298 44.996 ;
     RECT  34.416 44.987 36.054 45.005 ;
     RECT  4.356 44.765 8.55 45.023 ;
     RECT  31.608 44.951 33.606 45.023 ;
     RECT  39.96 44.951 43.362 45.023 ;
     RECT  14.544 44.996 17.298 45.053 ;
     RECT  4.356 45.023 5.922 45.059 ;
     RECT  0.144 44.653 1.17 45.101 ;
     RECT  2.412 44.753 3.33 45.107 ;
     RECT  6.732 45.023 8.097 45.107 ;
     RECT  10.515 44.609 10.797 45.107 ;
     RECT  13.215 44.987 13.497 45.107 ;
     RECT  31.608 45.023 32.397 45.107 ;
     RECT  37.515 44.96 37.797 45.107 ;
     RECT  39.96 45.023 40.497 45.107 ;
     RECT  41.616 45.023 43.197 45.107 ;
     RECT  45.615 43.529 45.897 45.107 ;
     RECT  48.315 43.169 48.597 45.107 ;
     RECT  18.615 44.909 22.446 45.149 ;
     RECT  25.2 44.915 30.726 45.149 ;
     RECT  31.608 45.107 32.205 45.149 ;
     RECT  33.588 45.023 33.606 45.149 ;
     RECT  34.815 45.005 36.054 45.149 ;
     RECT  38.844 44.96 39.006 45.149 ;
     RECT  41.616 45.107 43.038 45.149 ;
     RECT  6.732 45.107 7.974 45.185 ;
     RECT  14.868 45.053 17.298 45.185 ;
     RECT  18.615 45.149 20.574 45.185 ;
     RECT  21.315 45.149 21.69 45.185 ;
     RECT  23.4 44.915 24.462 45.185 ;
     RECT  25.2 45.149 27.522 45.185 ;
     RECT  38.844 45.149 38.862 45.185 ;
     RECT  41.616 45.149 41.742 45.185 ;
     RECT  15.768 45.185 17.19 45.197 ;
     RECT  23.4 45.185 24.174 45.229 ;
     RECT  2.412 45.107 2.505 45.245 ;
     RECT  20.232 45.185 20.574 45.257 ;
     RECT  34.815 45.149 35.262 45.257 ;
     RECT  3.312 45.107 3.33 45.265 ;
     RECT  4.356 45.059 5.814 45.265 ;
     RECT  6.732 45.185 7.905 45.293 ;
     RECT  29.415 45.149 29.754 45.293 ;
     RECT  31.932 45.149 32.205 45.293 ;
     RECT  39.96 45.107 40.338 45.293 ;
     RECT  28.332 45.149 28.35 45.299 ;
     RECT  7.704 45.293 7.905 45.329 ;
     RECT  14.868 45.185 14.886 45.329 ;
     RECT  20.556 45.257 20.574 45.329 ;
     RECT  22.68 45.229 24.174 45.329 ;
     RECT  25.2 45.185 25.65 45.329 ;
     RECT  41.616 45.185 41.634 45.329 ;
     RECT  2.415 45.245 2.505 45.377 ;
     RECT  3.312 45.265 5.814 45.377 ;
     RECT  7.815 45.329 7.905 45.377 ;
     RECT  10.515 45.107 10.605 45.377 ;
     RECT  13.215 45.107 13.305 45.377 ;
     RECT  15.915 45.197 17.19 45.377 ;
     RECT  18.615 45.185 18.882 45.377 ;
     RECT  21.315 45.185 21.405 45.377 ;
     RECT  22.68 45.329 24.105 45.377 ;
     RECT  26.715 45.185 26.874 45.377 ;
     RECT  29.415 45.293 29.505 45.377 ;
     RECT  32.115 45.293 32.205 45.377 ;
     RECT  34.815 45.257 34.905 45.377 ;
     RECT  37.515 45.107 37.605 45.377 ;
     RECT  40.215 45.293 40.305 45.377 ;
     RECT  42.915 45.149 43.005 45.377 ;
     RECT  45.615 45.107 45.705 45.377 ;
     RECT  48.315 45.107 48.405 45.377 ;
     RECT  6.732 45.293 6.75 45.419 ;
     RECT  16.416 45.377 17.19 45.419 ;
     RECT  18.828 45.377 18.882 45.419 ;
     RECT  22.68 45.377 23.418 45.419 ;
     RECT  25.2 45.329 25.218 45.419 ;
     RECT  26.856 45.377 26.874 45.419 ;
     RECT  30.708 45.149 30.726 45.419 ;
     RECT  3.312 45.377 4.842 45.455 ;
     RECT  5.796 45.377 5.814 45.455 ;
     RECT  18.828 45.419 18.846 45.491 ;
     RECT  22.716 45.419 22.734 45.491 ;
     RECT  3.384 45.455 4.842 45.533 ;
     RECT  16.416 45.419 16.866 45.599 ;
     RECT  3.96 45.533 4.842 45.821 ;
     RECT  0.396 45.101 1.17 46.109 ;
     RECT  1.152 46.109 1.17 46.253 ;
     RECT  0.396 46.109 0.414 46.397 ;
     RECT  4.248 45.821 4.842 46.541 ;
     RECT  4.248 46.541 4.266 46.685 ;
     RECT  16.416 45.599 16.65 47.483 ;
     RECT  16.434 47.483 16.524 47.501 ;
     RECT  16.542 47.483 16.632 47.501 ;
    LAYER M4 ;
     RECT  0.084 4.176 0.425 4.2 ;
     RECT  0.06 4.2 0.425 4.32 ;
     RECT  0.084 4.32 0.425 4.344 ;
     RECT  0.06 4.344 0.425 4.464 ;
     RECT  0.084 4.464 0.425 4.488 ;
     RECT  0.06 4.488 0.425 4.608 ;
     RECT  0.084 4.608 0.425 4.632 ;
     RECT  0.06 4.632 0.425 4.752 ;
     RECT  0.084 4.752 0.425 4.776 ;
     RECT  0.06 4.776 0.425 4.896 ;
     RECT  0.084 4.896 0.425 4.92 ;
     RECT  0.06 4.92 0.425 5.04 ;
     RECT  0.084 5.04 0.425 5.064 ;
     RECT  0.06 5.064 0.425 5.184 ;
     RECT  0.084 5.184 0.425 5.208 ;
     RECT  0.06 5.208 0.425 5.328 ;
     RECT  0.084 5.328 0.425 5.352 ;
     RECT  0.06 5.352 0.425 5.472 ;
     RECT  0.084 5.472 0.425 5.496 ;
     RECT  0.06 5.496 0.425 5.616 ;
     RECT  0.084 5.616 0.425 5.64 ;
     RECT  0.06 5.64 0.425 5.76 ;
     RECT  0.084 5.76 0.425 5.784 ;
     RECT  0.06 5.784 0.425 5.904 ;
     RECT  0.084 5.904 0.425 5.928 ;
     RECT  0.06 5.928 0.425 6.048 ;
     RECT  0.084 6.048 0.425 6.072 ;
     RECT  0.06 6.072 0.425 6.192 ;
     RECT  0.084 6.192 0.425 6.216 ;
     RECT  0.06 6.216 0.425 6.336 ;
     RECT  0.084 6.336 0.425 6.36 ;
     RECT  0.06 6.36 0.425 6.48 ;
     RECT  0.084 6.48 0.425 6.504 ;
     RECT  0.06 6.504 0.425 6.624 ;
     RECT  0.084 6.624 0.425 6.648 ;
     RECT  0.06 6.648 0.425 6.768 ;
     RECT  0.084 6.768 0.425 6.792 ;
     RECT  0.06 6.792 0.425 6.912 ;
     RECT  0.084 6.912 0.425 6.936 ;
     RECT  0.06 6.936 0.425 7.056 ;
     RECT  0.084 7.056 0.425 7.08 ;
     RECT  0.06 7.08 0.425 7.2 ;
     RECT  0.084 7.2 0.425 7.224 ;
     RECT  0.06 7.224 0.425 7.344 ;
     RECT  0.084 7.344 0.425 7.368 ;
     RECT  0.06 7.368 0.425 7.488 ;
     RECT  0.084 7.488 0.425 7.512 ;
     RECT  0.06 7.512 0.425 7.632 ;
     RECT  0.084 7.632 0.425 7.656 ;
     RECT  0.06 7.656 0.425 7.776 ;
     RECT  0.084 7.776 0.425 7.8 ;
     RECT  0.06 7.8 0.425 7.92 ;
     RECT  0.084 7.92 0.425 7.944 ;
     RECT  0.06 7.944 0.425 8.064 ;
     RECT  0.084 8.064 0.425 8.088 ;
     RECT  0.06 8.088 0.425 8.208 ;
     RECT  0.084 8.208 0.425 8.232 ;
     RECT  0.06 8.232 0.425 8.352 ;
     RECT  0.084 8.352 0.425 8.376 ;
     RECT  0.06 8.376 0.425 8.496 ;
     RECT  0.084 8.496 0.425 8.52 ;
     RECT  0.06 8.52 0.425 8.64 ;
     RECT  0.084 8.64 0.425 8.664 ;
     RECT  0.06 8.664 0.425 8.784 ;
     RECT  0.084 8.784 0.425 8.808 ;
     RECT  0.06 8.808 0.425 8.928 ;
     RECT  0.084 8.928 0.425 8.952 ;
     RECT  0.06 8.952 0.425 9.072 ;
     RECT  0.084 9.072 0.425 9.096 ;
     RECT  0.06 9.096 0.425 9.216 ;
     RECT  0.084 9.216 0.425 9.24 ;
     RECT  0.06 9.24 0.425 9.36 ;
     RECT  0.084 9.36 0.425 9.384 ;
     RECT  0.06 9.384 0.425 9.504 ;
     RECT  0.084 9.504 0.425 9.528 ;
     RECT  0.06 9.528 0.425 9.648 ;
     RECT  0.084 9.648 0.425 9.672 ;
     RECT  0.06 9.672 0.425 9.792 ;
     RECT  0.084 9.792 0.425 9.816 ;
     RECT  0.06 9.816 0.425 9.936 ;
     RECT  0.084 9.936 0.425 9.96 ;
     RECT  0.06 9.96 0.425 10.08 ;
     RECT  0.084 10.08 0.425 10.104 ;
     RECT  0.06 10.104 0.425 10.224 ;
     RECT  0.084 10.224 0.425 10.248 ;
     RECT  0.06 10.248 0.425 10.368 ;
     RECT  0.084 10.368 0.425 10.392 ;
     RECT  0.06 10.392 0.425 10.512 ;
     RECT  0.084 10.512 0.425 10.536 ;
     RECT  0.06 10.536 0.425 10.656 ;
     RECT  0.084 10.656 0.425 10.68 ;
     RECT  0.06 10.68 0.425 10.8 ;
     RECT  0.084 10.8 0.425 10.824 ;
     RECT  0.06 10.824 0.425 10.944 ;
     RECT  0.084 10.944 0.425 10.968 ;
     RECT  0.06 10.968 0.425 11.088 ;
     RECT  0.084 11.088 0.425 11.112 ;
     RECT  0.06 11.112 0.425 11.232 ;
     RECT  0.084 11.232 0.425 11.256 ;
     RECT  0.06 11.256 0.425 11.376 ;
     RECT  0.084 11.376 0.425 11.4 ;
     RECT  0.06 11.4 0.425 11.52 ;
     RECT  0.084 11.52 0.425 11.544 ;
     RECT  0.06 11.544 0.425 11.664 ;
     RECT  0.084 11.664 0.425 11.688 ;
     RECT  0.06 11.688 0.425 11.808 ;
     RECT  0.084 11.808 0.425 11.832 ;
     RECT  0.06 11.832 0.425 11.952 ;
     RECT  0.084 11.952 0.425 11.976 ;
     RECT  0.06 11.976 0.425 12.096 ;
     RECT  0.084 12.096 0.425 12.12 ;
     RECT  0.06 12.12 0.425 12.24 ;
     RECT  0.084 12.24 0.425 12.264 ;
     RECT  0.06 12.264 0.425 12.384 ;
     RECT  0.084 12.384 0.425 12.408 ;
     RECT  0.06 12.408 0.425 12.528 ;
     RECT  0.084 12.528 0.425 12.552 ;
     RECT  0.06 12.552 0.425 12.672 ;
     RECT  0.084 12.672 0.425 12.696 ;
     RECT  0.06 12.696 0.425 12.816 ;
     RECT  0.084 12.816 0.425 12.84 ;
     RECT  0.06 12.84 0.425 12.96 ;
     RECT  0.084 12.96 0.425 12.984 ;
     RECT  0.06 12.984 0.425 13.104 ;
     RECT  0.084 13.104 0.425 13.128 ;
     RECT  0.06 13.128 0.425 13.248 ;
     RECT  0.084 13.248 0.425 13.272 ;
     RECT  0.06 13.272 0.425 13.392 ;
     RECT  0.084 13.392 0.425 13.416 ;
     RECT  0.06 13.416 0.425 13.536 ;
     RECT  0.084 13.536 0.425 13.56 ;
     RECT  0.06 13.56 0.425 13.68 ;
     RECT  0.084 13.68 0.425 13.704 ;
     RECT  0.06 13.704 0.425 13.824 ;
     RECT  0.084 13.824 0.425 13.848 ;
     RECT  0.06 13.848 0.425 13.968 ;
     RECT  0.084 13.968 0.425 13.992 ;
     RECT  0.06 13.992 0.425 14.112 ;
     RECT  0.084 14.112 0.425 14.136 ;
     RECT  0.06 14.136 0.425 14.256 ;
     RECT  0.084 14.256 0.425 14.28 ;
     RECT  0.06 14.28 0.425 14.4 ;
     RECT  0.084 14.4 0.425 14.424 ;
     RECT  0.06 14.424 0.425 14.544 ;
     RECT  0.084 14.544 0.425 14.568 ;
     RECT  0.06 14.568 0.425 14.688 ;
     RECT  0.084 14.688 0.425 14.712 ;
     RECT  0.06 14.712 0.425 14.832 ;
     RECT  0.084 14.832 0.425 14.856 ;
     RECT  0.06 14.856 0.425 14.976 ;
     RECT  0.084 14.976 0.425 15 ;
     RECT  0.06 15 0.425 15.12 ;
     RECT  0.084 15.12 0.425 15.144 ;
     RECT  0.06 15.144 0.425 15.264 ;
     RECT  0.084 15.264 0.425 15.288 ;
     RECT  0.06 15.288 0.425 15.408 ;
     RECT  0.084 15.408 0.425 15.432 ;
     RECT  0.06 15.432 0.425 15.552 ;
     RECT  0.084 15.552 0.425 15.576 ;
     RECT  0.06 15.576 0.425 15.696 ;
     RECT  0.084 15.696 0.425 15.72 ;
     RECT  0.06 15.72 0.425 15.84 ;
     RECT  0.084 15.84 0.425 15.864 ;
     RECT  0.06 15.864 0.425 15.984 ;
     RECT  0.084 15.984 0.425 16.008 ;
     RECT  0.06 16.008 0.425 16.128 ;
     RECT  0.084 16.128 0.425 16.152 ;
     RECT  0.06 16.152 0.425 16.272 ;
     RECT  0.084 16.272 0.425 16.296 ;
     RECT  0.06 16.296 0.425 16.416 ;
     RECT  0.084 16.416 0.425 16.44 ;
     RECT  0.06 16.44 0.425 16.56 ;
     RECT  0.084 16.56 0.425 16.584 ;
     RECT  0.06 16.584 0.425 16.704 ;
     RECT  0.084 16.704 0.425 16.728 ;
     RECT  0.06 16.728 0.425 16.848 ;
     RECT  0.084 16.848 0.425 16.872 ;
     RECT  0.06 16.872 0.425 16.992 ;
     RECT  0.084 16.992 0.425 17.016 ;
     RECT  0.06 17.016 0.425 17.136 ;
     RECT  0.084 17.136 0.425 17.16 ;
     RECT  0.06 17.16 0.425 17.28 ;
     RECT  0.084 17.28 0.425 17.304 ;
     RECT  0.06 17.304 0.425 17.424 ;
     RECT  0.084 17.424 0.425 17.448 ;
     RECT  0.06 17.448 0.425 17.568 ;
     RECT  0.084 17.568 0.425 17.592 ;
     RECT  0.06 17.592 0.425 17.712 ;
     RECT  0.084 17.712 0.425 17.736 ;
     RECT  0.06 17.736 0.425 17.856 ;
     RECT  0.084 17.856 0.425 17.88 ;
     RECT  0.06 17.88 0.425 18 ;
     RECT  0.084 18 0.425 18.024 ;
     RECT  0.06 18.024 0.425 18.144 ;
     RECT  0.084 18.144 0.425 18.168 ;
     RECT  0.06 18.168 0.425 18.288 ;
     RECT  0.084 18.288 0.425 18.312 ;
     RECT  0.06 18.312 0.425 18.432 ;
     RECT  0.084 18.432 0.425 18.456 ;
     RECT  0.06 18.456 0.425 18.576 ;
     RECT  0.084 18.576 0.425 18.6 ;
     RECT  0.06 18.6 0.425 18.72 ;
     RECT  0.084 18.72 0.425 18.744 ;
     RECT  0.06 18.744 0.425 18.864 ;
     RECT  0.084 18.864 0.425 18.888 ;
     RECT  0.06 18.888 0.425 19.008 ;
     RECT  0.084 19.008 0.425 19.032 ;
     RECT  0.06 19.032 0.425 19.152 ;
     RECT  0.084 19.152 0.425 19.176 ;
     RECT  0.06 19.176 0.425 19.296 ;
     RECT  0.084 19.296 0.425 19.32 ;
     RECT  0.06 19.32 0.425 19.44 ;
     RECT  0.084 19.44 0.425 19.464 ;
     RECT  0.06 19.464 0.425 19.584 ;
     RECT  0.084 19.584 0.425 19.608 ;
     RECT  0.06 19.608 0.425 19.728 ;
     RECT  0.084 19.728 0.425 19.752 ;
     RECT  0.06 19.752 0.425 19.872 ;
     RECT  0.084 19.872 0.425 19.896 ;
     RECT  0.06 19.896 0.425 20.016 ;
     RECT  0.084 20.016 0.425 20.04 ;
     RECT  0.06 20.04 0.425 20.16 ;
     RECT  0.084 20.16 0.425 20.184 ;
     RECT  0.06 20.184 0.425 20.304 ;
     RECT  0.084 20.304 0.425 20.328 ;
     RECT  0.06 20.328 0.425 20.448 ;
     RECT  0.084 20.448 0.425 20.472 ;
     RECT  0.06 20.472 0.425 20.592 ;
     RECT  0.084 20.592 0.425 20.616 ;
     RECT  0.06 20.616 0.425 20.736 ;
     RECT  0.084 20.736 0.425 20.76 ;
     RECT  0.06 20.76 0.425 20.88 ;
     RECT  0.084 20.88 0.425 20.904 ;
     RECT  0.06 20.904 0.425 21.024 ;
     RECT  0.084 21.024 0.425 21.048 ;
     RECT  0.06 21.048 0.425 21.168 ;
     RECT  0.084 21.168 0.425 21.192 ;
     RECT  0.06 21.192 0.425 21.312 ;
     RECT  0.084 21.312 0.425 21.336 ;
     RECT  0.06 21.336 0.425 21.456 ;
     RECT  0.084 21.456 0.425 21.48 ;
     RECT  0.06 21.48 0.425 21.6 ;
     RECT  0.084 21.6 0.425 21.624 ;
     RECT  0.06 21.624 0.425 21.744 ;
     RECT  0.084 21.744 0.425 21.768 ;
     RECT  0.06 21.768 0.425 21.888 ;
     RECT  0.084 21.888 0.425 21.912 ;
     RECT  0.06 21.912 0.425 22.032 ;
     RECT  0.084 22.032 0.425 22.056 ;
     RECT  0.06 22.056 0.425 22.176 ;
     RECT  0.084 22.176 0.425 22.2 ;
     RECT  0.06 22.2 0.425 22.32 ;
     RECT  0.084 22.32 0.425 22.344 ;
     RECT  0.06 22.344 0.425 22.464 ;
     RECT  0.084 22.464 0.425 22.488 ;
     RECT  0.06 22.488 0.425 22.608 ;
     RECT  0.084 22.608 0.425 22.632 ;
     RECT  0.06 22.632 0.425 22.752 ;
     RECT  0.084 22.752 0.425 22.776 ;
     RECT  0.06 22.776 0.425 22.896 ;
     RECT  0.084 22.896 0.425 22.92 ;
     RECT  0.06 22.92 0.425 23.04 ;
     RECT  0.084 23.04 0.425 23.064 ;
     RECT  0.06 23.064 0.425 23.184 ;
     RECT  0.084 23.184 0.425 23.208 ;
     RECT  0.06 23.208 0.425 23.328 ;
     RECT  0.084 23.328 0.425 23.352 ;
     RECT  0.06 23.352 0.425 23.472 ;
     RECT  0.084 23.472 0.425 23.496 ;
     RECT  0.06 23.496 0.425 23.616 ;
     RECT  0.084 23.616 0.425 23.64 ;
     RECT  0.06 23.64 0.425 23.76 ;
     RECT  0.084 23.76 0.425 23.784 ;
     RECT  0.06 23.784 0.425 23.904 ;
     RECT  0.084 23.904 0.425 23.928 ;
     RECT  0.06 23.928 0.425 24.048 ;
     RECT  0.084 24.048 0.425 24.072 ;
     RECT  0.06 24.072 0.425 24.192 ;
     RECT  0.084 24.192 0.425 24.216 ;
     RECT  0.06 24.216 0.425 24.336 ;
     RECT  0.084 24.336 0.425 24.36 ;
     RECT  0.06 24.36 0.425 24.48 ;
     RECT  0.084 24.48 0.425 24.504 ;
     RECT  0.06 24.504 0.425 24.624 ;
     RECT  0.084 24.624 0.425 24.648 ;
     RECT  0.06 24.648 0.425 24.768 ;
     RECT  0.084 24.768 0.425 24.792 ;
     RECT  0.06 24.792 0.425 24.912 ;
     RECT  0.084 24.912 0.425 24.936 ;
     RECT  0.06 24.936 0.425 25.056 ;
     RECT  0.084 25.056 0.425 25.08 ;
     RECT  0.06 25.08 0.425 25.2 ;
     RECT  0.084 25.2 0.425 25.224 ;
     RECT  0.06 25.224 0.425 25.344 ;
     RECT  0.084 25.344 0.425 25.368 ;
     RECT  0.06 25.368 0.425 25.488 ;
     RECT  0.084 25.488 0.425 25.512 ;
     RECT  0.06 25.512 0.425 25.632 ;
     RECT  0.084 25.632 0.425 25.656 ;
     RECT  0.06 25.656 0.425 25.776 ;
     RECT  0.084 25.776 0.425 25.8 ;
     RECT  0.06 25.8 0.425 25.92 ;
     RECT  0.084 25.92 0.425 25.944 ;
     RECT  0.06 25.944 0.425 26.064 ;
     RECT  0.084 26.064 0.425 26.088 ;
     RECT  0.06 26.088 0.425 26.208 ;
     RECT  0.084 26.208 0.425 26.232 ;
     RECT  0.06 26.232 0.425 26.352 ;
     RECT  0.084 26.352 0.425 26.376 ;
     RECT  0.06 26.376 0.425 26.496 ;
     RECT  0.084 26.496 0.425 26.52 ;
     RECT  0.06 26.52 0.425 26.64 ;
     RECT  0.084 26.64 0.425 26.664 ;
     RECT  0.06 26.664 0.425 26.784 ;
     RECT  0.084 26.784 0.425 26.808 ;
     RECT  0.06 26.808 0.425 26.928 ;
     RECT  0.084 26.928 0.425 26.952 ;
     RECT  0.06 26.952 0.425 27.072 ;
     RECT  0.084 27.072 0.425 27.096 ;
     RECT  0.06 27.096 0.425 27.216 ;
     RECT  0.084 27.216 0.425 27.24 ;
     RECT  0.06 27.24 0.425 27.36 ;
     RECT  0.084 27.36 0.425 27.384 ;
     RECT  0.06 27.384 0.425 27.504 ;
     RECT  0.084 27.504 0.425 27.528 ;
     RECT  0.06 27.528 0.425 27.648 ;
     RECT  0.084 27.648 0.425 27.672 ;
     RECT  0.06 27.672 0.425 27.792 ;
     RECT  0.084 27.792 0.425 27.816 ;
     RECT  0.06 27.816 0.425 27.936 ;
     RECT  0.084 27.936 0.425 27.96 ;
     RECT  0.06 27.96 0.425 28.08 ;
     RECT  0.084 28.08 0.425 28.104 ;
     RECT  0.06 28.104 0.425 28.224 ;
     RECT  0.084 28.224 0.425 28.248 ;
     RECT  0.06 28.248 0.425 28.368 ;
     RECT  0.084 28.368 0.425 28.392 ;
     RECT  0.06 28.392 0.425 28.512 ;
     RECT  0.084 28.512 0.425 28.536 ;
     RECT  0.06 28.536 0.425 28.656 ;
     RECT  0.084 28.656 0.425 28.68 ;
     RECT  0.06 28.68 0.425 28.8 ;
     RECT  0.084 28.8 0.425 28.824 ;
     RECT  0.06 28.824 0.425 28.944 ;
     RECT  0.084 28.944 0.425 28.968 ;
     RECT  0.06 28.968 0.425 29.088 ;
     RECT  0.084 29.088 0.425 29.112 ;
     RECT  0.06 29.112 0.425 29.232 ;
     RECT  0.084 29.232 0.425 29.256 ;
     RECT  0.06 29.256 0.425 29.376 ;
     RECT  0.084 29.376 0.425 29.4 ;
     RECT  0.06 29.4 0.425 29.52 ;
     RECT  0.084 29.52 0.425 29.544 ;
     RECT  0.06 29.544 0.425 29.664 ;
     RECT  0.084 29.664 0.425 29.688 ;
     RECT  0.06 29.688 0.425 29.808 ;
     RECT  0.084 29.808 0.425 29.832 ;
     RECT  0.06 29.832 0.425 29.952 ;
     RECT  0.084 29.952 0.425 29.976 ;
     RECT  0.06 29.976 0.425 30.096 ;
     RECT  0.084 30.096 0.425 30.12 ;
     RECT  0.06 30.12 0.425 30.24 ;
     RECT  0.084 30.24 0.425 30.264 ;
     RECT  0.06 30.264 0.425 30.384 ;
     RECT  0.084 30.384 0.425 30.408 ;
     RECT  0.06 30.408 0.425 30.528 ;
     RECT  0.084 30.528 0.425 30.552 ;
     RECT  0.06 30.552 0.425 30.672 ;
     RECT  0.084 30.672 0.425 30.696 ;
     RECT  0.06 30.696 0.425 30.816 ;
     RECT  0.084 30.816 0.425 30.84 ;
     RECT  0.06 30.84 0.425 30.96 ;
     RECT  0.084 30.96 0.425 30.984 ;
     RECT  0.06 30.984 0.425 31.104 ;
     RECT  0.084 31.104 0.425 31.128 ;
     RECT  0.06 31.128 0.425 31.248 ;
     RECT  0.084 31.248 0.425 31.272 ;
     RECT  0.06 31.272 0.425 31.392 ;
     RECT  0.084 31.392 0.425 31.416 ;
     RECT  0.06 31.416 0.425 31.536 ;
     RECT  0.084 31.536 0.425 31.56 ;
     RECT  0.06 31.56 0.425 31.68 ;
     RECT  0.084 31.68 0.425 31.704 ;
     RECT  0.06 31.704 0.425 31.824 ;
     RECT  0.084 31.824 0.425 31.848 ;
     RECT  0.06 31.848 0.425 31.968 ;
     RECT  0.084 31.968 0.425 31.992 ;
     RECT  0.06 31.992 0.425 32.112 ;
     RECT  0.084 32.112 0.425 32.136 ;
     RECT  0.06 32.136 0.425 32.256 ;
     RECT  0.084 32.256 0.425 32.28 ;
     RECT  0.06 32.28 0.425 32.4 ;
     RECT  0.084 32.4 0.425 32.424 ;
     RECT  0.06 32.424 0.425 32.544 ;
     RECT  0.084 32.544 0.425 32.568 ;
     RECT  0.06 32.568 0.425 32.688 ;
     RECT  0.084 32.688 0.425 32.712 ;
     RECT  0.06 32.712 0.425 32.832 ;
     RECT  0.084 32.832 0.425 32.856 ;
     RECT  0.06 32.856 0.425 32.976 ;
     RECT  0.084 32.976 0.425 33 ;
     RECT  0.06 33 0.425 33.12 ;
     RECT  0.084 33.12 0.425 33.144 ;
     RECT  0.06 33.144 0.425 33.264 ;
     RECT  0.084 33.264 0.425 33.288 ;
     RECT  0.06 33.288 0.425 33.408 ;
     RECT  0.084 33.408 0.425 33.432 ;
     RECT  0.06 33.432 0.425 33.552 ;
     RECT  0.084 33.552 0.425 33.576 ;
     RECT  0.06 33.576 0.425 33.696 ;
     RECT  0.084 33.696 0.425 33.72 ;
     RECT  0.06 33.72 0.425 33.84 ;
     RECT  0.084 33.84 0.425 33.864 ;
     RECT  0.06 33.864 0.425 33.984 ;
     RECT  0.084 33.984 0.425 34.008 ;
     RECT  0.06 34.008 0.425 34.128 ;
     RECT  0.084 34.128 0.425 34.152 ;
     RECT  0.06 34.152 0.425 34.272 ;
     RECT  0.084 34.272 0.425 34.296 ;
     RECT  0.06 34.296 0.425 34.416 ;
     RECT  0.084 34.416 0.425 34.44 ;
     RECT  0.06 34.44 0.425 34.56 ;
     RECT  0.084 34.56 0.425 34.584 ;
     RECT  0.06 34.584 0.425 34.704 ;
     RECT  0.084 34.704 0.425 34.728 ;
     RECT  0.06 34.728 0.425 34.848 ;
     RECT  0.084 34.848 0.425 34.872 ;
     RECT  0.06 34.872 0.425 34.992 ;
     RECT  0.084 34.992 0.425 35.016 ;
     RECT  0.06 35.016 0.425 35.136 ;
     RECT  0.084 35.136 0.425 35.16 ;
     RECT  0.06 35.16 0.425 35.28 ;
     RECT  0.084 35.28 0.425 35.304 ;
     RECT  0.06 35.304 0.425 35.424 ;
     RECT  0.084 35.424 0.425 35.448 ;
     RECT  0.06 35.448 0.425 35.568 ;
     RECT  0.084 35.568 0.425 35.592 ;
     RECT  0.06 35.592 0.425 35.712 ;
     RECT  0.084 35.712 0.425 35.736 ;
     RECT  0.06 35.736 0.425 35.856 ;
     RECT  0.084 35.856 0.425 35.88 ;
     RECT  0.06 35.88 0.425 36 ;
     RECT  0.084 36 0.425 36.024 ;
     RECT  0.06 36.024 0.425 36.144 ;
     RECT  0.084 36.144 0.425 36.168 ;
     RECT  0.06 36.168 0.425 36.288 ;
     RECT  0.084 36.288 0.425 36.312 ;
     RECT  0.06 36.312 0.425 36.432 ;
     RECT  0.084 36.432 0.425 36.456 ;
     RECT  0.06 36.456 0.425 36.576 ;
     RECT  0.084 36.576 0.425 36.6 ;
     RECT  0.06 36.6 0.425 36.72 ;
     RECT  0.084 36.72 0.425 36.744 ;
     RECT  0.06 36.744 0.425 36.864 ;
     RECT  0.084 36.864 0.425 36.888 ;
     RECT  0.06 36.888 0.425 37.008 ;
     RECT  0.084 37.008 0.425 37.032 ;
     RECT  0.06 37.032 0.425 37.152 ;
     RECT  0.084 37.152 0.425 37.176 ;
     RECT  0.06 37.176 0.425 37.296 ;
     RECT  0.084 37.296 0.425 37.32 ;
     RECT  0.06 37.32 0.425 37.44 ;
     RECT  0.084 37.44 0.425 37.464 ;
     RECT  0.06 37.464 0.425 37.584 ;
     RECT  0.084 37.584 0.425 37.608 ;
     RECT  0.06 37.608 0.425 37.728 ;
     RECT  0.084 37.728 0.425 37.752 ;
     RECT  0.06 37.752 0.425 37.872 ;
     RECT  0.084 37.872 0.425 37.896 ;
     RECT  0.06 37.896 0.425 38.016 ;
     RECT  0.084 38.016 0.425 38.04 ;
     RECT  0.06 38.04 0.425 38.16 ;
     RECT  0.084 38.16 0.425 38.184 ;
     RECT  0.06 38.184 0.425 38.304 ;
     RECT  0.084 38.304 0.425 38.328 ;
     RECT  0.06 38.328 0.425 38.448 ;
     RECT  0.084 38.448 0.425 38.472 ;
     RECT  0.06 38.472 0.425 38.592 ;
     RECT  0.084 38.592 0.425 38.616 ;
     RECT  0.06 38.616 0.425 38.736 ;
     RECT  0.084 38.736 0.425 38.76 ;
     RECT  0.06 38.76 0.425 38.88 ;
     RECT  0.084 38.88 0.425 38.904 ;
     RECT  0.06 38.904 0.425 39.024 ;
     RECT  0.084 39.024 0.425 39.048 ;
     RECT  0.06 39.048 0.425 39.168 ;
     RECT  0.084 39.168 0.425 39.192 ;
     RECT  0.06 39.192 0.425 39.312 ;
     RECT  0.084 39.312 0.425 39.336 ;
     RECT  0.06 39.336 0.425 39.456 ;
     RECT  0.084 39.456 0.425 39.48 ;
     RECT  0.06 39.48 0.425 39.6 ;
     RECT  0.084 39.6 0.425 39.624 ;
     RECT  0.06 39.624 0.425 39.744 ;
     RECT  0.084 39.744 0.425 39.768 ;
     RECT  0.06 39.768 0.425 39.888 ;
     RECT  0.084 39.888 0.425 39.912 ;
     RECT  0.06 39.912 0.425 40.032 ;
     RECT  0.084 40.032 0.425 40.056 ;
     RECT  0.06 40.056 0.425 40.176 ;
     RECT  0.084 40.176 0.425 40.2 ;
     RECT  0.06 40.2 0.425 40.32 ;
     RECT  0.084 40.32 0.425 40.344 ;
     RECT  0.06 40.344 0.425 40.464 ;
     RECT  0.084 40.464 0.425 40.488 ;
     RECT  0.06 40.488 0.425 40.608 ;
     RECT  0.084 40.608 0.425 40.632 ;
     RECT  0.06 40.632 0.425 40.752 ;
     RECT  0.084 40.752 0.425 40.776 ;
     RECT  0.06 40.776 0.425 40.896 ;
     RECT  0.084 40.896 0.425 40.92 ;
     RECT  0.06 40.92 0.425 41.04 ;
     RECT  0.084 41.04 0.425 41.064 ;
     RECT  0.06 41.064 0.425 41.184 ;
     RECT  0.084 41.184 0.425 41.208 ;
     RECT  0.06 41.208 0.425 41.328 ;
     RECT  0.084 41.328 0.425 41.352 ;
     RECT  0.06 41.352 0.425 41.472 ;
     RECT  0.084 41.472 0.425 41.496 ;
     RECT  0.06 41.496 0.425 41.616 ;
     RECT  0.084 41.616 0.425 41.64 ;
     RECT  0.06 41.64 0.425 41.76 ;
     RECT  0.084 41.76 0.425 41.784 ;
     RECT  0.06 41.784 0.425 41.904 ;
     RECT  0.084 41.904 0.425 41.928 ;
     RECT  0.06 41.928 0.425 42.048 ;
     RECT  0.084 42.048 0.425 42.072 ;
     RECT  0.06 42.072 0.425 42.192 ;
     RECT  0.084 42.192 0.425 42.216 ;
     RECT  0.06 42.216 0.425 42.336 ;
     RECT  0.084 42.336 0.425 42.36 ;
     RECT  0.06 42.36 0.425 42.48 ;
     RECT  0.084 42.48 0.425 42.504 ;
     RECT  0.06 42.504 0.425 42.624 ;
     RECT  0.084 42.624 0.425 42.648 ;
     RECT  0.06 42.648 0.425 42.768 ;
     RECT  0.084 42.768 0.425 42.792 ;
     RECT  0.06 42.792 0.425 42.912 ;
     RECT  0.084 42.912 0.425 42.936 ;
     RECT  0.06 42.936 0.425 43.056 ;
     RECT  0.084 43.056 0.425 43.08 ;
     RECT  0.06 43.08 0.425 43.2 ;
     RECT  0.084 43.2 0.425 43.224 ;
     RECT  0.06 43.224 0.425 43.344 ;
     RECT  0.084 43.344 0.425 43.368 ;
     RECT  0.06 43.368 0.425 43.488 ;
     RECT  0.084 43.488 0.425 43.512 ;
     RECT  0.06 43.512 0.425 43.632 ;
     RECT  0.084 43.632 0.425 43.656 ;
     RECT  0.06 43.656 0.425 43.776 ;
     RECT  0.084 43.776 0.425 43.8 ;
     RECT  0.06 43.8 0.425 43.92 ;
     RECT  0.084 43.92 0.425 43.944 ;
     RECT  0.06 43.944 0.425 44.064 ;
     RECT  0.084 44.064 0.425 44.088 ;
     RECT  0.06 44.088 0.425 44.208 ;
     RECT  0.084 44.208 0.425 44.232 ;
     RECT  0.06 44.232 0.425 44.352 ;
     RECT  0.084 44.352 0.425 44.376 ;
     RECT  0.06 44.376 0.425 44.496 ;
     RECT  0.084 44.496 0.425 44.52 ;
     RECT  0.06 44.52 0.425 44.64 ;
     RECT  0.084 44.64 0.425 44.664 ;
     RECT  0.06 44.664 0.425 44.784 ;
     RECT  0.084 44.784 0.425 44.808 ;
     RECT  0.06 44.808 0.425 44.928 ;
     RECT  0.084 44.928 0.425 44.952 ;
     RECT  0.06 44.952 0.425 45.072 ;
     RECT  0.084 45.072 0.425 45.096 ;
     RECT  0.06 45.096 0.425 45.216 ;
     RECT  0.084 45.216 0.425 45.24 ;
     RECT  0.06 45.24 0.425 45.36 ;
     RECT  0.084 45.36 0.425 45.384 ;
     RECT  0.06 45.384 0.425 45.504 ;
     RECT  0.084 45.504 0.425 45.528 ;
     RECT  0.06 45.528 0.425 45.648 ;
     RECT  0.084 45.648 0.425 45.672 ;
     RECT  0.06 45.672 0.425 45.792 ;
     RECT  0.084 45.792 0.425 45.816 ;
     RECT  0.06 45.816 0.425 45.936 ;
     RECT  0.084 45.936 0.425 45.96 ;
     RECT  0.06 45.96 0.425 46.08 ;
     RECT  0.084 46.08 0.425 46.104 ;
     RECT  0.06 46.104 0.425 46.224 ;
     RECT  0.084 46.224 0.425 46.248 ;
     RECT  0.06 46.248 0.425 46.368 ;
     RECT  0.084 46.368 0.425 46.392 ;
     RECT  0.06 46.392 0.425 46.512 ;
     RECT  0.084 46.512 0.425 46.536 ;
     RECT  0.06 46.536 0.425 46.656 ;
     RECT  0.084 46.656 0.425 46.68 ;
     RECT  0.425 4.176 0.497 22.776 ;
     RECT  0.497 4.176 2.408 22.488 ;
     RECT  0.425 23.76 2.408 46.68 ;
     RECT  2.408 2.148 2.512 46.68 ;
     RECT  2.512 2.418 2.704 46.68 ;
     RECT  2.704 3.408 2.765 18.792 ;
     RECT  2.704 26.208 2.765 27.96 ;
     RECT  2.704 20.064 3.053 23.112 ;
     RECT  2.765 13.632 3.269 18.792 ;
     RECT  2.765 3.408 3.347 12.552 ;
     RECT  2.704 28.992 3.413 46.68 ;
     RECT  2.704 24.192 3.769 25.08 ;
     RECT  2.765 26.208 3.769 27.864 ;
     RECT  3.053 23.088 3.805 23.112 ;
     RECT  3.769 24.192 3.805 27.864 ;
     RECT  3.269 13.68 3.917 18.792 ;
     RECT  3.413 44.976 3.989 46.68 ;
     RECT  3.347 6.048 4.237 12.552 ;
     RECT  3.917 13.68 4.237 18.744 ;
     RECT  3.989 46.512 4.277 46.68 ;
     RECT  3.347 3.408 4.453 5.064 ;
     RECT  4.237 6.048 4.453 18.744 ;
     RECT  3.805 23.088 4.453 27.864 ;
     RECT  3.413 28.992 4.453 43.416 ;
     RECT  4.453 23.088 4.489 43.416 ;
     RECT  4.277 46.512 4.853 46.536 ;
     RECT  3.053 20.064 4.885 22.056 ;
     RECT  4.489 23.088 4.885 43.56 ;
     RECT  4.453 3.408 4.921 18.744 ;
     RECT  4.921 3.408 5.108 18.84 ;
     RECT  4.885 20.064 5.108 43.56 ;
     RECT  3.989 44.976 5.108 45 ;
     RECT  5.108 2.148 5.212 45.372 ;
     RECT  5.212 2.418 5.404 45.102 ;
     RECT  5.404 3.168 5.753 12.552 ;
     RECT  5.404 13.68 5.869 45 ;
     RECT  5.869 13.68 5.891 43.272 ;
     RECT  5.753 3.168 6.469 7.368 ;
     RECT  5.753 8.64 6.613 12.552 ;
     RECT  5.891 13.68 6.613 19.368 ;
     RECT  5.891 20.352 6.833 43.272 ;
     RECT  6.613 8.64 7.657 19.368 ;
     RECT  6.469 2.832 7.808 7.368 ;
     RECT  7.657 8.544 7.808 19.368 ;
     RECT  6.833 20.352 7.808 43.176 ;
     RECT  5.869 44.304 7.808 45 ;
     RECT  7.808 2.148 7.912 45.372 ;
     RECT  7.912 2.418 8.104 45.102 ;
     RECT  8.104 2.592 8.669 45 ;
     RECT  8.669 2.592 10.213 23.4 ;
     RECT  8.669 24.672 10.213 45 ;
     RECT  10.213 2.592 10.508 45 ;
     RECT  10.508 2.148 10.612 45.372 ;
     RECT  10.612 2.418 10.804 45.102 ;
     RECT  10.804 2.592 10.937 43.56 ;
     RECT  10.937 2.592 10.973 27.912 ;
     RECT  10.973 20.064 11.081 27.912 ;
     RECT  10.973 2.592 11.405 18.504 ;
     RECT  11.081 23.568 11.513 27.912 ;
     RECT  10.937 29.04 11.585 43.56 ;
     RECT  11.405 2.592 11.729 8.808 ;
     RECT  11.585 30.096 11.74 43.56 ;
     RECT  11.405 9.84 12.265 18.504 ;
     RECT  12.265 9.84 12.409 18.792 ;
     RECT  11.081 20.064 12.409 22.344 ;
     RECT  11.513 24.192 12.553 27.912 ;
     RECT  12.553 23.664 12.733 27.912 ;
     RECT  11.585 29.04 12.733 29.064 ;
     RECT  10.804 44.976 12.841 45 ;
     RECT  11.729 3.84 13.093 8.808 ;
     RECT  12.409 9.84 13.093 22.344 ;
     RECT  11.729 2.592 13.208 2.856 ;
     RECT  13.093 3.84 13.208 22.344 ;
     RECT  12.733 23.664 13.208 29.064 ;
     RECT  11.74 30.096 13.208 43.128 ;
     RECT  12.841 44.448 13.208 45 ;
     RECT  13.208 2.148 13.312 45.372 ;
     RECT  13.312 2.418 13.504 45.102 ;
     RECT  13.504 2.592 13.529 2.856 ;
     RECT  13.504 23.376 13.9 39.768 ;
     RECT  13.504 40.896 14.141 43.176 ;
     RECT  13.504 44.448 14.533 45 ;
     RECT  13.529 2.64 14.581 2.856 ;
     RECT  13.504 3.84 14.581 11.832 ;
     RECT  14.141 40.896 14.717 43.128 ;
     RECT  13.504 13.152 14.785 18.504 ;
     RECT  13.504 19.632 14.785 22.344 ;
     RECT  14.581 2.64 14.821 11.832 ;
     RECT  14.785 13.152 14.821 22.344 ;
     RECT  13.9 23.376 14.821 31.8 ;
     RECT  14.533 44.448 14.821 45.048 ;
     RECT  14.821 13.152 15.26 31.8 ;
     RECT  13.9 32.784 15.26 39.768 ;
     RECT  14.717 40.944 15.356 43.128 ;
     RECT  14.821 44.352 15.356 45.048 ;
     RECT  14.821 2.544 15.469 12.024 ;
     RECT  15.26 13.152 15.469 39.768 ;
     RECT  15.356 40.944 15.757 45.048 ;
     RECT  15.469 2.544 15.908 39.768 ;
     RECT  15.757 40.944 15.908 45.192 ;
     RECT  15.908 2.148 16.012 45.372 ;
     RECT  16.012 2.418 16.204 45.192 ;
     RECT  16.204 40.944 16.355 45.192 ;
     RECT  16.204 32.784 16.517 39.768 ;
     RECT  16.204 19.872 16.661 31.8 ;
     RECT  16.517 32.784 16.805 39.624 ;
     RECT  16.204 2.496 16.931 18.792 ;
     RECT  16.661 19.872 17.021 22.872 ;
     RECT  17.021 20.112 17.057 22.872 ;
     RECT  16.931 2.496 17.129 11.736 ;
     RECT  16.661 24.144 17.26 31.8 ;
     RECT  17.26 28.8 17.273 31.8 ;
     RECT  16.805 39.264 17.309 39.624 ;
     RECT  17.273 30.048 17.917 31.8 ;
     RECT  16.805 32.784 17.917 38.232 ;
     RECT  17.057 20.112 18.061 22.344 ;
     RECT  17.26 24.144 18.061 27.672 ;
     RECT  16.355 40.944 18.061 45 ;
     RECT  18.061 20.112 18.169 27.672 ;
     RECT  17.273 29.04 18.313 29.064 ;
     RECT  18.169 19.776 18.325 27.672 ;
     RECT  18.313 28.752 18.325 29.064 ;
     RECT  17.917 30.048 18.349 38.232 ;
     RECT  17.309 39.312 18.349 39.624 ;
     RECT  17.129 2.544 18.608 11.736 ;
     RECT  16.931 12.816 18.608 18.792 ;
     RECT  18.325 19.776 18.608 29.064 ;
     RECT  18.349 30.048 18.608 39.624 ;
     RECT  18.061 40.656 18.608 45 ;
     RECT  18.608 2.148 18.712 45.372 ;
     RECT  18.712 2.148 18.904 45.102 ;
     RECT  18.904 2.148 18.989 39.624 ;
     RECT  18.853 0.336 19.429 0.36 ;
     RECT  19.429 0.24 19.513 0.36 ;
     RECT  19.513 0.336 19.523 0.36 ;
     RECT  19.573 0.576 19.657 0.6 ;
     RECT  18.989 1.728 19.763 39.624 ;
     RECT  19.763 2.592 19.937 39.624 ;
     RECT  19.937 20.4 20.041 39.624 ;
     RECT  18.904 40.656 20.041 45 ;
     RECT  20.041 20.4 20.045 45 ;
     RECT  20.045 39.216 20.297 45 ;
     RECT  20.297 39.216 20.341 43.368 ;
     RECT  19.937 2.592 20.905 18.984 ;
     RECT  20.045 20.4 21.157 38.232 ;
     RECT  20.341 39.216 21.157 43.128 ;
     RECT  21.157 20.4 21.193 43.128 ;
     RECT  20.905 2.592 21.308 19.128 ;
     RECT  21.193 20.352 21.308 43.128 ;
     RECT  20.297 44.352 21.308 45 ;
     RECT  21.308 2.148 21.412 45.372 ;
     RECT  21.412 2.418 21.604 45.102 ;
     RECT  21.604 44.112 21.881 45 ;
     RECT  21.604 2.592 21.989 29.064 ;
     RECT  21.989 2.592 22.349 18.84 ;
     RECT  21.604 30.096 22.643 43.128 ;
     RECT  22.349 2.592 22.811 11.976 ;
     RECT  22.811 2.544 22.853 11.976 ;
     RECT  22.643 40.944 22.921 43.128 ;
     RECT  21.881 44.592 22.921 45 ;
     RECT  22.853 2.544 22.925 11.832 ;
     RECT  22.349 13.152 23.317 18.84 ;
     RECT  21.989 20.352 23.317 29.064 ;
     RECT  22.643 30.096 23.653 39.528 ;
     RECT  22.921 40.944 23.653 45 ;
     RECT  22.925 2.544 24.008 11.736 ;
     RECT  23.317 13.152 24.008 29.064 ;
     RECT  23.653 30.096 24.008 45 ;
     RECT  24.008 2.148 24.112 45.372 ;
     RECT  24.112 2.418 24.304 45.102 ;
     RECT  24.304 30.048 24.365 45 ;
     RECT  24.365 30.048 24.545 43.368 ;
     RECT  24.545 30.096 24.689 43.368 ;
     RECT  24.689 30.096 24.761 43.32 ;
     RECT  24.761 32.784 25.121 43.32 ;
     RECT  24.304 2.544 25.585 29.064 ;
     RECT  24.761 30.096 25.585 31.8 ;
     RECT  25.585 2.544 25.621 31.8 ;
     RECT  25.621 2.496 25.733 31.8 ;
     RECT  25.121 32.784 26.197 43.224 ;
     RECT  26.197 32.784 26.377 43.368 ;
     RECT  24.365 44.448 26.377 45 ;
     RECT  25.733 2.496 26.708 29.064 ;
     RECT  25.733 30.048 26.708 31.8 ;
     RECT  26.377 32.784 26.708 45 ;
     RECT  26.708 2.148 26.812 45.372 ;
     RECT  26.812 2.418 27.004 45.102 ;
     RECT  27.004 26.544 27.173 27.96 ;
     RECT  27.004 13.056 27.353 25.56 ;
     RECT  27.004 30.096 27.461 45 ;
     RECT  27.461 32.784 27.713 45 ;
     RECT  27.173 26.544 28.249 27.672 ;
     RECT  27.004 29.04 28.249 29.064 ;
     RECT  27.004 2.544 28.289 11.976 ;
     RECT  27.353 20.928 28.321 25.56 ;
     RECT  27.713 44.976 28.321 45 ;
     RECT  27.353 13.056 28.429 19.08 ;
     RECT  28.321 20.304 28.429 25.56 ;
     RECT  27.461 30.096 28.429 31.8 ;
     RECT  27.713 32.784 28.429 43.416 ;
     RECT  28.249 26.544 28.501 29.064 ;
     RECT  28.429 30.096 28.717 43.416 ;
     RECT  28.717 30.096 28.933 43.704 ;
     RECT  28.289 2.544 29.408 11.832 ;
     RECT  28.429 13.056 29.408 25.56 ;
     RECT  28.501 26.544 29.408 29.112 ;
     RECT  28.933 30.096 29.408 43.896 ;
     RECT  28.321 44.976 29.408 45.288 ;
     RECT  29.408 2.148 29.512 45.372 ;
     RECT  29.512 2.418 29.704 45.288 ;
     RECT  29.704 39.312 29.765 45.288 ;
     RECT  29.704 2.544 30.323 27.912 ;
     RECT  30.323 5.232 30.737 27.912 ;
     RECT  30.737 19.872 30.809 27.912 ;
     RECT  29.704 30.048 31.061 38.232 ;
     RECT  31.061 32.784 31.165 38.232 ;
     RECT  29.765 39.312 31.165 45 ;
     RECT  30.737 5.232 31.705 18.84 ;
     RECT  30.809 19.872 31.705 27.768 ;
     RECT  29.704 29.04 31.957 29.064 ;
     RECT  31.061 30.048 31.957 31.8 ;
     RECT  30.323 2.544 32.108 4.2 ;
     RECT  31.705 5.232 32.108 27.768 ;
     RECT  31.957 29.04 32.108 31.8 ;
     RECT  31.165 32.784 32.108 45 ;
     RECT  32.108 2.148 32.212 45.372 ;
     RECT  32.212 2.352 32.404 45.102 ;
     RECT  32.404 32.784 32.537 43.32 ;
     RECT  32.404 18 32.867 29.112 ;
     RECT  32.867 20.112 33.059 29.112 ;
     RECT  33.059 20.112 33.113 29.064 ;
     RECT  32.404 2.352 33.181 16.872 ;
     RECT  32.537 32.784 33.257 42.792 ;
     RECT  33.181 2.304 33.397 16.872 ;
     RECT  32.867 18 33.397 19.128 ;
     RECT  32.404 44.976 33.469 45 ;
     RECT  33.397 2.304 33.473 19.128 ;
     RECT  33.257 32.784 33.683 38.184 ;
     RECT  32.404 30.096 33.733 31.8 ;
     RECT  33.683 32.784 33.733 37.992 ;
     RECT  33.257 39.264 34.009 42.792 ;
     RECT  33.469 44.448 34.009 45 ;
     RECT  33.473 13.008 34.117 19.128 ;
     RECT  33.113 20.112 34.117 23.16 ;
     RECT  33.113 24.144 34.604 29.064 ;
     RECT  33.733 30.096 34.604 37.992 ;
     RECT  34.117 13.008 34.765 23.16 ;
     RECT  34.604 24.144 34.765 37.992 ;
     RECT  33.473 2.304 34.808 12.024 ;
     RECT  34.765 13.008 34.808 37.992 ;
     RECT  34.009 39.264 34.808 45 ;
     RECT  34.808 2.148 34.912 45.372 ;
     RECT  34.912 2.304 35.104 45.102 ;
     RECT  35.104 30.096 35.237 39.624 ;
     RECT  35.104 40.944 35.273 44.472 ;
     RECT  35.237 30.096 35.525 39.288 ;
     RECT  35.104 2.304 35.597 7.752 ;
     RECT  35.597 2.496 35.633 7.752 ;
     RECT  35.104 9.072 35.849 29.064 ;
     RECT  35.273 40.944 36.101 44.376 ;
     RECT  35.849 9.312 36.361 29.064 ;
     RECT  36.361 9.312 36.467 23.16 ;
     RECT  36.101 40.944 36.565 43.704 ;
     RECT  36.467 9.312 36.817 11.784 ;
     RECT  35.525 39.264 37.141 39.288 ;
     RECT  35.525 30.096 37.381 38.28 ;
     RECT  37.141 39.264 37.381 39.384 ;
     RECT  37.381 30.096 37.465 39.384 ;
     RECT  36.565 40.608 37.465 43.704 ;
     RECT  35.633 2.544 37.508 7.752 ;
     RECT  36.817 8.736 37.508 11.784 ;
     RECT  36.467 13.008 37.508 23.16 ;
     RECT  36.361 24.144 37.508 29.064 ;
     RECT  37.465 30.096 37.508 43.704 ;
     RECT  37.105 44.928 37.508 44.952 ;
     RECT  37.508 2.148 37.612 45.372 ;
     RECT  37.612 2.418 37.804 45.102 ;
     RECT  37.804 40.032 38.081 40.056 ;
     RECT  37.804 2.544 38.117 17.16 ;
     RECT  37.804 44.736 38.225 44.952 ;
     RECT  37.804 41.088 38.333 43.608 ;
     RECT  38.117 2.544 38.435 8.328 ;
     RECT  38.333 41.088 38.585 43.032 ;
     RECT  38.225 44.736 38.621 44.76 ;
     RECT  38.117 9.312 38.627 17.16 ;
     RECT  38.627 13.056 38.773 17.16 ;
     RECT  37.804 18.192 38.773 29.064 ;
     RECT  38.773 13.056 38.797 29.064 ;
     RECT  37.804 30.096 38.797 38.952 ;
     RECT  38.627 9.312 38.873 11.976 ;
     RECT  38.797 13.056 38.945 38.952 ;
     RECT  38.945 33.36 38.965 38.952 ;
     RECT  38.797 39.984 38.965 40.008 ;
     RECT  38.965 33.36 39.161 40.008 ;
     RECT  38.435 7.104 39.445 8.328 ;
     RECT  38.873 9.312 39.445 11.784 ;
     RECT  38.435 2.544 39.553 6.072 ;
     RECT  39.445 7.104 39.553 11.784 ;
     RECT  39.161 35.28 39.841 40.008 ;
     RECT  38.585 41.088 39.841 42.984 ;
     RECT  39.553 2.544 40.208 11.784 ;
     RECT  38.945 13.056 40.208 32.328 ;
     RECT  39.161 33.36 40.208 33.96 ;
     RECT  39.841 35.28 40.208 42.984 ;
     RECT  39.337 44.448 40.208 44.472 ;
     RECT  40.208 2.148 40.312 45.372 ;
     RECT  40.312 2.418 40.504 45.102 ;
     RECT  40.504 2.544 40.529 5.832 ;
     RECT  40.504 29.616 40.673 45 ;
     RECT  40.529 2.544 40.709 5.784 ;
     RECT  40.673 29.616 40.853 31.992 ;
     RECT  40.853 29.616 40.889 29.64 ;
     RECT  40.673 32.976 40.997 45 ;
     RECT  40.997 40.512 41.141 45 ;
     RECT  40.997 32.976 41.285 39.384 ;
     RECT  40.504 8.832 41.393 23.16 ;
     RECT  41.285 38.784 41.411 39.384 ;
     RECT  41.141 41.184 41.501 45 ;
     RECT  41.756 28.896 41.843 28.92 ;
     RECT  40.853 30.816 41.893 31.992 ;
     RECT  41.285 32.976 41.893 37.656 ;
     RECT  41.393 15.84 41.897 23.16 ;
     RECT  40.504 24.144 41.897 27.912 ;
     RECT  40.709 2.544 42.001 5.544 ;
     RECT  41.893 30.816 42.037 37.656 ;
     RECT  42.037 30.768 42.109 37.656 ;
     RECT  42.001 2.544 42.133 5.832 ;
     RECT  40.504 6.816 42.133 7.752 ;
     RECT  41.411 39.36 42.145 39.384 ;
     RECT  42.133 2.544 42.217 7.752 ;
     RECT  41.393 8.832 42.217 14.76 ;
     RECT  41.501 41.184 42.325 42.168 ;
     RECT  42.109 30.72 42.541 37.656 ;
     RECT  41.897 18.72 42.577 23.16 ;
     RECT  41.897 24.144 42.577 27.528 ;
     RECT  42.325 40.896 42.793 42.168 ;
     RECT  42.793 40.704 42.865 42.168 ;
     RECT  42.217 2.544 42.901 14.76 ;
     RECT  41.897 15.84 42.901 17.64 ;
     RECT  42.901 2.544 42.908 17.64 ;
     RECT  42.577 18.72 42.908 27.528 ;
     RECT  42.541 29.28 42.908 29.304 ;
     RECT  42.541 30.72 42.908 38.184 ;
     RECT  42.145 39.36 42.908 39.624 ;
     RECT  42.865 40.608 42.908 42.168 ;
     RECT  41.501 43.632 42.908 43.656 ;
     RECT  41.501 44.976 42.908 45 ;
     RECT  42.908 2.148 43.012 45.372 ;
     RECT  43.012 2.148 43.204 45.102 ;
     RECT  43.204 44.976 43.373 45 ;
     RECT  43.204 28.464 43.379 29.304 ;
     RECT  43.204 40.896 43.481 42.744 ;
     RECT  43.204 9.312 43.619 19.512 ;
     RECT  43.204 2.148 43.621 2.616 ;
     RECT  43.204 3.696 43.805 7.752 ;
     RECT  43.619 9.312 43.805 14.856 ;
     RECT  43.481 41.184 43.805 42.744 ;
     RECT  43.805 42.72 43.841 42.744 ;
     RECT  43.204 21.216 43.859 27.384 ;
     RECT  43.859 25.536 43.877 27.384 ;
     RECT  43.877 26.736 43.885 27.384 ;
     RECT  43.805 3.696 43.949 6.312 ;
     RECT  43.859 21.216 43.949 24.168 ;
     RECT  43.877 25.536 43.949 25.752 ;
     RECT  43.949 22.704 43.955 24.168 ;
     RECT  43.949 21.216 43.985 21.672 ;
     RECT  43.204 35.28 43.993 39.72 ;
     RECT  43.805 7.728 44.021 7.752 ;
     RECT  43.885 26.736 44.093 26.904 ;
     RECT  43.985 21.216 44.129 21.24 ;
     RECT  43.993 35.28 44.201 38.28 ;
     RECT  43.619 17.664 44.237 19.512 ;
     RECT  44.093 26.832 44.237 26.904 ;
     RECT  43.204 30.912 44.237 34.248 ;
     RECT  43.955 22.8 44.453 24.168 ;
     RECT  44.237 17.664 44.483 18.792 ;
     RECT  44.341 20.256 44.483 20.28 ;
     RECT  43.949 3.696 44.489 5.784 ;
     RECT  44.201 35.28 44.489 37.608 ;
     RECT  44.237 34.224 44.521 34.248 ;
     RECT  44.489 35.28 44.521 37.08 ;
     RECT  43.993 39.696 44.561 39.72 ;
     RECT  44.453 24.096 44.597 24.168 ;
     RECT  43.621 1.728 44.665 2.616 ;
     RECT  44.665 1.152 44.881 2.616 ;
     RECT  44.876 27.888 44.917 27.912 ;
     RECT  43.805 14.832 45.133 14.856 ;
     RECT  43.619 15.84 45.133 16.344 ;
     RECT  44.881 7.92 45.169 7.944 ;
     RECT  43.805 9.312 45.313 13.368 ;
     RECT  45.169 7.632 45.349 7.944 ;
     RECT  45.349 6.816 45.493 7.944 ;
     RECT  45.313 9.312 45.493 13.704 ;
     RECT  44.881 1.152 45.608 2.856 ;
     RECT  44.489 4.656 45.608 5.784 ;
     RECT  45.493 6.816 45.608 13.704 ;
     RECT  45.133 14.832 45.608 16.344 ;
     RECT  44.483 17.664 45.608 18.216 ;
     RECT  45.277 19.248 45.608 19.272 ;
     RECT  44.989 22.464 45.608 22.488 ;
     RECT  44.597 24.096 45.608 24.12 ;
     RECT  43.949 25.728 45.608 25.752 ;
     RECT  44.237 26.832 45.608 26.856 ;
     RECT  44.917 27.888 45.608 29.112 ;
     RECT  44.237 30.912 45.608 32.808 ;
     RECT  44.521 34.224 45.608 37.08 ;
     RECT  45.061 38.736 45.608 38.76 ;
     RECT  43.805 41.232 45.608 41.688 ;
     RECT  45.608 1.152 45.712 45.372 ;
     RECT  45.712 1.152 45.904 45.102 ;
     RECT  45.904 18 45.929 18.216 ;
     RECT  45.904 7.92 46.001 12.504 ;
     RECT  45.904 25.008 46.019 25.752 ;
     RECT  45.904 31.776 46.019 32.472 ;
     RECT  45.904 34.08 46.019 34.392 ;
     RECT  46.001 7.92 46.037 9.528 ;
     RECT  46.037 8.4 46.115 9.528 ;
     RECT  46.001 11.136 46.115 12.504 ;
     RECT  45.904 13.68 46.115 16.44 ;
     RECT  46.115 11.136 46.181 11.784 ;
     RECT  45.904 22.464 46.181 22.488 ;
     RECT  45.904 19.248 46.289 19.272 ;
     RECT  46.019 32.016 46.289 32.472 ;
     RECT  46.115 13.68 46.361 14.232 ;
     RECT  46.181 11.76 46.397 11.784 ;
     RECT  46.115 15.312 46.397 16.44 ;
     RECT  45.904 36 46.397 37.608 ;
     RECT  45.904 41.424 46.397 41.928 ;
     RECT  45.904 26.736 46.433 28.344 ;
     RECT  45.904 5.808 46.541 5.832 ;
     RECT  45.904 6.816 46.577 6.84 ;
     RECT  45.904 1.152 46.613 4.824 ;
     RECT  45.929 18 46.649 18.024 ;
     RECT  46.433 26.736 46.685 27.672 ;
     RECT  46.685 26.736 46.721 26.76 ;
     RECT  46.289 32.448 46.793 32.472 ;
     RECT  46.397 37.008 46.829 37.608 ;
     RECT  45.904 38.736 47.009 39.624 ;
     RECT  46.829 37.584 47.045 37.608 ;
     RECT  46.613 1.152 47.081 3.912 ;
     RECT  46.115 8.496 47.189 9.528 ;
     RECT  47.189 9.312 47.293 9.528 ;
     RECT  46.019 25.008 47.293 25.032 ;
     RECT  47.077 26.352 47.293 26.376 ;
     RECT  46.397 15.312 47.333 15.336 ;
     RECT  46.397 16.32 47.333 16.44 ;
     RECT  46.019 34.08 47.333 34.104 ;
     RECT  46.397 41.904 47.333 41.928 ;
     RECT  47.293 9.312 47.413 9.672 ;
     RECT  47.081 1.152 48.308 2.856 ;
     RECT  47.081 3.888 48.308 3.912 ;
     RECT  47.221 5.664 48.308 5.688 ;
     RECT  47.413 9.312 48.308 10.872 ;
     RECT  46.361 14.208 48.308 14.232 ;
     RECT  47.333 16.32 48.308 16.344 ;
     RECT  47.293 25.008 48.308 26.376 ;
     RECT  46.397 36 48.308 36.024 ;
     RECT  47.009 39.168 48.308 39.624 ;
     RECT  48.308 1.152 48.412 45.372 ;
     RECT  48.412 1.152 48.604 45.102 ;
     RECT  48.604 2.736 49.025 2.856 ;
     RECT  48.604 37.728 49.597 38.616 ;
     RECT  48.604 12.528 49.705 12.84 ;
     RECT  49.633 15.84 49.705 15.864 ;
     RECT  48.604 3.888 49.777 3.912 ;
     RECT  49.669 4.896 49.777 4.92 ;
     RECT  48.604 19.296 49.777 19.32 ;
     RECT  48.604 26.352 49.777 26.376 ;
     RECT  48.604 36.576 49.777 36.6 ;
     RECT  49.669 40.176 49.813 40.632 ;
     RECT  49.777 24.48 49.849 24.504 ;
     RECT  48.604 1.152 50.137 1.752 ;
     RECT  49.025 2.736 50.137 2.76 ;
     RECT  49.777 7.344 50.137 7.368 ;
     RECT  49.669 8.928 50.137 8.952 ;
     RECT  49.705 15.264 50.137 15.864 ;
     RECT  49.597 17.28 50.137 17.304 ;
     RECT  49.777 19.296 50.137 20.04 ;
     RECT  49.849 24.048 50.137 24.504 ;
     RECT  49.777 25.632 50.137 26.376 ;
     RECT  49.597 32.544 50.137 32.568 ;
     RECT  48.604 34.416 50.137 34.44 ;
     RECT  49.777 36.144 50.137 36.6 ;
     RECT  49.597 37.728 50.137 38.76 ;
     RECT  49.813 40.176 50.137 41.064 ;
     RECT  50.137 1.152 50.173 2.76 ;
     RECT  49.777 3.888 50.173 4.92 ;
     RECT  50.137 6.048 50.173 7.8 ;
     RECT  50.137 8.928 50.173 9.672 ;
     RECT  48.604 10.656 50.173 10.68 ;
     RECT  49.705 11.664 50.173 12.84 ;
     RECT  49.741 14.112 50.173 14.136 ;
     RECT  50.137 15.264 50.173 17.736 ;
     RECT  50.137 19.296 50.173 20.472 ;
     RECT  48.604 22.32 50.173 22.344 ;
     RECT  50.137 23.328 50.173 24.504 ;
     RECT  50.137 25.632 50.173 28.104 ;
     RECT  50.137 29.088 50.173 29.688 ;
     RECT  50.137 32.544 50.173 33 ;
     RECT  50.137 34.272 50.173 34.44 ;
     RECT  50.137 36.144 50.173 41.064 ;
     RECT  50.137 42.48 50.173 42.936 ;
     RECT  50.173 1.152 50.641 4.92 ;
     RECT  50.173 6.048 50.641 10.68 ;
     RECT  50.173 11.664 50.641 17.736 ;
     RECT  50.641 0.864 50.677 4.92 ;
     RECT  50.641 6.048 50.677 17.736 ;
     RECT  50.173 19.296 50.677 24.504 ;
     RECT  50.173 25.632 50.677 29.688 ;
     RECT  50.173 30.672 50.677 34.44 ;
     RECT  50.173 35.856 50.677 42.936 ;
     RECT  50.677 0.72 50.713 42.936 ;
     RECT  50.713 0.72 51.721 43.08 ;
     RECT  51.721 0.72 51.756 0.744 ;
     RECT  51.721 0.744 51.804 0.864 ;
     RECT  51.721 0.864 51.756 0.888 ;
     RECT  51.721 0.888 51.804 1.008 ;
     RECT  51.721 1.008 51.756 1.032 ;
     RECT  51.721 1.032 51.804 1.152 ;
     RECT  51.721 1.152 51.756 1.176 ;
     RECT  51.721 1.176 51.804 1.296 ;
     RECT  51.721 1.296 51.756 1.32 ;
     RECT  51.721 1.32 51.804 1.44 ;
     RECT  51.721 1.44 51.756 1.464 ;
     RECT  51.721 1.464 51.804 1.584 ;
     RECT  51.721 1.584 51.756 1.608 ;
     RECT  51.721 1.608 51.804 1.728 ;
     RECT  51.721 1.728 51.756 1.752 ;
     RECT  51.721 1.752 51.804 1.872 ;
     RECT  51.721 1.872 51.756 1.896 ;
     RECT  51.721 1.896 51.804 2.016 ;
     RECT  51.721 2.016 51.756 2.04 ;
     RECT  51.721 2.04 51.804 2.16 ;
     RECT  51.721 2.16 51.756 2.184 ;
     RECT  51.721 2.184 51.804 2.304 ;
     RECT  51.721 2.304 51.756 2.328 ;
     RECT  51.721 2.328 51.804 2.448 ;
     RECT  51.721 2.448 51.756 2.472 ;
     RECT  51.721 2.472 51.804 2.592 ;
     RECT  51.721 2.592 51.756 2.616 ;
     RECT  51.721 2.616 51.804 2.736 ;
     RECT  51.721 2.736 51.756 2.76 ;
     RECT  51.721 2.76 51.804 2.88 ;
     RECT  51.721 2.88 51.756 2.904 ;
     RECT  51.721 2.904 51.804 3.024 ;
     RECT  51.721 3.024 51.756 3.048 ;
     RECT  51.721 3.048 51.804 3.168 ;
     RECT  51.721 3.168 51.756 3.192 ;
     RECT  51.721 3.192 51.804 3.312 ;
     RECT  51.721 3.312 51.756 3.336 ;
     RECT  51.721 3.336 51.804 3.456 ;
     RECT  51.721 3.456 51.756 3.48 ;
     RECT  51.721 3.48 51.804 3.6 ;
     RECT  51.721 3.6 51.756 3.624 ;
     RECT  51.721 3.624 51.804 3.744 ;
     RECT  51.721 3.744 51.756 3.768 ;
     RECT  51.721 3.768 51.804 3.888 ;
     RECT  51.721 3.888 51.756 3.912 ;
     RECT  51.721 3.912 51.804 4.032 ;
     RECT  51.721 4.032 51.756 4.056 ;
     RECT  51.721 4.056 51.804 4.176 ;
     RECT  51.721 4.176 51.756 4.2 ;
     RECT  51.721 4.2 51.804 4.32 ;
     RECT  51.721 4.32 51.756 4.344 ;
     RECT  51.721 4.344 51.804 4.464 ;
     RECT  51.721 4.464 51.756 4.488 ;
     RECT  51.721 4.488 51.804 4.608 ;
     RECT  51.721 4.608 51.756 4.632 ;
     RECT  51.721 4.632 51.804 4.752 ;
     RECT  51.721 4.752 51.756 4.776 ;
     RECT  51.721 4.776 51.804 4.896 ;
     RECT  51.721 4.896 51.756 4.92 ;
     RECT  51.721 4.92 51.804 5.04 ;
     RECT  51.721 5.04 51.756 5.064 ;
     RECT  51.721 5.064 51.804 5.184 ;
     RECT  51.721 5.184 51.756 5.208 ;
     RECT  51.721 5.208 51.804 5.328 ;
     RECT  51.721 5.328 51.756 5.352 ;
     RECT  51.721 5.352 51.804 5.472 ;
     RECT  51.721 5.472 51.756 5.496 ;
     RECT  51.721 5.496 51.804 5.616 ;
     RECT  51.721 5.616 51.756 5.64 ;
     RECT  51.721 5.64 51.804 5.76 ;
     RECT  51.721 5.76 51.756 5.784 ;
     RECT  51.721 5.784 51.804 5.904 ;
     RECT  51.721 5.904 51.756 5.928 ;
     RECT  51.721 5.928 51.804 6.048 ;
     RECT  51.721 6.048 51.756 6.072 ;
     RECT  51.721 6.072 51.804 6.192 ;
     RECT  51.721 6.192 51.756 6.216 ;
     RECT  51.721 6.216 51.804 6.336 ;
     RECT  51.721 6.336 51.756 6.36 ;
     RECT  51.721 6.36 51.804 6.48 ;
     RECT  51.721 6.48 51.756 6.504 ;
     RECT  51.721 6.504 51.804 6.624 ;
     RECT  51.721 6.624 51.756 6.648 ;
     RECT  51.721 6.648 51.804 6.768 ;
     RECT  51.721 6.768 51.756 6.792 ;
     RECT  51.721 6.792 51.804 6.912 ;
     RECT  51.721 6.912 51.756 6.936 ;
     RECT  51.721 6.936 51.804 7.056 ;
     RECT  51.721 7.056 51.756 7.08 ;
     RECT  51.721 7.08 51.804 7.2 ;
     RECT  51.721 7.2 51.756 7.224 ;
     RECT  51.721 7.224 51.804 7.344 ;
     RECT  51.721 7.344 51.756 7.368 ;
     RECT  51.721 7.368 51.804 7.488 ;
     RECT  51.721 7.488 51.756 7.512 ;
     RECT  51.721 7.512 51.804 7.632 ;
     RECT  51.721 7.632 51.756 7.656 ;
     RECT  51.721 7.656 51.804 7.776 ;
     RECT  51.721 7.776 51.756 7.8 ;
     RECT  51.721 7.8 51.804 7.92 ;
     RECT  51.721 7.92 51.756 7.944 ;
     RECT  51.721 7.944 51.804 8.064 ;
     RECT  51.721 8.064 51.756 8.088 ;
     RECT  51.721 8.088 51.804 8.208 ;
     RECT  51.721 8.208 51.756 8.232 ;
     RECT  51.721 8.232 51.804 8.352 ;
     RECT  51.721 8.352 51.756 8.376 ;
     RECT  51.721 8.376 51.804 8.496 ;
     RECT  51.721 8.496 51.756 8.52 ;
     RECT  51.721 8.52 51.804 8.64 ;
     RECT  51.721 8.64 51.756 8.664 ;
     RECT  51.721 8.664 51.804 8.784 ;
     RECT  51.721 8.784 51.756 8.808 ;
     RECT  51.721 8.808 51.804 8.928 ;
     RECT  51.721 8.928 51.756 8.952 ;
     RECT  51.721 8.952 51.804 9.072 ;
     RECT  51.721 9.072 51.756 9.096 ;
     RECT  51.721 9.096 51.804 9.216 ;
     RECT  51.721 9.216 51.756 9.24 ;
     RECT  51.721 9.24 51.804 9.36 ;
     RECT  51.721 9.36 51.756 9.384 ;
     RECT  51.721 9.384 51.804 9.504 ;
     RECT  51.721 9.504 51.756 9.528 ;
     RECT  51.721 9.528 51.804 9.648 ;
     RECT  51.721 9.648 51.756 9.672 ;
     RECT  51.721 9.672 51.804 9.792 ;
     RECT  51.721 9.792 51.756 9.816 ;
     RECT  51.721 9.816 51.804 9.936 ;
     RECT  51.721 9.936 51.756 9.96 ;
     RECT  51.721 9.96 51.804 10.08 ;
     RECT  51.721 10.08 51.756 10.104 ;
     RECT  51.721 10.104 51.804 10.224 ;
     RECT  51.721 10.224 51.756 10.248 ;
     RECT  51.721 10.248 51.804 10.368 ;
     RECT  51.721 10.368 51.756 10.392 ;
     RECT  51.721 10.392 51.804 10.512 ;
     RECT  51.721 10.512 51.756 10.536 ;
     RECT  51.721 10.536 51.804 10.656 ;
     RECT  51.721 10.656 51.756 10.68 ;
     RECT  51.721 10.68 51.804 10.8 ;
     RECT  51.721 10.8 51.756 10.824 ;
     RECT  51.721 10.824 51.804 10.944 ;
     RECT  51.721 10.944 51.756 10.968 ;
     RECT  51.721 10.968 51.804 11.088 ;
     RECT  51.721 11.088 51.756 11.112 ;
     RECT  51.721 11.112 51.804 11.232 ;
     RECT  51.721 11.232 51.756 11.256 ;
     RECT  51.721 11.256 51.804 11.376 ;
     RECT  51.721 11.376 51.756 11.4 ;
     RECT  51.721 11.4 51.804 11.52 ;
     RECT  51.721 11.52 51.756 11.544 ;
     RECT  51.721 11.544 51.804 11.664 ;
     RECT  51.721 11.664 51.756 11.688 ;
     RECT  51.721 11.688 51.804 11.808 ;
     RECT  51.721 11.808 51.756 11.832 ;
     RECT  51.721 11.832 51.804 11.952 ;
     RECT  51.721 11.952 51.756 11.976 ;
     RECT  51.721 11.976 51.804 12.096 ;
     RECT  51.721 12.096 51.756 12.12 ;
     RECT  51.721 12.12 51.804 12.24 ;
     RECT  51.721 12.24 51.756 12.264 ;
     RECT  51.721 12.264 51.804 12.384 ;
     RECT  51.721 12.384 51.756 12.408 ;
     RECT  51.721 12.408 51.804 12.528 ;
     RECT  51.721 12.528 51.756 12.552 ;
     RECT  51.721 12.552 51.804 12.672 ;
     RECT  51.721 12.672 51.756 12.696 ;
     RECT  51.721 12.696 51.804 12.816 ;
     RECT  51.721 12.816 51.756 12.84 ;
     RECT  51.721 12.84 51.804 12.96 ;
     RECT  51.721 12.96 51.756 12.984 ;
     RECT  51.721 12.984 51.804 13.104 ;
     RECT  51.721 13.104 51.756 13.128 ;
     RECT  51.721 13.128 51.804 13.248 ;
     RECT  51.721 13.248 51.756 13.272 ;
     RECT  51.721 13.272 51.804 13.392 ;
     RECT  51.721 13.392 51.756 13.416 ;
     RECT  51.721 13.416 51.804 13.536 ;
     RECT  51.721 13.536 51.756 13.56 ;
     RECT  51.721 13.56 51.804 13.68 ;
     RECT  51.721 13.68 51.756 13.704 ;
     RECT  51.721 13.704 51.804 13.824 ;
     RECT  51.721 13.824 51.756 13.848 ;
     RECT  51.721 13.848 51.804 13.968 ;
     RECT  51.721 13.968 51.756 13.992 ;
     RECT  51.721 13.992 51.804 14.112 ;
     RECT  51.721 14.112 51.756 14.136 ;
     RECT  51.721 14.136 51.804 14.256 ;
     RECT  51.721 14.256 51.756 14.28 ;
     RECT  51.721 14.28 51.804 14.4 ;
     RECT  51.721 14.4 51.756 14.424 ;
     RECT  51.721 14.424 51.804 14.544 ;
     RECT  51.721 14.544 51.756 14.568 ;
     RECT  51.721 14.568 51.804 14.688 ;
     RECT  51.721 14.688 51.756 14.712 ;
     RECT  51.721 14.712 51.804 14.832 ;
     RECT  51.721 14.832 51.756 14.856 ;
     RECT  51.721 14.856 51.804 14.976 ;
     RECT  51.721 14.976 51.756 15 ;
     RECT  51.721 15 51.804 15.12 ;
     RECT  51.721 15.12 51.756 15.144 ;
     RECT  51.721 15.144 51.804 15.264 ;
     RECT  51.721 15.264 51.756 15.288 ;
     RECT  51.721 15.288 51.804 15.408 ;
     RECT  51.721 15.408 51.756 15.432 ;
     RECT  51.721 15.432 51.804 15.552 ;
     RECT  51.721 15.552 51.756 15.576 ;
     RECT  51.721 15.576 51.804 15.696 ;
     RECT  51.721 15.696 51.756 15.72 ;
     RECT  51.721 15.72 51.804 15.84 ;
     RECT  51.721 15.84 51.756 15.864 ;
     RECT  51.721 15.864 51.804 15.984 ;
     RECT  51.721 15.984 51.756 16.008 ;
     RECT  51.721 16.008 51.804 16.128 ;
     RECT  51.721 16.128 51.756 16.152 ;
     RECT  51.721 16.152 51.804 16.272 ;
     RECT  51.721 16.272 51.756 16.296 ;
     RECT  51.721 16.296 51.804 16.416 ;
     RECT  51.721 16.416 51.756 16.44 ;
     RECT  51.721 16.44 51.804 16.56 ;
     RECT  51.721 16.56 51.756 16.584 ;
     RECT  51.721 16.584 51.804 16.704 ;
     RECT  51.721 16.704 51.756 16.728 ;
     RECT  51.721 16.728 51.804 16.848 ;
     RECT  51.721 16.848 51.756 16.872 ;
     RECT  51.721 16.872 51.804 16.992 ;
     RECT  51.721 16.992 51.756 17.016 ;
     RECT  51.721 17.016 51.804 17.136 ;
     RECT  51.721 17.136 51.756 17.16 ;
     RECT  51.721 17.16 51.804 17.28 ;
     RECT  51.721 17.28 51.756 17.304 ;
     RECT  51.721 17.304 51.804 17.424 ;
     RECT  51.721 17.424 51.756 17.448 ;
     RECT  51.721 17.448 51.804 17.568 ;
     RECT  51.721 17.568 51.756 17.592 ;
     RECT  51.721 17.592 51.804 17.712 ;
     RECT  51.721 17.712 51.756 17.736 ;
     RECT  51.721 17.736 51.804 17.856 ;
     RECT  51.721 17.856 51.756 17.88 ;
     RECT  51.721 17.88 51.804 18 ;
     RECT  51.721 18 51.756 18.024 ;
     RECT  51.721 18.024 51.804 18.144 ;
     RECT  51.721 18.144 51.756 18.168 ;
     RECT  51.721 18.168 51.804 18.288 ;
     RECT  51.721 18.288 51.756 18.312 ;
     RECT  51.721 18.312 51.804 18.432 ;
     RECT  51.721 18.432 51.756 18.456 ;
     RECT  51.721 18.456 51.804 18.576 ;
     RECT  51.721 18.576 51.756 18.6 ;
     RECT  51.721 18.6 51.804 18.72 ;
     RECT  51.721 18.72 51.756 18.744 ;
     RECT  51.721 18.744 51.804 18.864 ;
     RECT  51.721 18.864 51.756 18.888 ;
     RECT  51.721 18.888 51.804 19.008 ;
     RECT  51.721 19.008 51.756 19.032 ;
     RECT  51.721 19.032 51.804 19.152 ;
     RECT  51.721 19.152 51.756 19.176 ;
     RECT  51.721 19.176 51.804 19.296 ;
     RECT  51.721 19.296 51.756 19.32 ;
     RECT  51.721 19.32 51.804 19.44 ;
     RECT  51.721 19.44 51.756 19.464 ;
     RECT  51.721 19.464 51.804 19.584 ;
     RECT  51.721 19.584 51.756 19.608 ;
     RECT  51.721 19.608 51.804 19.728 ;
     RECT  51.721 19.728 51.756 19.752 ;
     RECT  51.721 19.752 51.804 19.872 ;
     RECT  51.721 19.872 51.756 19.896 ;
     RECT  51.721 19.896 51.804 20.016 ;
     RECT  51.721 20.016 51.756 20.04 ;
     RECT  51.721 20.04 51.804 20.16 ;
     RECT  51.721 20.16 51.756 20.184 ;
     RECT  51.721 20.184 51.804 20.304 ;
     RECT  51.721 20.304 51.756 20.328 ;
     RECT  51.721 20.328 51.804 20.448 ;
     RECT  51.721 20.448 51.756 20.472 ;
     RECT  51.721 20.472 51.804 20.592 ;
     RECT  51.721 20.592 51.756 20.616 ;
     RECT  51.721 20.616 51.804 20.736 ;
     RECT  51.721 20.736 51.756 20.76 ;
     RECT  51.721 20.76 51.804 20.88 ;
     RECT  51.721 20.88 51.756 20.904 ;
     RECT  51.721 20.904 51.804 21.024 ;
     RECT  51.721 21.024 51.756 21.048 ;
     RECT  51.721 21.048 51.804 21.168 ;
     RECT  51.721 21.168 51.756 21.192 ;
     RECT  51.721 21.192 51.804 21.312 ;
     RECT  51.721 21.312 51.756 21.336 ;
     RECT  51.721 21.336 51.804 21.456 ;
     RECT  51.721 21.456 51.756 21.48 ;
     RECT  51.721 21.48 51.804 21.6 ;
     RECT  51.721 21.6 51.756 21.624 ;
     RECT  51.721 21.624 51.804 21.744 ;
     RECT  51.721 21.744 51.756 21.768 ;
     RECT  51.721 21.768 51.804 21.888 ;
     RECT  51.721 21.888 51.756 21.912 ;
     RECT  51.721 21.912 51.804 22.032 ;
     RECT  51.721 22.032 51.756 22.056 ;
     RECT  51.721 22.056 51.804 22.176 ;
     RECT  51.721 22.176 51.756 22.2 ;
     RECT  51.721 22.2 51.804 22.32 ;
     RECT  51.721 22.32 51.756 22.344 ;
     RECT  51.721 22.344 51.804 22.464 ;
     RECT  51.721 22.464 51.756 22.488 ;
     RECT  51.721 22.488 51.804 22.608 ;
     RECT  51.721 22.608 51.756 22.632 ;
     RECT  51.721 22.632 51.804 22.752 ;
     RECT  51.721 22.752 51.756 22.776 ;
     RECT  51.721 22.776 51.804 22.896 ;
     RECT  51.721 22.896 51.756 22.92 ;
     RECT  51.721 22.92 51.804 23.04 ;
     RECT  51.721 23.04 51.756 23.064 ;
     RECT  51.721 23.064 51.804 23.184 ;
     RECT  51.721 23.184 51.756 23.208 ;
     RECT  51.721 23.208 51.804 23.328 ;
     RECT  51.721 23.328 51.756 23.352 ;
     RECT  51.721 23.352 51.804 23.472 ;
     RECT  51.721 23.472 51.756 23.496 ;
     RECT  51.721 23.496 51.804 23.616 ;
     RECT  51.721 23.616 51.756 23.64 ;
     RECT  51.721 23.64 51.804 23.76 ;
     RECT  51.721 23.76 51.756 23.784 ;
     RECT  51.721 23.784 51.804 23.904 ;
     RECT  51.721 23.904 51.756 23.928 ;
     RECT  51.721 23.928 51.804 24.048 ;
     RECT  51.721 24.048 51.756 24.072 ;
     RECT  51.721 24.072 51.804 24.192 ;
     RECT  51.721 24.192 51.756 24.216 ;
     RECT  51.721 24.216 51.804 24.336 ;
     RECT  51.721 24.336 51.756 24.36 ;
     RECT  51.721 24.36 51.804 24.48 ;
     RECT  51.721 24.48 51.756 24.504 ;
     RECT  51.721 24.504 51.804 24.624 ;
     RECT  51.721 24.624 51.756 24.648 ;
     RECT  51.721 24.648 51.804 24.768 ;
     RECT  51.721 24.768 51.756 24.792 ;
     RECT  51.721 24.792 51.804 24.912 ;
     RECT  51.721 24.912 51.756 24.936 ;
     RECT  51.721 24.936 51.804 25.056 ;
     RECT  51.721 25.056 51.756 25.08 ;
     RECT  51.721 25.08 51.804 25.2 ;
     RECT  51.721 25.2 51.756 25.224 ;
     RECT  51.721 25.224 51.804 25.344 ;
     RECT  51.721 25.344 51.756 25.368 ;
     RECT  51.721 25.368 51.804 25.488 ;
     RECT  51.721 25.488 51.756 25.512 ;
     RECT  51.721 25.512 51.804 25.632 ;
     RECT  51.721 25.632 51.756 25.656 ;
     RECT  51.721 25.656 51.804 25.776 ;
     RECT  51.721 25.776 51.756 25.8 ;
     RECT  51.721 25.8 51.804 25.92 ;
     RECT  51.721 25.92 51.756 25.944 ;
     RECT  51.721 25.944 51.804 26.064 ;
     RECT  51.721 26.064 51.756 26.088 ;
     RECT  51.721 26.088 51.804 26.208 ;
     RECT  51.721 26.208 51.756 26.232 ;
     RECT  51.721 26.232 51.804 26.352 ;
     RECT  51.721 26.352 51.756 26.376 ;
     RECT  51.721 26.376 51.804 26.496 ;
     RECT  51.721 26.496 51.756 26.52 ;
     RECT  51.721 26.52 51.804 26.64 ;
     RECT  51.721 26.64 51.756 26.664 ;
     RECT  51.721 26.664 51.804 26.784 ;
     RECT  51.721 26.784 51.756 26.808 ;
     RECT  51.721 26.808 51.804 26.928 ;
     RECT  51.721 26.928 51.756 26.952 ;
     RECT  51.721 26.952 51.804 27.072 ;
     RECT  51.721 27.072 51.756 27.096 ;
     RECT  51.721 27.096 51.804 27.216 ;
     RECT  51.721 27.216 51.756 27.24 ;
     RECT  51.721 27.24 51.804 27.36 ;
     RECT  51.721 27.36 51.756 27.384 ;
     RECT  51.721 27.384 51.804 27.504 ;
     RECT  51.721 27.504 51.756 27.528 ;
     RECT  51.721 27.528 51.804 27.648 ;
     RECT  51.721 27.648 51.756 27.672 ;
     RECT  51.721 27.672 51.804 27.792 ;
     RECT  51.721 27.792 51.756 27.816 ;
     RECT  51.721 27.816 51.804 27.936 ;
     RECT  51.721 27.936 51.756 27.96 ;
     RECT  51.721 27.96 51.804 28.08 ;
     RECT  51.721 28.08 51.756 28.104 ;
     RECT  51.721 28.104 51.804 28.224 ;
     RECT  51.721 28.224 51.756 28.248 ;
     RECT  51.721 28.248 51.804 28.368 ;
     RECT  51.721 28.368 51.756 28.392 ;
     RECT  51.721 28.392 51.804 28.512 ;
     RECT  51.721 28.512 51.756 28.536 ;
     RECT  51.721 28.536 51.804 28.656 ;
     RECT  51.721 28.656 51.756 28.68 ;
     RECT  51.721 28.68 51.804 28.8 ;
     RECT  51.721 28.8 51.756 28.824 ;
     RECT  51.721 28.824 51.804 28.944 ;
     RECT  51.721 28.944 51.756 28.968 ;
     RECT  51.721 28.968 51.804 29.088 ;
     RECT  51.721 29.088 51.756 29.112 ;
     RECT  51.721 29.112 51.804 29.232 ;
     RECT  51.721 29.232 51.756 29.256 ;
     RECT  51.721 29.256 51.804 29.376 ;
     RECT  51.721 29.376 51.756 29.4 ;
     RECT  51.721 29.4 51.804 29.52 ;
     RECT  51.721 29.52 51.756 29.544 ;
     RECT  51.721 29.544 51.804 29.664 ;
     RECT  51.721 29.664 51.756 29.688 ;
     RECT  51.721 29.688 51.804 29.808 ;
     RECT  51.721 29.808 51.756 29.832 ;
     RECT  51.721 29.832 51.804 29.952 ;
     RECT  51.721 29.952 51.756 29.976 ;
     RECT  51.721 29.976 51.804 30.096 ;
     RECT  51.721 30.096 51.756 30.12 ;
     RECT  51.721 30.12 51.804 30.24 ;
     RECT  51.721 30.24 51.756 30.264 ;
     RECT  51.721 30.264 51.804 30.384 ;
     RECT  51.721 30.384 51.756 30.408 ;
     RECT  51.721 30.408 51.804 30.528 ;
     RECT  51.721 30.528 51.756 30.552 ;
     RECT  51.721 30.552 51.804 30.672 ;
     RECT  51.721 30.672 51.756 30.696 ;
     RECT  51.721 30.696 51.804 30.816 ;
     RECT  51.721 30.816 51.756 30.84 ;
     RECT  51.721 30.84 51.804 30.96 ;
     RECT  51.721 30.96 51.756 30.984 ;
     RECT  51.721 30.984 51.804 31.104 ;
     RECT  51.721 31.104 51.756 31.128 ;
     RECT  51.721 31.128 51.804 31.248 ;
     RECT  51.721 31.248 51.756 31.272 ;
     RECT  51.721 31.272 51.804 31.392 ;
     RECT  51.721 31.392 51.756 31.416 ;
     RECT  51.721 31.416 51.804 31.536 ;
     RECT  51.721 31.536 51.756 31.56 ;
     RECT  51.721 31.56 51.804 31.68 ;
     RECT  51.721 31.68 51.756 31.704 ;
     RECT  51.721 31.704 51.804 31.824 ;
     RECT  51.721 31.824 51.756 31.848 ;
     RECT  51.721 31.848 51.804 31.968 ;
     RECT  51.721 31.968 51.756 31.992 ;
     RECT  51.721 31.992 51.804 32.112 ;
     RECT  51.721 32.112 51.756 32.136 ;
     RECT  51.721 32.136 51.804 32.256 ;
     RECT  51.721 32.256 51.756 32.28 ;
     RECT  51.721 32.28 51.804 32.4 ;
     RECT  51.721 32.4 51.756 32.424 ;
     RECT  51.721 32.424 51.804 32.544 ;
     RECT  51.721 32.544 51.756 32.568 ;
     RECT  51.721 32.568 51.804 32.688 ;
     RECT  51.721 32.688 51.756 32.712 ;
     RECT  51.721 32.712 51.804 32.832 ;
     RECT  51.721 32.832 51.756 32.856 ;
     RECT  51.721 32.856 51.804 32.976 ;
     RECT  51.721 32.976 51.756 33 ;
     RECT  51.721 33 51.804 33.12 ;
     RECT  51.721 33.12 51.756 33.144 ;
     RECT  51.721 33.144 51.804 33.264 ;
     RECT  51.721 33.264 51.756 33.288 ;
     RECT  51.721 33.288 51.804 33.408 ;
     RECT  51.721 33.408 51.756 33.432 ;
     RECT  51.721 33.432 51.804 33.552 ;
     RECT  51.721 33.552 51.756 33.576 ;
     RECT  51.721 33.576 51.804 33.696 ;
     RECT  51.721 33.696 51.756 33.72 ;
     RECT  51.721 33.72 51.804 33.84 ;
     RECT  51.721 33.84 51.756 33.864 ;
     RECT  51.721 33.864 51.804 33.984 ;
     RECT  51.721 33.984 51.756 34.008 ;
     RECT  51.721 34.008 51.804 34.128 ;
     RECT  51.721 34.128 51.756 34.152 ;
     RECT  51.721 34.152 51.804 34.272 ;
     RECT  51.721 34.272 51.756 34.296 ;
     RECT  51.721 34.296 51.804 34.416 ;
     RECT  51.721 34.416 51.756 34.44 ;
     RECT  51.721 34.44 51.804 34.56 ;
     RECT  51.721 34.56 51.756 34.584 ;
     RECT  51.721 34.584 51.804 34.704 ;
     RECT  51.721 34.704 51.756 34.728 ;
     RECT  51.721 34.728 51.804 34.848 ;
     RECT  51.721 34.848 51.756 34.872 ;
     RECT  51.721 34.872 51.804 34.992 ;
     RECT  51.721 34.992 51.756 35.016 ;
     RECT  51.721 35.016 51.804 35.136 ;
     RECT  51.721 35.136 51.756 35.16 ;
     RECT  51.721 35.16 51.804 35.28 ;
     RECT  51.721 35.28 51.756 35.304 ;
     RECT  51.721 35.304 51.804 35.424 ;
     RECT  51.721 35.424 51.756 35.448 ;
     RECT  51.721 35.448 51.804 35.568 ;
     RECT  51.721 35.568 51.756 35.592 ;
     RECT  51.721 35.592 51.804 35.712 ;
     RECT  51.721 35.712 51.756 35.736 ;
     RECT  51.721 35.736 51.804 35.856 ;
     RECT  51.721 35.856 51.756 35.88 ;
     RECT  51.721 35.88 51.804 36 ;
     RECT  51.721 36 51.756 36.024 ;
     RECT  51.721 36.024 51.804 36.144 ;
     RECT  51.721 36.144 51.756 36.168 ;
     RECT  51.721 36.168 51.804 36.288 ;
     RECT  51.721 36.288 51.756 36.312 ;
     RECT  51.721 36.312 51.804 36.432 ;
     RECT  51.721 36.432 51.756 36.456 ;
     RECT  51.721 36.456 51.804 36.576 ;
     RECT  51.721 36.576 51.756 36.6 ;
     RECT  51.721 36.6 51.804 36.72 ;
     RECT  51.721 36.72 51.756 36.744 ;
     RECT  51.721 36.744 51.804 36.864 ;
     RECT  51.721 36.864 51.756 36.888 ;
     RECT  51.721 36.888 51.804 37.008 ;
     RECT  51.721 37.008 51.756 37.032 ;
     RECT  51.721 37.032 51.804 37.152 ;
     RECT  51.721 37.152 51.756 37.176 ;
     RECT  51.721 37.176 51.804 37.296 ;
     RECT  51.721 37.296 51.756 37.32 ;
     RECT  51.721 37.32 51.804 37.44 ;
     RECT  51.721 37.44 51.756 37.464 ;
     RECT  51.721 37.464 51.804 37.584 ;
     RECT  51.721 37.584 51.756 37.608 ;
     RECT  51.721 37.608 51.804 37.728 ;
     RECT  51.721 37.728 51.756 37.752 ;
     RECT  51.721 37.752 51.804 37.872 ;
     RECT  51.721 37.872 51.756 37.896 ;
     RECT  51.721 37.896 51.804 38.016 ;
     RECT  51.721 38.016 51.756 38.04 ;
     RECT  51.721 38.04 51.804 38.16 ;
     RECT  51.721 38.16 51.756 38.184 ;
     RECT  51.721 38.184 51.804 38.304 ;
     RECT  51.721 38.304 51.756 38.328 ;
     RECT  51.721 38.328 51.804 38.448 ;
     RECT  51.721 38.448 51.756 38.472 ;
     RECT  51.721 38.472 51.804 38.592 ;
     RECT  51.721 38.592 51.756 38.616 ;
     RECT  51.721 38.616 51.804 38.736 ;
     RECT  51.721 38.736 51.756 38.76 ;
     RECT  51.721 38.76 51.804 38.88 ;
     RECT  51.721 38.88 51.756 38.904 ;
     RECT  51.721 38.904 51.804 39.024 ;
     RECT  51.721 39.024 51.756 39.048 ;
     RECT  51.721 39.048 51.804 39.168 ;
     RECT  51.721 39.168 51.756 39.192 ;
     RECT  51.721 39.192 51.804 39.312 ;
     RECT  51.721 39.312 51.756 39.336 ;
     RECT  51.721 39.336 51.804 39.456 ;
     RECT  51.721 39.456 51.756 39.48 ;
     RECT  51.721 39.48 51.804 39.6 ;
     RECT  51.721 39.6 51.756 39.624 ;
     RECT  51.721 39.624 51.804 39.744 ;
     RECT  51.721 39.744 51.756 39.768 ;
     RECT  51.721 39.768 51.804 39.888 ;
     RECT  51.721 39.888 51.756 39.912 ;
     RECT  51.721 39.912 51.804 40.032 ;
     RECT  51.721 40.032 51.756 40.056 ;
     RECT  51.721 40.056 51.804 40.176 ;
     RECT  51.721 40.176 51.756 40.2 ;
     RECT  51.721 40.2 51.804 40.32 ;
     RECT  51.721 40.32 51.756 40.344 ;
     RECT  51.721 40.344 51.804 40.464 ;
     RECT  51.721 40.464 51.756 40.488 ;
     RECT  51.721 40.488 51.804 40.608 ;
     RECT  51.721 40.608 51.756 40.632 ;
     RECT  51.721 40.632 51.804 40.752 ;
     RECT  51.721 40.752 51.756 40.776 ;
     RECT  51.721 40.776 51.804 40.896 ;
     RECT  51.721 40.896 51.756 40.92 ;
     RECT  51.721 40.92 51.804 41.04 ;
     RECT  51.721 41.04 51.756 41.064 ;
     RECT  51.721 41.064 51.804 41.184 ;
     RECT  51.721 41.184 51.756 41.208 ;
     RECT  51.721 41.208 51.804 41.328 ;
     RECT  51.721 41.328 51.756 41.352 ;
     RECT  51.721 41.352 51.804 41.472 ;
     RECT  51.721 41.472 51.756 41.496 ;
     RECT  51.721 41.496 51.804 41.616 ;
     RECT  51.721 41.616 51.756 41.64 ;
     RECT  51.721 41.64 51.804 41.76 ;
     RECT  51.721 41.76 51.756 41.784 ;
     RECT  51.721 41.784 51.804 41.904 ;
     RECT  51.721 41.904 51.756 41.928 ;
     RECT  51.721 41.928 51.804 42.048 ;
     RECT  51.721 42.048 51.756 42.072 ;
     RECT  51.721 42.072 51.804 42.192 ;
     RECT  51.721 42.192 51.756 42.216 ;
     RECT  51.721 42.216 51.804 42.336 ;
     RECT  51.721 42.336 51.756 42.36 ;
     RECT  51.721 42.36 51.804 42.48 ;
     RECT  51.721 42.48 51.756 42.504 ;
     RECT  51.721 42.504 51.804 42.624 ;
     RECT  51.721 42.624 51.756 42.648 ;
     RECT  51.721 42.648 51.804 42.768 ;
     RECT  51.721 42.768 51.756 42.792 ;
     RECT  51.721 42.792 51.804 42.912 ;
     RECT  51.721 42.912 51.756 42.936 ;
     RECT  51.721 42.936 51.804 43.056 ;
     RECT  51.721 43.056 51.756 43.08 ;
     RECT  51.721 43.08 51.804 43.2 ;
     RECT  51.721 43.2 51.756 43.224 ;
    LAYER M5 ;
     RECT  18.888 0.016 19.008 0.084 ;
     RECT  19.032 0.016 19.152 0.084 ;
     RECT  19.176 0.016 19.296 0.084 ;
     RECT  19.32 0.016 19.44 0.084 ;
     RECT  19.464 0.016 19.584 0.084 ;
     RECT  19.608 0.016 19.728 0.084 ;
     RECT  18.864 0.084 19.752 0.371 ;
     RECT  19.008 0.371 19.752 1.763 ;
     RECT  19.008 1.763 19.512 2.137 ;
     RECT  2.4 2.137 2.52 2.151 ;
     RECT  5.1 2.137 5.22 2.151 ;
     RECT  7.8 2.137 7.92 2.151 ;
     RECT  10.5 2.137 10.62 2.151 ;
     RECT  13.2 2.137 13.32 2.151 ;
     RECT  15.9 2.137 16.02 2.151 ;
     RECT  21.3 2.137 21.42 2.151 ;
     RECT  24 2.137 24.12 2.151 ;
     RECT  26.7 2.137 26.82 2.151 ;
     RECT  29.4 2.137 29.52 2.151 ;
     RECT  32.1 2.137 32.22 2.151 ;
     RECT  34.8 2.137 34.92 2.151 ;
     RECT  37.5 2.137 37.62 2.151 ;
     RECT  40.2 2.137 40.32 2.151 ;
     RECT  42.9 2.137 43.02 2.151 ;
     RECT  45.6 2.137 45.72 2.151 ;
     RECT  48.3 2.137 48.42 2.151 ;
     RECT  29.4 2.151 29.712 2.725 ;
     RECT  37.5 2.151 37.812 2.725 ;
     RECT  14.592 2.725 14.616 3.109 ;
     RECT  14.592 3.109 14.712 3.155 ;
     RECT  24 2.151 24.312 3.397 ;
     RECT  37.5 2.725 38.232 3.493 ;
     RECT  6.48 2.821 6.504 3.539 ;
     RECT  37.5 3.493 38.808 3.539 ;
     RECT  28.416 2.725 29.712 3.829 ;
     RECT  38.784 3.539 38.808 3.875 ;
     RECT  14.688 3.155 14.712 3.923 ;
     RECT  2.4 2.151 2.712 3.925 ;
     RECT  34.8 2.151 35.112 3.925 ;
     RECT  28.416 3.829 30.312 4.115 ;
     RECT  40.2 2.151 40.512 4.117 ;
     RECT  39.888 4.117 40.512 4.357 ;
     RECT  18.6 2.137 19.512 4.405 ;
     RECT  18.6 4.405 19.944 4.501 ;
     RECT  23.376 3.397 24.312 4.643 ;
     RECT  45.6 2.151 45.912 4.645 ;
     RECT  28.512 4.115 30.312 4.691 ;
     RECT  18.6 4.501 20.136 4.741 ;
     RECT  7.8 2.151 8.112 4.933 ;
     RECT  2.4 3.925 3.336 5.219 ;
     RECT  22.8 5.125 22.824 5.267 ;
     RECT  13.2 2.151 13.512 5.461 ;
     RECT  14.784 3.925 14.808 5.461 ;
     RECT  28.512 4.691 29.712 5.653 ;
     RECT  32.1 2.151 32.412 5.653 ;
     RECT  7.8 4.933 8.232 5.747 ;
     RECT  36.48 5.077 36.504 5.747 ;
     RECT  17.616 4.741 20.136 5.987 ;
     RECT  13.2 5.461 14.808 6.035 ;
     RECT  34.704 3.925 35.112 6.035 ;
     RECT  39.552 4.357 40.512 6.083 ;
     RECT  42.9 2.151 43.212 6.133 ;
     RECT  2.4 5.219 2.808 6.179 ;
     RECT  37.5 3.539 37.812 6.229 ;
     RECT  18 5.987 20.136 6.275 ;
     RECT  27.984 5.653 29.712 6.611 ;
     RECT  28.08 6.611 29.712 6.851 ;
     RECT  31.872 5.653 32.412 6.851 ;
     RECT  42.144 6.133 43.212 6.851 ;
     RECT  13.2 6.035 14.424 7.043 ;
     RECT  7.8 5.747 8.112 7.093 ;
     RECT  9.12 6.805 9.144 7.093 ;
     RECT  45.6 4.645 46.152 7.381 ;
     RECT  7.8 7.093 9.144 7.427 ;
     RECT  3.984 6.181 4.008 7.667 ;
     RECT  34.8 6.035 35.112 7.909 ;
     RECT  15.9 2.151 16.212 7.957 ;
     RECT  18 6.275 19.512 7.957 ;
     RECT  40.2 6.083 40.512 8.149 ;
     RECT  21.3 2.151 21.612 8.197 ;
     RECT  18 7.957 19.848 8.243 ;
     RECT  24 4.643 24.312 8.293 ;
     RECT  24 8.293 25.272 8.341 ;
     RECT  2.4 6.179 2.712 8.437 ;
     RECT  10.5 2.151 10.812 8.437 ;
     RECT  5.1 2.151 5.412 8.485 ;
     RECT  45.504 7.381 46.152 8.531 ;
     RECT  45.504 8.531 46.104 8.579 ;
     RECT  23.568 8.341 25.272 8.915 ;
     RECT  34.032 7.909 35.112 9.253 ;
     RECT  18 8.243 19.512 9.493 ;
     RECT  24 8.915 25.272 9.493 ;
     RECT  29.4 6.851 29.712 9.493 ;
     RECT  34.032 9.253 35.352 9.539 ;
     RECT  26.7 2.151 27.012 9.541 ;
     RECT  28.08 6.851 28.104 9.541 ;
     RECT  24 9.493 25.32 9.635 ;
     RECT  32.1 6.851 32.412 9.637 ;
     RECT  48.3 2.151 48.612 9.637 ;
     RECT  2.4 8.437 3.624 9.731 ;
     RECT  34.8 9.539 35.352 10.019 ;
     RECT  40.08 8.149 40.512 10.021 ;
     RECT  21.3 8.197 22.536 10.067 ;
     RECT  18 9.493 20.232 10.115 ;
     RECT  13.2 7.043 13.512 10.213 ;
     RECT  15.408 7.957 16.212 10.213 ;
     RECT  26.7 9.541 28.104 10.307 ;
     RECT  31.872 9.637 32.412 10.307 ;
     RECT  4.992 8.485 5.412 10.453 ;
     RECT  10.368 8.437 10.812 10.693 ;
     RECT  28.08 10.307 28.104 10.789 ;
     RECT  39.888 10.021 40.512 10.789 ;
     RECT  28.08 10.789 28.2 10.835 ;
     RECT  15.216 10.213 16.212 10.883 ;
     RECT  47.424 9.637 48.612 10.883 ;
     RECT  15.9 10.883 16.212 10.933 ;
     RECT  39.888 10.789 41.208 11.027 ;
     RECT  4.992 10.453 5.544 11.029 ;
     RECT  7.8 7.427 8.28 11.125 ;
     RECT  13.2 10.213 13.944 11.173 ;
     RECT  37.5 6.229 38.424 11.173 ;
     RECT  12.528 11.173 13.944 11.219 ;
     RECT  39.888 11.027 40.512 11.219 ;
     RECT  25.296 9.635 25.32 11.459 ;
     RECT  34.8 10.019 35.208 11.459 ;
     RECT  9.696 10.693 10.812 11.651 ;
     RECT  34.8 11.459 35.112 11.989 ;
     RECT  4.992 11.029 6.264 12.035 ;
     RECT  7.8 11.125 8.376 12.035 ;
     RECT  14.832 11.365 14.856 12.035 ;
     RECT  18.192 10.115 20.232 12.035 ;
     RECT  29.4 9.493 30.12 12.035 ;
     RECT  15.9 10.933 16.92 12.227 ;
     RECT  37.5 11.173 38.616 12.227 ;
     RECT  42.9 6.851 43.212 12.325 ;
     RECT  5.1 12.035 6.264 12.371 ;
     RECT  41.568 11.365 41.592 12.515 ;
     RECT  10.5 11.651 10.812 12.517 ;
     RECT  36.432 11.365 36.456 12.563 ;
     RECT  45.6 8.579 46.104 12.853 ;
     RECT  12.528 11.219 13.512 13.043 ;
     RECT  34.368 11.989 35.112 13.043 ;
     RECT  18.192 12.035 19.512 13.045 ;
     RECT  18.192 13.045 19.992 13.237 ;
     RECT  45.504 12.853 46.104 13.379 ;
     RECT  21.3 10.067 21.612 13.381 ;
     RECT  10.5 12.517 10.92 13.475 ;
     RECT  24 9.635 24.312 13.573 ;
     RECT  26.7 10.307 27.012 13.621 ;
     RECT  28.176 10.835 28.2 13.621 ;
     RECT  34.8 13.043 35.112 13.621 ;
     RECT  37.5 12.227 38.424 13.621 ;
     RECT  13.2 13.043 13.512 13.717 ;
     RECT  37.296 13.621 38.424 14.101 ;
     RECT  23.376 13.573 24.312 14.147 ;
     RECT  5.1 12.371 5.412 14.149 ;
     RECT  10.5 13.475 10.812 14.149 ;
     RECT  14.832 13.909 14.856 14.195 ;
     RECT  23.76 14.147 24.312 14.197 ;
     RECT  26.7 13.621 28.2 14.197 ;
     RECT  29.4 12.035 29.712 14.197 ;
     RECT  32.1 10.307 32.412 14.197 ;
     RECT  33.6 13.621 33.624 14.197 ;
     RECT  34.8 13.621 35.352 14.293 ;
     RECT  37.296 14.101 38.664 14.387 ;
     RECT  17.904 13.237 19.992 14.435 ;
     RECT  13.2 13.717 13.608 14.533 ;
     RECT  32.1 14.197 33.624 14.627 ;
     RECT  21.072 13.381 21.612 14.773 ;
     RECT  37.5 14.387 38.664 14.773 ;
     RECT  23.76 14.197 24.408 14.821 ;
     RECT  10.32 14.149 10.812 14.915 ;
     RECT  15.9 12.227 16.68 14.917 ;
     RECT  34.8 14.293 35.544 14.963 ;
     RECT  42.9 12.325 43.608 14.963 ;
     RECT  26.7 14.197 29.712 15.059 ;
     RECT  45.6 13.379 46.104 15.059 ;
     RECT  15.9 14.917 16.728 15.061 ;
     RECT  23.76 14.821 25.272 15.301 ;
     RECT  23.76 15.301 25.464 15.395 ;
     RECT  32.1 14.627 32.808 15.443 ;
     RECT  15.168 15.061 16.728 15.445 ;
     RECT  37.5 14.773 38.808 15.491 ;
     RECT  13.2 14.533 13.704 15.541 ;
     RECT  14.832 15.445 16.728 15.541 ;
     RECT  40.2 11.219 40.512 15.541 ;
     RECT  26.7 15.059 27.672 15.683 ;
     RECT  4.992 14.149 5.412 15.877 ;
     RECT  17.904 14.435 19.512 15.877 ;
     RECT  20.496 14.773 21.612 15.877 ;
     RECT  13.2 15.541 16.728 15.923 ;
     RECT  10.5 14.915 10.812 15.925 ;
     RECT  15.168 15.923 16.728 15.925 ;
     RECT  17.904 15.877 21.612 15.925 ;
     RECT  28.656 15.059 29.712 16.211 ;
     RECT  13.2 15.923 14.184 16.259 ;
     RECT  30.72 14.917 30.744 16.405 ;
     RECT  32.1 15.443 32.412 16.405 ;
     RECT  34.8 14.963 35.112 16.405 ;
     RECT  36.288 15.445 36.312 16.499 ;
     RECT  37.5 15.491 38.664 16.501 ;
     RECT  15.168 15.925 21.612 16.547 ;
     RECT  39.936 15.541 40.512 16.691 ;
     RECT  42.9 14.963 43.212 16.885 ;
     RECT  9.648 15.925 10.812 17.075 ;
     RECT  15.168 16.547 19.512 17.123 ;
     RECT  25.44 15.395 25.464 17.123 ;
     RECT  4.848 15.877 5.412 17.171 ;
     RECT  20.496 16.547 21.612 17.171 ;
     RECT  15.9 17.123 19.512 17.315 ;
     RECT  37.5 16.501 38.808 17.363 ;
     RECT  5.1 17.171 5.412 17.557 ;
     RECT  7.8 12.035 8.28 17.605 ;
     RECT  21.3 17.171 21.612 17.605 ;
     RECT  30.72 16.405 32.412 17.651 ;
     RECT  30.72 17.651 30.744 17.699 ;
     RECT  34.8 16.405 35.208 17.699 ;
     RECT  42.9 16.885 43.608 17.989 ;
     RECT  45.6 15.059 46.008 18.035 ;
     RECT  15.9 17.315 16.968 18.133 ;
     RECT  5.1 17.557 5.784 18.419 ;
     RECT  15.36 18.133 16.968 18.419 ;
     RECT  3.696 17.461 3.72 18.515 ;
     RECT  28.896 16.211 29.712 18.661 ;
     RECT  32.1 17.651 32.412 18.661 ;
     RECT  25.632 17.605 25.656 18.707 ;
     RECT  42.9 17.989 44.472 18.709 ;
     RECT  7.8 17.605 8.616 18.755 ;
     RECT  13.2 16.259 13.512 18.757 ;
     RECT  32.1 18.661 32.52 18.757 ;
     RECT  34.8 17.699 35.112 18.757 ;
     RECT  28.896 18.661 29.832 18.803 ;
     RECT  21.3 17.605 22.056 18.851 ;
     RECT  26.7 15.683 27.012 19.237 ;
     RECT  42.48 18.709 44.472 19.523 ;
     RECT  15.36 18.419 16.872 19.621 ;
     RECT  5.1 18.419 5.412 19.669 ;
     RECT  32.1 18.757 32.856 19.763 ;
     RECT  34.8 18.757 35.736 19.813 ;
     RECT  32.1 19.763 32.412 19.861 ;
     RECT  26.7 19.237 27.144 20.003 ;
     RECT  42.48 19.523 43.212 20.003 ;
     RECT  5.1 19.669 5.88 20.053 ;
     RECT  34.224 19.813 36.36 20.101 ;
     RECT  28.896 18.803 29.712 20.197 ;
     RECT  31.344 19.861 32.412 20.197 ;
     RECT  44.448 19.523 44.472 20.291 ;
     RECT  10.5 17.075 10.812 20.533 ;
     RECT  12.288 18.757 13.512 20.533 ;
     RECT  28.896 20.197 32.412 20.579 ;
     RECT  34.224 20.101 36.456 20.579 ;
     RECT  2.4 9.731 2.712 20.677 ;
     RECT  10.5 20.533 13.512 20.819 ;
     RECT  40.2 16.691 40.512 20.869 ;
     RECT  23.76 15.395 24.312 21.013 ;
     RECT  28.896 20.579 30.6 21.013 ;
     RECT  2.304 20.677 2.712 21.059 ;
     RECT  15.312 19.621 16.872 21.061 ;
     RECT  4.56 20.053 5.88 21.107 ;
     RECT  4.56 21.107 5.412 21.155 ;
     RECT  18.048 17.315 19.512 21.155 ;
     RECT  37.5 17.363 38.664 21.157 ;
     RECT  10.5 20.819 11.448 21.251 ;
     RECT  7.8 18.755 8.28 21.397 ;
     RECT  42.9 20.003 43.212 21.493 ;
     RECT  10.5 21.251 10.812 21.637 ;
     RECT  18.6 21.155 19.512 21.637 ;
     RECT  21.3 18.851 21.612 21.637 ;
     RECT  28.128 21.013 30.6 21.637 ;
     RECT  34.8 20.579 36.456 21.683 ;
     RECT  39.888 20.869 40.512 21.731 ;
     RECT  23.76 21.013 24.408 21.781 ;
     RECT  13.104 20.819 13.512 21.875 ;
     RECT  22.8 21.781 24.408 22.019 ;
     RECT  7.8 21.397 8.424 22.117 ;
     RECT  2.4 21.059 2.712 22.165 ;
     RECT  37.5 21.157 38.808 22.165 ;
     RECT  28.128 21.637 30.84 22.211 ;
     RECT  42.336 21.493 43.212 22.211 ;
     RECT  29.4 22.211 30.84 22.213 ;
     RECT  32.1 20.579 32.412 22.213 ;
     RECT  37.392 22.165 38.808 22.259 ;
     RECT  28.128 22.211 28.152 22.403 ;
     RECT  23.76 22.019 24.408 22.547 ;
     RECT  29.4 22.213 32.412 22.645 ;
     RECT  42.9 22.211 43.212 22.693 ;
     RECT  34.8 21.683 35.736 22.741 ;
     RECT  37.392 22.259 38.424 22.787 ;
     RECT  14.976 21.061 16.872 22.835 ;
     RECT  18.6 21.637 21.612 22.835 ;
     RECT  42.9 22.693 43.944 22.835 ;
     RECT  4.896 21.155 5.412 22.883 ;
     RECT  20.352 22.835 21.612 22.931 ;
     RECT  29.4 22.645 33.048 22.931 ;
     RECT  2.4 22.165 2.856 23.027 ;
     RECT  9.888 21.637 10.812 23.267 ;
     RECT  21.3 22.931 21.612 23.269 ;
     RECT  32.1 22.931 33.048 23.411 ;
     RECT  37.5 22.787 38.424 23.843 ;
     RECT  7.8 22.117 8.52 23.987 ;
     RECT  34.8 22.741 36.312 23.987 ;
     RECT  21.3 23.269 21.96 24.035 ;
     RECT  18.6 22.835 19.08 24.131 ;
     RECT  13.2 21.875 13.512 24.469 ;
     RECT  15.9 22.835 16.872 24.469 ;
     RECT  21.3 24.035 21.612 24.469 ;
     RECT  40.2 21.731 40.512 24.469 ;
     RECT  26.7 20.003 27.012 24.661 ;
     RECT  26.592 24.661 27.012 24.803 ;
     RECT  48.3 10.883 48.612 24.997 ;
     RECT  2.4 23.027 2.712 25.045 ;
     RECT  23.76 22.547 24.312 25.045 ;
     RECT  40.2 24.469 41.496 25.139 ;
     RECT  42.9 22.835 43.848 25.139 ;
     RECT  40.2 25.139 40.512 25.285 ;
     RECT  2.4 25.045 3.384 25.525 ;
     RECT  5.1 22.883 5.412 25.525 ;
     RECT  34.8 23.987 35.736 25.715 ;
     RECT  47.52 24.997 48.612 25.715 ;
     RECT  45.6 18.035 45.912 25.717 ;
     RECT  12 25.621 12.024 25.763 ;
     RECT  10.5 23.267 10.812 25.813 ;
     RECT  7.8 23.987 8.424 25.955 ;
     RECT  13.2 24.469 14.232 25.955 ;
     RECT  23.472 25.045 24.312 26.005 ;
     RECT  23.472 26.005 24.408 26.051 ;
     RECT  29.4 22.931 29.712 26.053 ;
     RECT  2.4 25.525 5.412 26.243 ;
     RECT  20.544 24.469 21.612 26.485 ;
     RECT  18.6 24.131 18.912 26.725 ;
     RECT  34.8 25.715 35.256 26.725 ;
     RECT  42.9 25.139 43.212 26.725 ;
     RECT  4.128 26.243 5.412 26.771 ;
     RECT  40.08 25.285 40.512 26.771 ;
     RECT  23.76 26.051 24.408 26.819 ;
     RECT  29.4 26.053 30.216 26.965 ;
     RECT  7.8 25.955 8.112 27.205 ;
     RECT  15.552 24.469 16.872 27.301 ;
     RECT  18.432 26.725 18.912 27.301 ;
     RECT  37.5 23.843 37.812 27.301 ;
     RECT  14.784 27.301 16.872 27.395 ;
     RECT  20.448 26.485 21.612 27.395 ;
     RECT  42.9 26.725 43.848 27.395 ;
     RECT  37.5 27.301 38.376 27.781 ;
     RECT  28.512 26.965 30.216 27.875 ;
     RECT  10.032 25.813 10.812 27.877 ;
     RECT  15.9 27.395 16.872 27.877 ;
     RECT  45.6 25.717 46.008 27.877 ;
     RECT  7.8 27.205 8.52 27.971 ;
     RECT  14.784 27.395 14.808 27.971 ;
     RECT  34.8 26.725 35.352 27.971 ;
     RECT  32.1 23.411 32.412 28.261 ;
     RECT  4.992 26.771 5.412 28.403 ;
     RECT  42.9 27.395 43.212 28.453 ;
     RECT  25.488 25.861 25.512 28.547 ;
     RECT  15.9 27.877 17.208 28.835 ;
     RECT  37.5 27.781 39 28.835 ;
     RECT  18.336 27.301 18.912 28.931 ;
     RECT  41.808 26.773 41.832 28.931 ;
     RECT  9.696 27.877 10.812 28.979 ;
     RECT  14.544 28.645 14.568 28.979 ;
     RECT  13.2 25.955 13.512 28.981 ;
     RECT  28.512 27.875 29.712 29.123 ;
     RECT  32.1 28.261 33.048 29.123 ;
     RECT  44.928 27.877 46.008 29.123 ;
     RECT  42.9 28.453 43.368 29.315 ;
     RECT  34.8 27.971 35.112 29.605 ;
     RECT  23.76 26.819 24.312 30.181 ;
     RECT  32.1 29.123 32.412 30.421 ;
     RECT  40.2 26.771 40.512 30.469 ;
     RECT  26.7 24.803 27.012 30.613 ;
     RECT  28.896 29.123 29.712 30.613 ;
     RECT  7.8 27.971 8.376 30.709 ;
     RECT  10.5 28.979 10.812 30.709 ;
     RECT  42.9 29.315 43.212 30.709 ;
     RECT  26.7 30.613 29.712 30.755 ;
     RECT  21.3 27.395 21.612 30.757 ;
     RECT  37.5 28.835 38.376 30.757 ;
     RECT  23.76 30.181 24.504 30.851 ;
     RECT  37.5 30.757 38.472 30.949 ;
     RECT  40.2 30.469 40.632 31.093 ;
     RECT  26.7 30.755 27.012 31.285 ;
     RECT  28.464 30.755 29.712 31.285 ;
     RECT  40.08 31.093 40.632 31.379 ;
     RECT  42.192 30.709 43.212 31.379 ;
     RECT  15.9 28.835 16.872 31.381 ;
     RECT  34.656 29.605 35.112 31.427 ;
     RECT  31.968 30.421 32.412 31.715 ;
     RECT  20.448 30.757 21.612 31.861 ;
     RECT  13.2 28.981 13.848 31.955 ;
     RECT  42.768 31.379 43.212 32.003 ;
     RECT  18.432 28.931 18.912 32.005 ;
     RECT  18.336 32.005 18.912 32.293 ;
     RECT  37.5 30.949 38.712 32.293 ;
     RECT  10.224 30.709 10.812 32.341 ;
     RECT  6.816 30.709 8.376 32.531 ;
     RECT  20.448 31.861 21.816 32.531 ;
     RECT  21.3 32.531 21.816 32.579 ;
     RECT  7.8 32.531 8.376 32.581 ;
     RECT  15.312 31.381 16.872 32.723 ;
     RECT  44.208 31.861 44.232 32.771 ;
     RECT  2.4 26.243 2.712 32.821 ;
     RECT  2.304 32.821 2.712 33.011 ;
     RECT  2.4 33.011 2.712 33.013 ;
     RECT  9.792 32.341 10.812 33.059 ;
     RECT  5.1 28.403 5.412 33.061 ;
     RECT  23.76 30.851 24.312 33.541 ;
     RECT  25.968 31.285 27.012 33.541 ;
     RECT  33.744 32.197 33.768 33.587 ;
     RECT  37.5 32.293 39 33.589 ;
     RECT  28.464 31.285 29.928 33.731 ;
     RECT  28.8 33.731 29.928 33.779 ;
     RECT  37.392 33.589 39 33.779 ;
     RECT  5.1 33.061 6.312 33.971 ;
     RECT  2.4 33.013 3.528 34.115 ;
     RECT  23.76 33.541 27.012 34.259 ;
     RECT  37.392 33.779 38.472 34.259 ;
     RECT  18.336 32.293 19.032 34.403 ;
     RECT  18.336 34.403 18.912 34.741 ;
     RECT  23.76 34.259 25.08 34.931 ;
     RECT  28.8 33.779 29.712 34.931 ;
     RECT  13.2 31.955 13.512 35.077 ;
     RECT  40.2 31.379 40.632 35.077 ;
     RECT  23.76 34.931 24.312 35.317 ;
     RECT  21.3 32.579 21.612 35.413 ;
     RECT  18.192 34.741 18.912 35.459 ;
     RECT  10.5 33.059 10.812 35.845 ;
     RECT  15.9 32.723 16.872 35.845 ;
     RECT  32.1 31.715 32.412 35.893 ;
     RECT  21.3 35.413 22.2 35.987 ;
     RECT  26.7 34.259 27.012 35.989 ;
     RECT  40.2 35.077 41.208 36.085 ;
     RECT  12.432 35.077 13.512 36.515 ;
     RECT  33.648 35.845 33.672 36.515 ;
     RECT  7.8 32.581 8.52 36.565 ;
     RECT  10.128 35.845 10.812 36.565 ;
     RECT  40.08 36.085 41.208 36.755 ;
     RECT  7.8 36.565 10.812 36.851 ;
     RECT  26.7 35.989 27.288 36.851 ;
     RECT  10.128 36.851 10.812 36.949 ;
     RECT  42.9 32.003 43.212 37.045 ;
     RECT  23.664 35.317 24.312 37.091 ;
     RECT  37.5 34.259 38.472 37.093 ;
     RECT  5.1 33.971 5.412 37.285 ;
     RECT  21.3 35.987 21.612 37.429 ;
     RECT  10.128 36.949 11.448 37.475 ;
     RECT  34.8 31.427 35.112 37.573 ;
     RECT  37.5 37.093 38.568 37.573 ;
     RECT  42.9 37.045 44.04 37.619 ;
     RECT  31.872 35.893 32.412 37.861 ;
     RECT  7.8 36.851 8.808 38.147 ;
     RECT  5.1 37.285 5.544 38.149 ;
     RECT  40.08 36.755 40.512 38.149 ;
     RECT  20.064 36.421 20.088 38.195 ;
     RECT  5.1 38.149 6.072 38.197 ;
     RECT  37.5 37.573 39 38.245 ;
     RECT  14.976 35.845 16.872 38.483 ;
     RECT  10.5 37.475 11.448 38.675 ;
     RECT  34.8 37.573 35.352 38.675 ;
     RECT  23.856 37.091 24.312 38.677 ;
     RECT  25.68 38.149 25.704 38.677 ;
     RECT  42.9 37.619 43.212 38.725 ;
     RECT  40.08 38.149 41.064 38.773 ;
     RECT  40.08 38.773 41.4 38.819 ;
     RECT  4.272 38.197 6.072 39.107 ;
     RECT  21.3 37.429 22.2 39.395 ;
     RECT  33.648 38.149 33.672 39.395 ;
     RECT  37.392 38.245 39 39.395 ;
     RECT  40.2 38.819 41.4 39.395 ;
     RECT  42.9 38.725 43.944 39.731 ;
     RECT  23.856 38.677 25.704 39.779 ;
     RECT  7.8 38.147 8.52 39.781 ;
     RECT  37.5 39.395 39 40.019 ;
     RECT  28.944 34.931 29.712 40.115 ;
     RECT  23.856 39.779 24.312 40.405 ;
     RECT  18.336 35.459 18.912 40.645 ;
     RECT  5.1 39.107 6.072 40.741 ;
     RECT  31.392 37.861 32.412 40.837 ;
     RECT  26.7 36.851 27.012 40.981 ;
     RECT  42.9 39.731 43.212 40.981 ;
     RECT  25.632 39.779 25.704 41.075 ;
     RECT  22.608 40.405 22.632 41.123 ;
     RECT  7.8 39.781 9.096 41.125 ;
     RECT  7.8 41.125 9.48 41.267 ;
     RECT  25.68 41.075 25.704 41.269 ;
     RECT  26.7 40.981 27.768 41.269 ;
     RECT  7.8 41.267 9.096 41.363 ;
     RECT  25.68 41.269 27.768 41.411 ;
     RECT  15.9 38.483 16.872 41.509 ;
     RECT  21.3 39.395 21.612 41.557 ;
     RECT  31.344 40.837 32.412 41.603 ;
     RECT  45.6 29.123 46.008 41.699 ;
     RECT  10.5 38.675 10.812 41.749 ;
     RECT  15.408 41.509 16.872 41.749 ;
     RECT  34.8 38.675 35.112 41.749 ;
     RECT  5.1 40.741 6.312 41.795 ;
     RECT  20.448 41.557 21.612 41.797 ;
     RECT  18.24 40.645 18.912 41.843 ;
     RECT  31.68 41.603 32.412 41.845 ;
     RECT  40.2 39.395 40.632 41.893 ;
     RECT  14.784 41.749 16.872 41.987 ;
     RECT  37.5 40.019 38.568 41.989 ;
     RECT  29.04 40.115 29.712 42.035 ;
     RECT  31.68 41.845 33.048 42.035 ;
     RECT  2.4 34.115 2.712 42.085 ;
     RECT  7.8 41.363 8.52 42.179 ;
     RECT  42.432 40.981 43.212 42.179 ;
     RECT  20.304 41.797 21.612 42.227 ;
     RECT  26.064 41.411 27.768 42.227 ;
     RECT  2.4 42.085 2.856 42.275 ;
     RECT  23.664 40.405 24.312 42.611 ;
     RECT  21.3 42.227 21.612 42.757 ;
     RECT  31.68 42.035 32.412 42.851 ;
     RECT  21.3 42.757 21.72 42.899 ;
     RECT  37.5 41.989 38.808 42.899 ;
     RECT  38.784 42.899 38.808 42.995 ;
     RECT  10.32 41.749 10.812 42.997 ;
     RECT  10.32 42.997 11.688 43.043 ;
     RECT  5.1 41.795 5.832 43.379 ;
     RECT  10.368 43.043 11.688 43.379 ;
     RECT  15.408 41.987 16.872 43.379 ;
     RECT  20.304 42.227 20.328 43.379 ;
     RECT  26.208 42.227 27.012 43.379 ;
     RECT  34.8 41.749 35.736 43.379 ;
     RECT  18.336 41.843 18.912 43.523 ;
     RECT  10.5 43.379 11.688 43.571 ;
     RECT  40.2 41.893 41.016 43.955 ;
     RECT  15.408 43.379 16.344 44.051 ;
     RECT  31.104 43.573 31.128 44.483 ;
     RECT  15.9 44.051 16.344 45.203 ;
     RECT  29.088 42.035 29.712 45.299 ;
     RECT  2.4 42.275 2.712 45.369 ;
     RECT  5.1 43.379 5.412 45.369 ;
     RECT  7.8 42.179 8.112 45.369 ;
     RECT  10.5 43.571 10.812 45.369 ;
     RECT  13.2 36.515 13.512 45.369 ;
     RECT  15.9 45.203 16.212 45.369 ;
     RECT  18.6 43.523 18.912 45.369 ;
     RECT  21.3 42.899 21.612 45.369 ;
     RECT  24 42.611 24.312 45.369 ;
     RECT  26.7 43.379 27.012 45.369 ;
     RECT  29.4 45.299 29.712 45.369 ;
     RECT  32.1 42.851 32.412 45.369 ;
     RECT  34.8 43.379 35.112 45.369 ;
     RECT  37.5 42.899 37.812 45.369 ;
     RECT  40.2 43.955 40.512 45.369 ;
     RECT  42.9 42.179 43.212 45.369 ;
     RECT  45.6 41.699 45.912 45.369 ;
     RECT  48.3 25.715 48.612 45.369 ;
     RECT  2.4 45.369 2.52 45.383 ;
     RECT  5.1 45.369 5.22 45.383 ;
     RECT  7.8 45.369 7.92 45.383 ;
     RECT  10.5 45.369 10.62 45.383 ;
     RECT  13.2 45.369 13.32 45.383 ;
     RECT  15.9 45.369 16.02 45.383 ;
     RECT  18.6 45.369 18.72 45.383 ;
     RECT  21.3 45.369 21.42 45.383 ;
     RECT  24 45.369 24.12 45.383 ;
     RECT  26.7 45.369 26.82 45.383 ;
     RECT  29.4 45.369 29.52 45.383 ;
     RECT  32.1 45.369 32.22 45.383 ;
     RECT  34.8 45.369 34.92 45.383 ;
     RECT  37.5 45.369 37.62 45.383 ;
     RECT  40.2 45.369 40.32 45.383 ;
     RECT  42.9 45.369 43.02 45.383 ;
     RECT  45.6 45.369 45.72 45.383 ;
     RECT  48.3 45.369 48.42 45.383 ;
     RECT  13.512 2.725 14.592 3.155 ;
     RECT  14.616 2.725 15.9 3.109 ;
     RECT  27.012 2.725 28.416 4.115 ;
     RECT  5.412 2.821 6.48 3.539 ;
     RECT  6.504 2.821 7.8 3.539 ;
     RECT  14.712 3.109 15.9 3.923 ;
     RECT  13.512 3.155 14.688 3.923 ;
     RECT  38.808 3.493 40.2 3.875 ;
     RECT  37.812 3.539 38.784 3.875 ;
     RECT  39.552 3.875 40.2 4.117 ;
     RECT  13.512 3.923 15.9 3.925 ;
     RECT  13.512 3.925 14.784 5.461 ;
     RECT  14.808 3.925 15.9 6.035 ;
     RECT  27.012 4.115 28.512 5.653 ;
     RECT  39.552 4.117 39.888 4.357 ;
     RECT  19.944 4.405 21.3 4.501 ;
     RECT  20.136 4.501 21.3 6.275 ;
     RECT  23.376 4.643 24 5.125 ;
     RECT  16.212 4.741 17.616 5.987 ;
     RECT  35.112 5.077 36.48 5.747 ;
     RECT  36.504 5.077 37.5 5.747 ;
     RECT  21.612 5.125 22.8 5.267 ;
     RECT  22.824 5.125 24 5.267 ;
     RECT  2.808 5.219 3.336 6.179 ;
     RECT  27.012 5.653 27.984 6.611 ;
     RECT  8.112 5.747 8.232 6.805 ;
     RECT  14.424 6.035 15.9 7.043 ;
     RECT  2.712 6.179 3.336 6.181 ;
     RECT  2.712 6.181 3.984 7.667 ;
     RECT  4.008 6.181 5.1 7.667 ;
     RECT  27.012 6.611 28.08 9.541 ;
     RECT  8.112 6.805 9.12 7.093 ;
     RECT  9.144 6.805 10.5 7.427 ;
     RECT  28.104 6.851 29.4 10.789 ;
     RECT  15.408 7.043 15.9 7.957 ;
     RECT  10.368 7.427 10.5 8.437 ;
     RECT  2.712 7.667 5.1 8.437 ;
     RECT  19.848 7.957 21.3 8.243 ;
     RECT  22.536 8.197 24 8.341 ;
     RECT  19.512 8.243 21.3 9.493 ;
     RECT  25.272 8.293 26.7 9.493 ;
     RECT  22.536 8.341 23.568 8.915 ;
     RECT  3.624 8.437 5.1 8.485 ;
     RECT  3.624 8.485 4.992 9.731 ;
     RECT  46.104 8.531 46.152 9.637 ;
     RECT  22.536 8.915 24 10.067 ;
     RECT  20.232 9.493 21.3 12.035 ;
     RECT  25.32 9.493 26.7 11.459 ;
     RECT  24.312 9.635 25.296 11.459 ;
     RECT  46.104 9.637 47.424 10.883 ;
     RECT  35.208 10.019 35.352 11.365 ;
     RECT  38.424 10.021 39.888 11.173 ;
     RECT  18 10.115 18.192 10.933 ;
     RECT  13.944 10.213 15.216 10.883 ;
     RECT  27.012 10.307 28.08 10.835 ;
     RECT  8.28 10.693 9.696 11.125 ;
     RECT  28.2 10.789 29.4 14.197 ;
     RECT  27.012 10.835 28.176 13.621 ;
     RECT  13.944 10.883 15.9 11.219 ;
     RECT  16.92 10.933 18.192 12.227 ;
     RECT  40.512 11.027 41.208 11.365 ;
     RECT  8.376 11.125 9.696 11.651 ;
     RECT  38.616 11.173 39.888 11.219 ;
     RECT  13.512 11.219 15.9 11.365 ;
     RECT  13.512 11.365 14.832 12.035 ;
     RECT  14.856 11.365 15.9 12.035 ;
     RECT  35.208 11.365 36.432 11.459 ;
     RECT  36.456 11.365 37.5 12.563 ;
     RECT  40.512 11.365 41.568 12.515 ;
     RECT  41.592 11.365 42.9 12.515 ;
     RECT  35.112 11.459 36.432 12.563 ;
     RECT  19.512 12.035 21.3 13.045 ;
     RECT  16.68 12.227 18.192 13.237 ;
     RECT  35.112 12.563 35.352 13.621 ;
     RECT  37.296 12.563 37.5 13.621 ;
     RECT  34.368 13.043 34.8 13.621 ;
     RECT  19.992 13.045 21.3 13.381 ;
     RECT  16.68 13.237 17.904 14.917 ;
     RECT  19.992 13.381 21.072 14.435 ;
     RECT  32.412 13.621 33.6 14.197 ;
     RECT  33.624 13.621 34.8 14.627 ;
     RECT  13.608 13.909 14.832 14.195 ;
     RECT  14.856 13.909 15.9 14.195 ;
     RECT  13.608 14.195 15.9 14.533 ;
     RECT  37.296 14.387 37.5 15.445 ;
     RECT  19.512 14.435 21.072 14.773 ;
     RECT  13.704 14.533 15.9 15.061 ;
     RECT  19.512 14.773 20.496 15.877 ;
     RECT  38.808 14.773 40.2 15.491 ;
     RECT  25.272 14.821 26.7 15.301 ;
     RECT  10.32 14.915 10.5 15.925 ;
     RECT  16.728 14.917 17.904 15.925 ;
     RECT  29.712 14.917 30.72 17.699 ;
     RECT  30.744 14.917 32.1 16.405 ;
     RECT  35.112 14.963 35.544 15.445 ;
     RECT  27.672 15.059 28.656 15.683 ;
     RECT  13.704 15.061 15.168 15.445 ;
     RECT  25.464 15.301 26.7 17.123 ;
     RECT  24.312 15.395 25.44 17.123 ;
     RECT  13.704 15.445 14.832 15.541 ;
     RECT  35.112 15.445 36.288 16.405 ;
     RECT  36.312 15.445 37.5 16.499 ;
     RECT  38.664 15.491 40.2 15.541 ;
     RECT  38.664 15.541 39.936 16.501 ;
     RECT  14.184 15.923 15.168 16.259 ;
     RECT  8.28 15.925 9.648 17.075 ;
     RECT  35.208 16.405 36.288 16.499 ;
     RECT  38.808 16.501 39.936 16.691 ;
     RECT  19.512 16.547 20.496 17.171 ;
     RECT  38.808 16.691 40.2 17.363 ;
     RECT  8.28 17.075 8.616 17.605 ;
     RECT  15.36 17.123 15.9 18.133 ;
     RECT  24.312 17.123 26.7 17.605 ;
     RECT  4.848 17.171 5.1 17.461 ;
     RECT  16.968 17.315 18.048 18.419 ;
     RECT  2.712 17.461 3.696 18.515 ;
     RECT  3.72 17.461 5.1 18.515 ;
     RECT  24.312 17.605 25.632 18.707 ;
     RECT  25.656 17.605 26.7 18.707 ;
     RECT  30.744 17.651 32.1 17.699 ;
     RECT  29.712 17.699 29.832 18.661 ;
     RECT  35.112 17.699 35.208 18.757 ;
     RECT  44.472 17.989 45.6 20.291 ;
     RECT  5.412 18.419 5.784 19.669 ;
     RECT  16.872 18.419 18.048 21.155 ;
     RECT  10.812 18.757 12.288 20.533 ;
     RECT  29.712 18.803 29.832 19.861 ;
     RECT  43.212 19.523 44.448 20.291 ;
     RECT  36.36 19.813 37.5 20.101 ;
     RECT  29.712 19.861 31.344 20.197 ;
     RECT  27.012 20.003 27.144 21.013 ;
     RECT  42.48 20.003 42.9 21.493 ;
     RECT  36.456 20.101 37.5 21.683 ;
     RECT  30.6 20.579 32.1 21.637 ;
     RECT  38.664 20.869 39.888 21.157 ;
     RECT  27.012 21.013 28.128 22.403 ;
     RECT  13.512 21.061 14.976 22.835 ;
     RECT  38.808 21.157 39.888 21.731 ;
     RECT  8.424 21.637 9.888 22.117 ;
     RECT  30.84 21.637 32.1 22.213 ;
     RECT  35.736 21.683 37.5 22.165 ;
     RECT  38.808 21.731 40.2 22.259 ;
     RECT  21.612 21.781 22.8 22.019 ;
     RECT  21.612 22.019 21.96 23.269 ;
     RECT  8.52 22.117 9.888 23.267 ;
     RECT  35.736 22.165 37.392 22.741 ;
     RECT  28.152 22.211 29.4 22.403 ;
     RECT  36.312 22.741 37.392 22.787 ;
     RECT  36.312 22.787 37.5 23.987 ;
     RECT  19.08 22.835 20.352 22.931 ;
     RECT  14.232 24.469 15.552 25.955 ;
     RECT  41.496 24.469 42.9 25.139 ;
     RECT  26.592 24.803 26.7 25.861 ;
     RECT  10.812 25.621 12 25.763 ;
     RECT  12.024 25.621 13.2 25.763 ;
     RECT  35.256 25.715 35.352 26.725 ;
     RECT  24.312 25.861 25.488 26.005 ;
     RECT  25.512 25.861 26.7 28.547 ;
     RECT  8.112 25.955 8.424 27.205 ;
     RECT  13.512 25.955 15.552 27.301 ;
     RECT  24.408 26.005 25.488 26.819 ;
     RECT  2.712 26.243 4.128 26.771 ;
     RECT  40.08 26.771 40.2 27.781 ;
     RECT  40.512 26.773 41.808 28.931 ;
     RECT  41.832 26.773 42.9 28.931 ;
     RECT  24.312 26.819 25.488 28.547 ;
     RECT  27.012 26.965 28.512 29.123 ;
     RECT  8.52 27.205 10.032 27.877 ;
     RECT  13.512 27.301 14.784 27.971 ;
     RECT  16.872 27.301 18.336 27.877 ;
     RECT  14.808 27.395 15.9 27.971 ;
     RECT  43.212 27.395 43.368 28.453 ;
     RECT  39 27.781 40.2 28.835 ;
     RECT  8.52 27.877 9.696 27.971 ;
     RECT  17.208 27.877 18.336 28.835 ;
     RECT  8.376 27.971 9.696 28.979 ;
     RECT  13.512 27.971 15.9 28.645 ;
     RECT  13.512 28.645 14.544 28.979 ;
     RECT  14.568 28.645 15.9 28.979 ;
     RECT  16.872 28.835 18.336 28.931 ;
     RECT  13.512 28.979 13.848 28.981 ;
     RECT  27.012 29.123 28.896 30.613 ;
     RECT  5.412 30.709 6.816 32.531 ;
     RECT  27.012 30.755 28.464 33.731 ;
     RECT  38.712 30.949 40.2 31.093 ;
     RECT  38.712 31.093 40.08 31.379 ;
     RECT  38.712 31.379 40.2 32.293 ;
     RECT  13.848 31.381 15.312 31.955 ;
     RECT  34.656 31.427 34.8 32.197 ;
     RECT  43.212 31.861 44.208 32.771 ;
     RECT  44.232 31.861 45.6 32.771 ;
     RECT  16.872 32.005 18.336 34.741 ;
     RECT  32.412 32.197 33.744 33.587 ;
     RECT  33.768 32.197 34.8 33.587 ;
     RECT  19.032 32.293 20.448 32.531 ;
     RECT  39 32.293 40.2 33.779 ;
     RECT  8.376 32.341 9.792 32.581 ;
     RECT  5.412 32.531 7.8 33.061 ;
     RECT  8.52 32.581 9.792 33.059 ;
     RECT  6.312 33.061 7.8 33.971 ;
     RECT  16.872 34.741 18.192 35.459 ;
     RECT  22.2 35.413 23.664 35.987 ;
     RECT  16.872 35.459 18.336 40.645 ;
     RECT  13.512 35.845 14.976 38.483 ;
     RECT  32.412 35.845 33.648 36.515 ;
     RECT  33.672 35.845 34.8 36.515 ;
     RECT  21.612 35.987 23.664 37.091 ;
     RECT  18.912 36.421 20.064 38.195 ;
     RECT  20.088 36.421 21.3 38.195 ;
     RECT  40.512 36.755 41.064 38.149 ;
     RECT  8.808 36.851 10.128 37.475 ;
     RECT  21.612 37.091 22.2 37.429 ;
     RECT  38.568 37.093 40.08 37.573 ;
     RECT  39 37.573 40.08 38.819 ;
     RECT  43.212 37.619 43.944 38.725 ;
     RECT  24.312 38.149 25.68 38.677 ;
     RECT  25.704 38.149 26.7 41.269 ;
     RECT  32.412 38.149 33.648 39.395 ;
     RECT  33.672 38.149 34.8 39.395 ;
     RECT  41.4 38.773 42.9 39.395 ;
     RECT  39 38.819 40.2 40.019 ;
     RECT  21.612 39.395 22.2 40.405 ;
     RECT  24.312 39.779 25.632 41.075 ;
     RECT  9.096 39.781 10.5 41.125 ;
     RECT  28.944 40.115 29.04 40.981 ;
     RECT  21.612 40.405 22.608 41.123 ;
     RECT  22.632 40.405 23.664 41.123 ;
     RECT  16.872 40.645 18.24 41.843 ;
     RECT  6.312 40.741 7.8 41.795 ;
     RECT  27.768 40.981 29.04 42.035 ;
     RECT  24.312 41.075 25.68 41.411 ;
     RECT  9.48 41.125 10.5 41.267 ;
     RECT  9.096 41.267 10.5 41.363 ;
     RECT  10.32 41.363 10.5 41.749 ;
     RECT  13.512 41.749 14.784 41.987 ;
     RECT  18.912 41.797 20.304 43.379 ;
     RECT  16.872 41.843 18.336 43.379 ;
     RECT  41.016 41.893 42.432 42.179 ;
     RECT  38.808 41.989 40.2 42.995 ;
     RECT  27.768 42.035 29.088 42.227 ;
     RECT  20.328 42.227 21.3 43.379 ;
     RECT  31.68 42.851 32.1 43.573 ;
     RECT  37.812 42.899 38.784 42.995 ;
     RECT  11.688 42.997 13.2 43.571 ;
     RECT  29.712 43.573 31.104 44.483 ;
     RECT  31.128 43.573 32.1 44.483 ;
  END
END qkd_landsh0_296
END LIBRARY
